VERSION 5.8 ;
BUSBITCHARS "[]" ;
DIVIDERCHAR "/" ;
UNITS
    DATABASE MICRONS 1000 ;
END UNITS

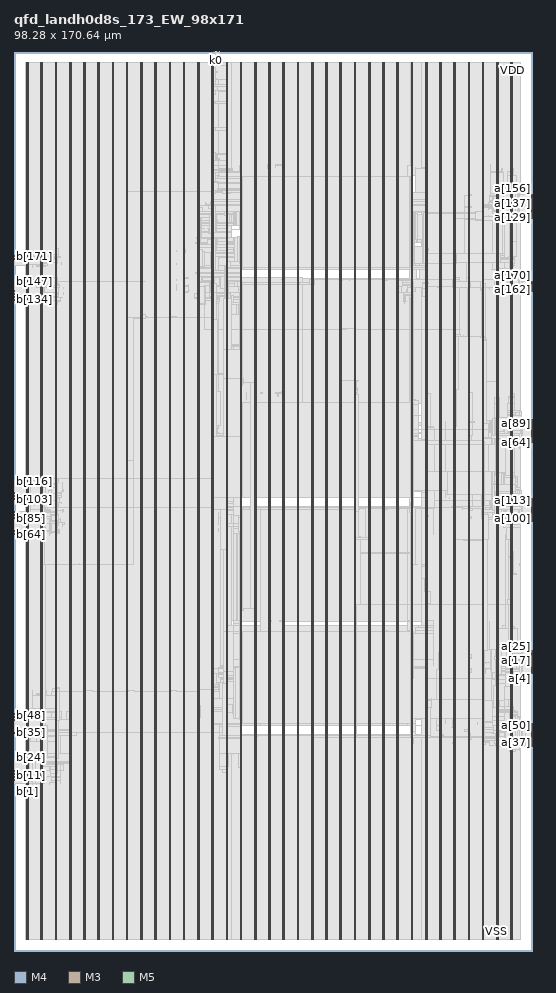
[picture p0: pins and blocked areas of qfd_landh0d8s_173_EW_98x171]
MACRO qfd_landh0d8s_173_EW_98x171
  FOREIGN qfd_landh0d8s_173_EW_98x171 0 0 ;
  CLASS BLOCK ;
  SIZE 98.28 BY 170.64 ;
  PIN a[0]
    DIRECTION INPUT ;
    USE SIGNAL ;
    PORT
      LAYER M4 ;
        RECT  98.196 52.56 98.28 52.584 ;
    END
  END a[0]
  PIN a[100]
    DIRECTION INPUT ;
    USE SIGNAL ;
    PORT
      LAYER M4 ;
        RECT  98.196 81.936 98.28 81.96 ;
    END
  END a[100]
  PIN a[101]
    DIRECTION INPUT ;
    USE SIGNAL ;
    PORT
      LAYER M4 ;
        RECT  98.196 82.08 98.28 82.104 ;
    END
  END a[101]
  PIN a[102]
    DIRECTION INPUT ;
    USE SIGNAL ;
    PORT
      LAYER M4 ;
        RECT  98.196 82.224 98.28 82.248 ;
    END
  END a[102]
  PIN a[103]
    DIRECTION INPUT ;
    USE SIGNAL ;
    PORT
      LAYER M4 ;
        RECT  98.196 82.368 98.28 82.392 ;
    END
  END a[103]
  PIN a[104]
    DIRECTION INPUT ;
    USE SIGNAL ;
    PORT
      LAYER M4 ;
        RECT  98.196 82.512 98.28 82.536 ;
    END
  END a[104]
  PIN a[105]
    DIRECTION INPUT ;
    USE SIGNAL ;
    PORT
      LAYER M4 ;
        RECT  98.196 82.656 98.28 82.68 ;
    END
  END a[105]
  PIN a[106]
    DIRECTION INPUT ;
    USE SIGNAL ;
    PORT
      LAYER M4 ;
        RECT  98.196 82.8 98.28 82.824 ;
    END
  END a[106]
  PIN a[107]
    DIRECTION INPUT ;
    USE SIGNAL ;
    PORT
      LAYER M4 ;
        RECT  98.196 82.944 98.28 82.968 ;
    END
  END a[107]
  PIN a[108]
    DIRECTION INPUT ;
    USE SIGNAL ;
    PORT
      LAYER M4 ;
        RECT  98.196 83.088 98.28 83.112 ;
    END
  END a[108]
  PIN a[109]
    DIRECTION INPUT ;
    USE SIGNAL ;
    PORT
      LAYER M4 ;
        RECT  98.196 83.232 98.28 83.256 ;
    END
  END a[109]
  PIN a[10]
    DIRECTION INPUT ;
    USE SIGNAL ;
    PORT
      LAYER M4 ;
        RECT  98.196 54 98.28 54.024 ;
    END
  END a[10]
  PIN a[110]
    DIRECTION INPUT ;
    USE SIGNAL ;
    PORT
      LAYER M4 ;
        RECT  98.196 83.376 98.28 83.4 ;
    END
  END a[110]
  PIN a[111]
    DIRECTION INPUT ;
    USE SIGNAL ;
    PORT
      LAYER M4 ;
        RECT  98.196 83.52 98.28 83.544 ;
    END
  END a[111]
  PIN a[112]
    DIRECTION INPUT ;
    USE SIGNAL ;
    PORT
      LAYER M4 ;
        RECT  98.196 83.664 98.28 83.688 ;
    END
  END a[112]
  PIN a[113]
    DIRECTION INPUT ;
    USE SIGNAL ;
    PORT
      LAYER M4 ;
        RECT  98.196 83.808 98.28 83.832 ;
    END
  END a[113]
  PIN a[114]
    DIRECTION INPUT ;
    USE SIGNAL ;
    PORT
      LAYER M4 ;
        RECT  98.196 83.952 98.28 83.976 ;
    END
  END a[114]
  PIN a[115]
    DIRECTION INPUT ;
    USE SIGNAL ;
    PORT
      LAYER M4 ;
        RECT  98.196 84.096 98.28 84.12 ;
    END
  END a[115]
  PIN a[116]
    DIRECTION INPUT ;
    USE SIGNAL ;
    PORT
      LAYER M4 ;
        RECT  98.196 84.24 98.28 84.264 ;
    END
  END a[116]
  PIN a[117]
    DIRECTION INPUT ;
    USE SIGNAL ;
    PORT
      LAYER M4 ;
        RECT  98.196 84.384 98.28 84.408 ;
    END
  END a[117]
  PIN a[118]
    DIRECTION INPUT ;
    USE SIGNAL ;
    PORT
      LAYER M4 ;
        RECT  98.196 84.528 98.28 84.552 ;
    END
  END a[118]
  PIN a[119]
    DIRECTION INPUT ;
    USE SIGNAL ;
    PORT
      LAYER M4 ;
        RECT  98.196 84.672 98.28 84.696 ;
    END
  END a[119]
  PIN a[11]
    DIRECTION INPUT ;
    USE SIGNAL ;
    PORT
      LAYER M4 ;
        RECT  98.196 54.144 98.28 54.168 ;
    END
  END a[11]
  PIN a[120]
    DIRECTION INPUT ;
    USE SIGNAL ;
    PORT
      LAYER M4 ;
        RECT  98.196 84.816 98.28 84.84 ;
    END
  END a[120]
  PIN a[121]
    DIRECTION INPUT ;
    USE SIGNAL ;
    PORT
      LAYER M4 ;
        RECT  98.196 84.96 98.28 84.984 ;
    END
  END a[121]
  PIN a[122]
    DIRECTION INPUT ;
    USE SIGNAL ;
    PORT
      LAYER M4 ;
        RECT  98.196 85.104 98.28 85.128 ;
    END
  END a[122]
  PIN a[123]
    DIRECTION INPUT ;
    USE SIGNAL ;
    PORT
      LAYER M4 ;
        RECT  98.196 85.248 98.28 85.272 ;
    END
  END a[123]
  PIN a[124]
    DIRECTION INPUT ;
    USE SIGNAL ;
    PORT
      LAYER M4 ;
        RECT  98.196 85.392 98.28 85.416 ;
    END
  END a[124]
  PIN a[125]
    DIRECTION INPUT ;
    USE SIGNAL ;
    PORT
      LAYER M4 ;
        RECT  98.196 85.536 98.28 85.56 ;
    END
  END a[125]
  PIN a[126]
    DIRECTION INPUT ;
    USE SIGNAL ;
    PORT
      LAYER M4 ;
        RECT  98.196 85.68 98.28 85.704 ;
    END
  END a[126]
  PIN a[127]
    DIRECTION INPUT ;
    USE SIGNAL ;
    PORT
      LAYER M4 ;
        RECT  98.196 85.824 98.28 85.848 ;
    END
  END a[127]
  PIN a[128]
    DIRECTION INPUT ;
    USE SIGNAL ;
    PORT
      LAYER M4 ;
        RECT  98.196 138.96 98.28 138.984 ;
    END
  END a[128]
  PIN a[129]
    DIRECTION INPUT ;
    USE SIGNAL ;
    PORT
      LAYER M4 ;
        RECT  98.196 139.104 98.28 139.128 ;
    END
  END a[129]
  PIN a[12]
    DIRECTION INPUT ;
    USE SIGNAL ;
    PORT
      LAYER M4 ;
        RECT  98.196 54.288 98.28 54.312 ;
    END
  END a[12]
  PIN a[130]
    DIRECTION INPUT ;
    USE SIGNAL ;
    PORT
      LAYER M4 ;
        RECT  98.196 139.248 98.28 139.272 ;
    END
  END a[130]
  PIN a[131]
    DIRECTION INPUT ;
    USE SIGNAL ;
    PORT
      LAYER M4 ;
        RECT  98.196 139.392 98.28 139.416 ;
    END
  END a[131]
  PIN a[132]
    DIRECTION INPUT ;
    USE SIGNAL ;
    PORT
      LAYER M4 ;
        RECT  98.196 139.536 98.28 139.56 ;
    END
  END a[132]
  PIN a[133]
    DIRECTION INPUT ;
    USE SIGNAL ;
    PORT
      LAYER M4 ;
        RECT  98.196 139.68 98.28 139.704 ;
    END
  END a[133]
  PIN a[134]
    DIRECTION INPUT ;
    USE SIGNAL ;
    PORT
      LAYER M4 ;
        RECT  98.196 139.824 98.28 139.848 ;
    END
  END a[134]
  PIN a[135]
    DIRECTION INPUT ;
    USE SIGNAL ;
    PORT
      LAYER M4 ;
        RECT  98.196 139.968 98.28 139.992 ;
    END
  END a[135]
  PIN a[136]
    DIRECTION INPUT ;
    USE SIGNAL ;
    PORT
      LAYER M4 ;
        RECT  98.196 140.112 98.28 140.136 ;
    END
  END a[136]
  PIN a[137]
    DIRECTION INPUT ;
    USE SIGNAL ;
    PORT
      LAYER M4 ;
        RECT  98.196 140.256 98.28 140.28 ;
    END
  END a[137]
  PIN a[138]
    DIRECTION INPUT ;
    USE SIGNAL ;
    PORT
      LAYER M4 ;
        RECT  98.196 140.4 98.28 140.424 ;
    END
  END a[138]
  PIN a[139]
    DIRECTION INPUT ;
    USE SIGNAL ;
    PORT
      LAYER M4 ;
        RECT  98.196 140.544 98.28 140.568 ;
    END
  END a[139]
  PIN a[13]
    DIRECTION INPUT ;
    USE SIGNAL ;
    PORT
      LAYER M4 ;
        RECT  98.196 54.432 98.28 54.456 ;
    END
  END a[13]
  PIN a[140]
    DIRECTION INPUT ;
    USE SIGNAL ;
    PORT
      LAYER M4 ;
        RECT  98.196 140.688 98.28 140.712 ;
    END
  END a[140]
  PIN a[141]
    DIRECTION INPUT ;
    USE SIGNAL ;
    PORT
      LAYER M4 ;
        RECT  98.196 140.832 98.28 140.856 ;
    END
  END a[141]
  PIN a[142]
    DIRECTION INPUT ;
    USE SIGNAL ;
    PORT
      LAYER M4 ;
        RECT  98.196 140.976 98.28 141 ;
    END
  END a[142]
  PIN a[143]
    DIRECTION INPUT ;
    USE SIGNAL ;
    PORT
      LAYER M4 ;
        RECT  98.196 141.12 98.28 141.144 ;
    END
  END a[143]
  PIN a[144]
    DIRECTION INPUT ;
    USE SIGNAL ;
    PORT
      LAYER M4 ;
        RECT  98.196 141.264 98.28 141.288 ;
    END
  END a[144]
  PIN a[145]
    DIRECTION INPUT ;
    USE SIGNAL ;
    PORT
      LAYER M4 ;
        RECT  98.196 141.408 98.28 141.432 ;
    END
  END a[145]
  PIN a[146]
    DIRECTION INPUT ;
    USE SIGNAL ;
    PORT
      LAYER M4 ;
        RECT  98.196 141.552 98.28 141.576 ;
    END
  END a[146]
  PIN a[147]
    DIRECTION INPUT ;
    USE SIGNAL ;
    PORT
      LAYER M4 ;
        RECT  98.196 141.696 98.28 141.72 ;
    END
  END a[147]
  PIN a[148]
    DIRECTION INPUT ;
    USE SIGNAL ;
    PORT
      LAYER M4 ;
        RECT  98.196 141.84 98.28 141.864 ;
    END
  END a[148]
  PIN a[149]
    DIRECTION INPUT ;
    USE SIGNAL ;
    PORT
      LAYER M4 ;
        RECT  98.196 141.984 98.28 142.008 ;
    END
  END a[149]
  PIN a[14]
    DIRECTION INPUT ;
    USE SIGNAL ;
    PORT
      LAYER M4 ;
        RECT  98.196 54.576 98.28 54.6 ;
    END
  END a[14]
  PIN a[150]
    DIRECTION INPUT ;
    USE SIGNAL ;
    PORT
      LAYER M4 ;
        RECT  98.196 142.128 98.28 142.152 ;
    END
  END a[150]
  PIN a[151]
    DIRECTION INPUT ;
    USE SIGNAL ;
    PORT
      LAYER M4 ;
        RECT  98.196 142.272 98.28 142.296 ;
    END
  END a[151]
  PIN a[152]
    DIRECTION INPUT ;
    USE SIGNAL ;
    PORT
      LAYER M4 ;
        RECT  98.196 142.416 98.28 142.44 ;
    END
  END a[152]
  PIN a[153]
    DIRECTION INPUT ;
    USE SIGNAL ;
    PORT
      LAYER M4 ;
        RECT  98.196 142.56 98.28 142.584 ;
    END
  END a[153]
  PIN a[154]
    DIRECTION INPUT ;
    USE SIGNAL ;
    PORT
      LAYER M4 ;
        RECT  98.196 142.704 98.28 142.728 ;
    END
  END a[154]
  PIN a[155]
    DIRECTION INPUT ;
    USE SIGNAL ;
    PORT
      LAYER M4 ;
        RECT  98.196 142.848 98.28 142.872 ;
    END
  END a[155]
  PIN a[156]
    DIRECTION INPUT ;
    USE SIGNAL ;
    PORT
      LAYER M4 ;
        RECT  98.196 142.992 98.28 143.016 ;
    END
  END a[156]
  PIN a[157]
    DIRECTION INPUT ;
    USE SIGNAL ;
    PORT
      LAYER M4 ;
        RECT  98.196 143.136 98.28 143.16 ;
    END
  END a[157]
  PIN a[158]
    DIRECTION INPUT ;
    USE SIGNAL ;
    PORT
      LAYER M4 ;
        RECT  98.196 143.28 98.28 143.304 ;
    END
  END a[158]
  PIN a[159]
    DIRECTION INPUT ;
    USE SIGNAL ;
    PORT
      LAYER M4 ;
        RECT  98.196 143.424 98.28 143.448 ;
    END
  END a[159]
  PIN a[15]
    DIRECTION INPUT ;
    USE SIGNAL ;
    PORT
      LAYER M4 ;
        RECT  98.196 54.72 98.28 54.744 ;
    END
  END a[15]
  PIN a[160]
    DIRECTION INPUT ;
    USE SIGNAL ;
    PORT
      LAYER M4 ;
        RECT  98.196 125.136 98.28 125.16 ;
    END
  END a[160]
  PIN a[161]
    DIRECTION INPUT ;
    USE SIGNAL ;
    PORT
      LAYER M4 ;
        RECT  98.196 125.28 98.28 125.304 ;
    END
  END a[161]
  PIN a[162]
    DIRECTION INPUT ;
    USE SIGNAL ;
    PORT
      LAYER M4 ;
        RECT  98.196 125.424 98.28 125.448 ;
    END
  END a[162]
  PIN a[163]
    DIRECTION INPUT ;
    USE SIGNAL ;
    PORT
      LAYER M4 ;
        RECT  98.196 125.568 98.28 125.592 ;
    END
  END a[163]
  PIN a[164]
    DIRECTION INPUT ;
    USE SIGNAL ;
    PORT
      LAYER M4 ;
        RECT  98.196 125.712 98.28 125.736 ;
    END
  END a[164]
  PIN a[165]
    DIRECTION INPUT ;
    USE SIGNAL ;
    PORT
      LAYER M4 ;
        RECT  98.196 125.856 98.28 125.88 ;
    END
  END a[165]
  PIN a[166]
    DIRECTION INPUT ;
    USE SIGNAL ;
    PORT
      LAYER M4 ;
        RECT  98.196 126 98.28 126.024 ;
    END
  END a[166]
  PIN a[167]
    DIRECTION INPUT ;
    USE SIGNAL ;
    PORT
      LAYER M4 ;
        RECT  98.196 126.144 98.28 126.168 ;
    END
  END a[167]
  PIN a[168]
    DIRECTION INPUT ;
    USE SIGNAL ;
    PORT
      LAYER M4 ;
        RECT  98.196 126.288 98.28 126.312 ;
    END
  END a[168]
  PIN a[169]
    DIRECTION INPUT ;
    USE SIGNAL ;
    PORT
      LAYER M4 ;
        RECT  98.196 126.432 98.28 126.456 ;
    END
  END a[169]
  PIN a[16]
    DIRECTION INPUT ;
    USE SIGNAL ;
    PORT
      LAYER M4 ;
        RECT  98.196 54.864 98.28 54.888 ;
    END
  END a[16]
  PIN a[170]
    DIRECTION INPUT ;
    USE SIGNAL ;
    PORT
      LAYER M4 ;
        RECT  98.196 126.576 98.28 126.6 ;
    END
  END a[170]
  PIN a[171]
    DIRECTION INPUT ;
    USE SIGNAL ;
    PORT
      LAYER M4 ;
        RECT  98.196 126.72 98.28 126.744 ;
    END
  END a[171]
  PIN a[172]
    DIRECTION INPUT ;
    USE SIGNAL ;
    PORT
      LAYER M4 ;
        RECT  98.196 126.864 98.28 126.888 ;
    END
  END a[172]
  PIN a[17]
    DIRECTION INPUT ;
    USE SIGNAL ;
    PORT
      LAYER M4 ;
        RECT  98.196 55.008 98.28 55.032 ;
    END
  END a[17]
  PIN a[18]
    DIRECTION INPUT ;
    USE SIGNAL ;
    PORT
      LAYER M4 ;
        RECT  98.196 55.152 98.28 55.176 ;
    END
  END a[18]
  PIN a[19]
    DIRECTION INPUT ;
    USE SIGNAL ;
    PORT
      LAYER M4 ;
        RECT  98.196 55.296 98.28 55.32 ;
    END
  END a[19]
  PIN a[1]
    DIRECTION INPUT ;
    USE SIGNAL ;
    PORT
      LAYER M4 ;
        RECT  98.196 52.704 98.28 52.728 ;
    END
  END a[1]
  PIN a[20]
    DIRECTION INPUT ;
    USE SIGNAL ;
    PORT
      LAYER M4 ;
        RECT  98.196 55.44 98.28 55.464 ;
    END
  END a[20]
  PIN a[21]
    DIRECTION INPUT ;
    USE SIGNAL ;
    PORT
      LAYER M4 ;
        RECT  98.196 55.584 98.28 55.608 ;
    END
  END a[21]
  PIN a[22]
    DIRECTION INPUT ;
    USE SIGNAL ;
    PORT
      LAYER M4 ;
        RECT  98.196 55.728 98.28 55.752 ;
    END
  END a[22]
  PIN a[23]
    DIRECTION INPUT ;
    USE SIGNAL ;
    PORT
      LAYER M4 ;
        RECT  98.196 55.872 98.28 55.896 ;
    END
  END a[23]
  PIN a[24]
    DIRECTION INPUT ;
    USE SIGNAL ;
    PORT
      LAYER M4 ;
        RECT  98.196 56.016 98.28 56.04 ;
    END
  END a[24]
  PIN a[25]
    DIRECTION INPUT ;
    USE SIGNAL ;
    PORT
      LAYER M4 ;
        RECT  98.196 56.16 98.28 56.184 ;
    END
  END a[25]
  PIN a[26]
    DIRECTION INPUT ;
    USE SIGNAL ;
    PORT
      LAYER M4 ;
        RECT  98.196 56.304 98.28 56.328 ;
    END
  END a[26]
  PIN a[27]
    DIRECTION INPUT ;
    USE SIGNAL ;
    PORT
      LAYER M4 ;
        RECT  98.196 56.448 98.28 56.472 ;
    END
  END a[27]
  PIN a[28]
    DIRECTION INPUT ;
    USE SIGNAL ;
    PORT
      LAYER M4 ;
        RECT  98.196 56.592 98.28 56.616 ;
    END
  END a[28]
  PIN a[29]
    DIRECTION INPUT ;
    USE SIGNAL ;
    PORT
      LAYER M4 ;
        RECT  98.196 56.736 98.28 56.76 ;
    END
  END a[29]
  PIN a[2]
    DIRECTION INPUT ;
    USE SIGNAL ;
    PORT
      LAYER M4 ;
        RECT  98.196 52.848 98.28 52.872 ;
    END
  END a[2]
  PIN a[30]
    DIRECTION INPUT ;
    USE SIGNAL ;
    PORT
      LAYER M4 ;
        RECT  98.196 56.88 98.28 56.904 ;
    END
  END a[30]
  PIN a[31]
    DIRECTION INPUT ;
    USE SIGNAL ;
    PORT
      LAYER M4 ;
        RECT  98.196 57.024 98.28 57.048 ;
    END
  END a[31]
  PIN a[32]
    DIRECTION INPUT ;
    USE SIGNAL ;
    PORT
      LAYER M4 ;
        RECT  98.196 38.736 98.28 38.76 ;
    END
  END a[32]
  PIN a[33]
    DIRECTION INPUT ;
    USE SIGNAL ;
    PORT
      LAYER M4 ;
        RECT  98.196 38.88 98.28 38.904 ;
    END
  END a[33]
  PIN a[34]
    DIRECTION INPUT ;
    USE SIGNAL ;
    PORT
      LAYER M4 ;
        RECT  98.196 39.024 98.28 39.048 ;
    END
  END a[34]
  PIN a[35]
    DIRECTION INPUT ;
    USE SIGNAL ;
    PORT
      LAYER M4 ;
        RECT  98.196 39.168 98.28 39.192 ;
    END
  END a[35]
  PIN a[36]
    DIRECTION INPUT ;
    USE SIGNAL ;
    PORT
      LAYER M4 ;
        RECT  98.196 39.312 98.28 39.336 ;
    END
  END a[36]
  PIN a[37]
    DIRECTION INPUT ;
    USE SIGNAL ;
    PORT
      LAYER M4 ;
        RECT  98.196 39.456 98.28 39.48 ;
    END
  END a[37]
  PIN a[38]
    DIRECTION INPUT ;
    USE SIGNAL ;
    PORT
      LAYER M4 ;
        RECT  98.196 39.6 98.28 39.624 ;
    END
  END a[38]
  PIN a[39]
    DIRECTION INPUT ;
    USE SIGNAL ;
    PORT
      LAYER M4 ;
        RECT  98.196 39.744 98.28 39.768 ;
    END
  END a[39]
  PIN a[3]
    DIRECTION INPUT ;
    USE SIGNAL ;
    PORT
      LAYER M4 ;
        RECT  98.196 52.992 98.28 53.016 ;
    END
  END a[3]
  PIN a[40]
    DIRECTION INPUT ;
    USE SIGNAL ;
    PORT
      LAYER M4 ;
        RECT  98.196 39.888 98.28 39.912 ;
    END
  END a[40]
  PIN a[41]
    DIRECTION INPUT ;
    USE SIGNAL ;
    PORT
      LAYER M4 ;
        RECT  98.196 40.032 98.28 40.056 ;
    END
  END a[41]
  PIN a[42]
    DIRECTION INPUT ;
    USE SIGNAL ;
    PORT
      LAYER M4 ;
        RECT  98.196 40.176 98.28 40.2 ;
    END
  END a[42]
  PIN a[43]
    DIRECTION INPUT ;
    USE SIGNAL ;
    PORT
      LAYER M4 ;
        RECT  98.196 40.32 98.28 40.344 ;
    END
  END a[43]
  PIN a[44]
    DIRECTION INPUT ;
    USE SIGNAL ;
    PORT
      LAYER M4 ;
        RECT  98.196 40.464 98.28 40.488 ;
    END
  END a[44]
  PIN a[45]
    DIRECTION INPUT ;
    USE SIGNAL ;
    PORT
      LAYER M4 ;
        RECT  98.196 40.608 98.28 40.632 ;
    END
  END a[45]
  PIN a[46]
    DIRECTION INPUT ;
    USE SIGNAL ;
    PORT
      LAYER M4 ;
        RECT  98.196 40.752 98.28 40.776 ;
    END
  END a[46]
  PIN a[47]
    DIRECTION INPUT ;
    USE SIGNAL ;
    PORT
      LAYER M4 ;
        RECT  98.196 40.896 98.28 40.92 ;
    END
  END a[47]
  PIN a[48]
    DIRECTION INPUT ;
    USE SIGNAL ;
    PORT
      LAYER M4 ;
        RECT  98.196 41.04 98.28 41.064 ;
    END
  END a[48]
  PIN a[49]
    DIRECTION INPUT ;
    USE SIGNAL ;
    PORT
      LAYER M4 ;
        RECT  98.196 41.184 98.28 41.208 ;
    END
  END a[49]
  PIN a[4]
    DIRECTION INPUT ;
    USE SIGNAL ;
    PORT
      LAYER M4 ;
        RECT  98.196 53.136 98.28 53.16 ;
    END
  END a[4]
  PIN a[50]
    DIRECTION INPUT ;
    USE SIGNAL ;
    PORT
      LAYER M4 ;
        RECT  98.196 41.328 98.28 41.352 ;
    END
  END a[50]
  PIN a[51]
    DIRECTION INPUT ;
    USE SIGNAL ;
    PORT
      LAYER M4 ;
        RECT  98.196 41.472 98.28 41.496 ;
    END
  END a[51]
  PIN a[52]
    DIRECTION INPUT ;
    USE SIGNAL ;
    PORT
      LAYER M4 ;
        RECT  98.196 41.616 98.28 41.64 ;
    END
  END a[52]
  PIN a[53]
    DIRECTION INPUT ;
    USE SIGNAL ;
    PORT
      LAYER M4 ;
        RECT  98.196 41.76 98.28 41.784 ;
    END
  END a[53]
  PIN a[54]
    DIRECTION INPUT ;
    USE SIGNAL ;
    PORT
      LAYER M4 ;
        RECT  98.196 41.904 98.28 41.928 ;
    END
  END a[54]
  PIN a[55]
    DIRECTION INPUT ;
    USE SIGNAL ;
    PORT
      LAYER M4 ;
        RECT  98.196 42.048 98.28 42.072 ;
    END
  END a[55]
  PIN a[56]
    DIRECTION INPUT ;
    USE SIGNAL ;
    PORT
      LAYER M4 ;
        RECT  98.196 42.192 98.28 42.216 ;
    END
  END a[56]
  PIN a[57]
    DIRECTION INPUT ;
    USE SIGNAL ;
    PORT
      LAYER M4 ;
        RECT  98.196 42.336 98.28 42.36 ;
    END
  END a[57]
  PIN a[58]
    DIRECTION INPUT ;
    USE SIGNAL ;
    PORT
      LAYER M4 ;
        RECT  98.196 42.48 98.28 42.504 ;
    END
  END a[58]
  PIN a[59]
    DIRECTION INPUT ;
    USE SIGNAL ;
    PORT
      LAYER M4 ;
        RECT  98.196 42.624 98.28 42.648 ;
    END
  END a[59]
  PIN a[5]
    DIRECTION INPUT ;
    USE SIGNAL ;
    PORT
      LAYER M4 ;
        RECT  98.196 53.28 98.28 53.304 ;
    END
  END a[5]
  PIN a[60]
    DIRECTION INPUT ;
    USE SIGNAL ;
    PORT
      LAYER M4 ;
        RECT  98.196 42.768 98.28 42.792 ;
    END
  END a[60]
  PIN a[61]
    DIRECTION INPUT ;
    USE SIGNAL ;
    PORT
      LAYER M4 ;
        RECT  98.196 42.912 98.28 42.936 ;
    END
  END a[61]
  PIN a[62]
    DIRECTION INPUT ;
    USE SIGNAL ;
    PORT
      LAYER M4 ;
        RECT  98.196 43.056 98.28 43.08 ;
    END
  END a[62]
  PIN a[63]
    DIRECTION INPUT ;
    USE SIGNAL ;
    PORT
      LAYER M4 ;
        RECT  98.196 43.2 98.28 43.224 ;
    END
  END a[63]
  PIN a[64]
    DIRECTION INPUT ;
    USE SIGNAL ;
    PORT
      LAYER M4 ;
        RECT  98.196 96.336 98.28 96.36 ;
    END
  END a[64]
  PIN a[65]
    DIRECTION INPUT ;
    USE SIGNAL ;
    PORT
      LAYER M4 ;
        RECT  98.196 96.48 98.28 96.504 ;
    END
  END a[65]
  PIN a[66]
    DIRECTION INPUT ;
    USE SIGNAL ;
    PORT
      LAYER M4 ;
        RECT  98.196 96.624 98.28 96.648 ;
    END
  END a[66]
  PIN a[67]
    DIRECTION INPUT ;
    USE SIGNAL ;
    PORT
      LAYER M4 ;
        RECT  98.196 96.768 98.28 96.792 ;
    END
  END a[67]
  PIN a[68]
    DIRECTION INPUT ;
    USE SIGNAL ;
    PORT
      LAYER M4 ;
        RECT  98.196 96.912 98.28 96.936 ;
    END
  END a[68]
  PIN a[69]
    DIRECTION INPUT ;
    USE SIGNAL ;
    PORT
      LAYER M4 ;
        RECT  98.196 97.056 98.28 97.08 ;
    END
  END a[69]
  PIN a[6]
    DIRECTION INPUT ;
    USE SIGNAL ;
    PORT
      LAYER M4 ;
        RECT  98.196 53.424 98.28 53.448 ;
    END
  END a[6]
  PIN a[70]
    DIRECTION INPUT ;
    USE SIGNAL ;
    PORT
      LAYER M4 ;
        RECT  98.196 97.2 98.28 97.224 ;
    END
  END a[70]
  PIN a[71]
    DIRECTION INPUT ;
    USE SIGNAL ;
    PORT
      LAYER M4 ;
        RECT  98.196 97.344 98.28 97.368 ;
    END
  END a[71]
  PIN a[72]
    DIRECTION INPUT ;
    USE SIGNAL ;
    PORT
      LAYER M4 ;
        RECT  98.196 97.488 98.28 97.512 ;
    END
  END a[72]
  PIN a[73]
    DIRECTION INPUT ;
    USE SIGNAL ;
    PORT
      LAYER M4 ;
        RECT  98.196 97.632 98.28 97.656 ;
    END
  END a[73]
  PIN a[74]
    DIRECTION INPUT ;
    USE SIGNAL ;
    PORT
      LAYER M4 ;
        RECT  98.196 97.776 98.28 97.8 ;
    END
  END a[74]
  PIN a[75]
    DIRECTION INPUT ;
    USE SIGNAL ;
    PORT
      LAYER M4 ;
        RECT  98.196 97.92 98.28 97.944 ;
    END
  END a[75]
  PIN a[76]
    DIRECTION INPUT ;
    USE SIGNAL ;
    PORT
      LAYER M4 ;
        RECT  98.196 98.064 98.28 98.088 ;
    END
  END a[76]
  PIN a[77]
    DIRECTION INPUT ;
    USE SIGNAL ;
    PORT
      LAYER M4 ;
        RECT  98.196 98.208 98.28 98.232 ;
    END
  END a[77]
  PIN a[78]
    DIRECTION INPUT ;
    USE SIGNAL ;
    PORT
      LAYER M4 ;
        RECT  98.196 98.352 98.28 98.376 ;
    END
  END a[78]
  PIN a[79]
    DIRECTION INPUT ;
    USE SIGNAL ;
    PORT
      LAYER M4 ;
        RECT  98.196 98.496 98.28 98.52 ;
    END
  END a[79]
  PIN a[7]
    DIRECTION INPUT ;
    USE SIGNAL ;
    PORT
      LAYER M4 ;
        RECT  98.196 53.568 98.28 53.592 ;
    END
  END a[7]
  PIN a[80]
    DIRECTION INPUT ;
    USE SIGNAL ;
    PORT
      LAYER M4 ;
        RECT  98.196 98.64 98.28 98.664 ;
    END
  END a[80]
  PIN a[81]
    DIRECTION INPUT ;
    USE SIGNAL ;
    PORT
      LAYER M4 ;
        RECT  98.196 98.784 98.28 98.808 ;
    END
  END a[81]
  PIN a[82]
    DIRECTION INPUT ;
    USE SIGNAL ;
    PORT
      LAYER M4 ;
        RECT  98.196 98.928 98.28 98.952 ;
    END
  END a[82]
  PIN a[83]
    DIRECTION INPUT ;
    USE SIGNAL ;
    PORT
      LAYER M4 ;
        RECT  98.196 99.072 98.28 99.096 ;
    END
  END a[83]
  PIN a[84]
    DIRECTION INPUT ;
    USE SIGNAL ;
    PORT
      LAYER M4 ;
        RECT  98.196 99.216 98.28 99.24 ;
    END
  END a[84]
  PIN a[85]
    DIRECTION INPUT ;
    USE SIGNAL ;
    PORT
      LAYER M4 ;
        RECT  98.196 99.36 98.28 99.384 ;
    END
  END a[85]
  PIN a[86]
    DIRECTION INPUT ;
    USE SIGNAL ;
    PORT
      LAYER M4 ;
        RECT  98.196 99.504 98.28 99.528 ;
    END
  END a[86]
  PIN a[87]
    DIRECTION INPUT ;
    USE SIGNAL ;
    PORT
      LAYER M4 ;
        RECT  98.196 99.648 98.28 99.672 ;
    END
  END a[87]
  PIN a[88]
    DIRECTION INPUT ;
    USE SIGNAL ;
    PORT
      LAYER M4 ;
        RECT  98.196 99.792 98.28 99.816 ;
    END
  END a[88]
  PIN a[89]
    DIRECTION INPUT ;
    USE SIGNAL ;
    PORT
      LAYER M4 ;
        RECT  98.196 99.936 98.28 99.96 ;
    END
  END a[89]
  PIN a[8]
    DIRECTION INPUT ;
    USE SIGNAL ;
    PORT
      LAYER M4 ;
        RECT  98.196 53.712 98.28 53.736 ;
    END
  END a[8]
  PIN a[90]
    DIRECTION INPUT ;
    USE SIGNAL ;
    PORT
      LAYER M4 ;
        RECT  98.196 100.08 98.28 100.104 ;
    END
  END a[90]
  PIN a[91]
    DIRECTION INPUT ;
    USE SIGNAL ;
    PORT
      LAYER M4 ;
        RECT  98.196 100.224 98.28 100.248 ;
    END
  END a[91]
  PIN a[92]
    DIRECTION INPUT ;
    USE SIGNAL ;
    PORT
      LAYER M4 ;
        RECT  98.196 100.368 98.28 100.392 ;
    END
  END a[92]
  PIN a[93]
    DIRECTION INPUT ;
    USE SIGNAL ;
    PORT
      LAYER M4 ;
        RECT  98.196 100.512 98.28 100.536 ;
    END
  END a[93]
  PIN a[94]
    DIRECTION INPUT ;
    USE SIGNAL ;
    PORT
      LAYER M4 ;
        RECT  98.196 100.656 98.28 100.68 ;
    END
  END a[94]
  PIN a[95]
    DIRECTION INPUT ;
    USE SIGNAL ;
    PORT
      LAYER M4 ;
        RECT  98.196 100.8 98.28 100.824 ;
    END
  END a[95]
  PIN a[96]
    DIRECTION INPUT ;
    USE SIGNAL ;
    PORT
      LAYER M4 ;
        RECT  98.196 81.36 98.28 81.384 ;
    END
  END a[96]
  PIN a[97]
    DIRECTION INPUT ;
    USE SIGNAL ;
    PORT
      LAYER M4 ;
        RECT  98.196 81.504 98.28 81.528 ;
    END
  END a[97]
  PIN a[98]
    DIRECTION INPUT ;
    USE SIGNAL ;
    PORT
      LAYER M4 ;
        RECT  98.196 81.648 98.28 81.672 ;
    END
  END a[98]
  PIN a[99]
    DIRECTION INPUT ;
    USE SIGNAL ;
    PORT
      LAYER M4 ;
        RECT  98.196 81.792 98.28 81.816 ;
    END
  END a[99]
  PIN a[9]
    DIRECTION INPUT ;
    USE SIGNAL ;
    PORT
      LAYER M4 ;
        RECT  98.196 53.856 98.28 53.88 ;
    END
  END a[9]
  PIN b[0]
    DIRECTION OUTPUT ;
    USE SIGNAL ;
    PORT
      LAYER M4 ;
        RECT  0 31.68 0.084 31.704 ;
    END
  END b[0]
  PIN b[100]
    DIRECTION OUTPUT ;
    USE SIGNAL ;
    PORT
      LAYER M4 ;
        RECT  0 85.248 0.084 85.272 ;
    END
  END b[100]
  PIN b[101]
    DIRECTION OUTPUT ;
    USE SIGNAL ;
    PORT
      LAYER M4 ;
        RECT  0 85.392 0.084 85.416 ;
    END
  END b[101]
  PIN b[102]
    DIRECTION OUTPUT ;
    USE SIGNAL ;
    PORT
      LAYER M4 ;
        RECT  0 85.536 0.084 85.56 ;
    END
  END b[102]
  PIN b[103]
    DIRECTION OUTPUT ;
    USE SIGNAL ;
    PORT
      LAYER M4 ;
        RECT  0 85.68 0.084 85.704 ;
    END
  END b[103]
  PIN b[104]
    DIRECTION OUTPUT ;
    USE SIGNAL ;
    PORT
      LAYER M4 ;
        RECT  0 85.824 0.084 85.848 ;
    END
  END b[104]
  PIN b[105]
    DIRECTION OUTPUT ;
    USE SIGNAL ;
    PORT
      LAYER M4 ;
        RECT  0 85.968 0.084 85.992 ;
    END
  END b[105]
  PIN b[106]
    DIRECTION OUTPUT ;
    USE SIGNAL ;
    PORT
      LAYER M4 ;
        RECT  0 86.112 0.084 86.136 ;
    END
  END b[106]
  PIN b[107]
    DIRECTION OUTPUT ;
    USE SIGNAL ;
    PORT
      LAYER M4 ;
        RECT  0 86.256 0.084 86.28 ;
    END
  END b[107]
  PIN b[108]
    DIRECTION OUTPUT ;
    USE SIGNAL ;
    PORT
      LAYER M4 ;
        RECT  0 86.4 0.084 86.424 ;
    END
  END b[108]
  PIN b[109]
    DIRECTION OUTPUT ;
    USE SIGNAL ;
    PORT
      LAYER M4 ;
        RECT  0 86.544 0.084 86.568 ;
    END
  END b[109]
  PIN b[10]
    DIRECTION OUTPUT ;
    USE SIGNAL ;
    PORT
      LAYER M4 ;
        RECT  0 33.12 0.084 33.144 ;
    END
  END b[10]
  PIN b[110]
    DIRECTION OUTPUT ;
    USE SIGNAL ;
    PORT
      LAYER M4 ;
        RECT  0 86.688 0.084 86.712 ;
    END
  END b[110]
  PIN b[111]
    DIRECTION OUTPUT ;
    USE SIGNAL ;
    PORT
      LAYER M4 ;
        RECT  0 86.832 0.084 86.856 ;
    END
  END b[111]
  PIN b[112]
    DIRECTION OUTPUT ;
    USE SIGNAL ;
    PORT
      LAYER M4 ;
        RECT  0 86.976 0.084 87 ;
    END
  END b[112]
  PIN b[113]
    DIRECTION OUTPUT ;
    USE SIGNAL ;
    PORT
      LAYER M4 ;
        RECT  0 87.12 0.084 87.144 ;
    END
  END b[113]
  PIN b[114]
    DIRECTION OUTPUT ;
    USE SIGNAL ;
    PORT
      LAYER M4 ;
        RECT  0 87.264 0.084 87.288 ;
    END
  END b[114]
  PIN b[115]
    DIRECTION OUTPUT ;
    USE SIGNAL ;
    PORT
      LAYER M4 ;
        RECT  0 87.408 0.084 87.432 ;
    END
  END b[115]
  PIN b[116]
    DIRECTION OUTPUT ;
    USE SIGNAL ;
    PORT
      LAYER M4 ;
        RECT  0 87.552 0.084 87.576 ;
    END
  END b[116]
  PIN b[117]
    DIRECTION OUTPUT ;
    USE SIGNAL ;
    PORT
      LAYER M4 ;
        RECT  0 87.696 0.084 87.72 ;
    END
  END b[117]
  PIN b[118]
    DIRECTION OUTPUT ;
    USE SIGNAL ;
    PORT
      LAYER M4 ;
        RECT  0 87.84 0.084 87.864 ;
    END
  END b[118]
  PIN b[119]
    DIRECTION OUTPUT ;
    USE SIGNAL ;
    PORT
      LAYER M4 ;
        RECT  0 87.984 0.084 88.008 ;
    END
  END b[119]
  PIN b[11]
    DIRECTION OUTPUT ;
    USE SIGNAL ;
    PORT
      LAYER M4 ;
        RECT  0 33.264 0.084 33.288 ;
    END
  END b[11]
  PIN b[120]
    DIRECTION OUTPUT ;
    USE SIGNAL ;
    PORT
      LAYER M4 ;
        RECT  0 88.128 0.084 88.152 ;
    END
  END b[120]
  PIN b[121]
    DIRECTION OUTPUT ;
    USE SIGNAL ;
    PORT
      LAYER M4 ;
        RECT  0 88.272 0.084 88.296 ;
    END
  END b[121]
  PIN b[122]
    DIRECTION OUTPUT ;
    USE SIGNAL ;
    PORT
      LAYER M4 ;
        RECT  0 88.416 0.084 88.44 ;
    END
  END b[122]
  PIN b[123]
    DIRECTION OUTPUT ;
    USE SIGNAL ;
    PORT
      LAYER M4 ;
        RECT  0 88.56 0.084 88.584 ;
    END
  END b[123]
  PIN b[124]
    DIRECTION OUTPUT ;
    USE SIGNAL ;
    PORT
      LAYER M4 ;
        RECT  0 88.704 0.084 88.728 ;
    END
  END b[124]
  PIN b[125]
    DIRECTION OUTPUT ;
    USE SIGNAL ;
    PORT
      LAYER M4 ;
        RECT  0 88.848 0.084 88.872 ;
    END
  END b[125]
  PIN b[126]
    DIRECTION OUTPUT ;
    USE SIGNAL ;
    PORT
      LAYER M4 ;
        RECT  0 88.992 0.084 89.016 ;
    END
  END b[126]
  PIN b[127]
    DIRECTION OUTPUT ;
    USE SIGNAL ;
    PORT
      LAYER M4 ;
        RECT  0 89.136 0.084 89.16 ;
    END
  END b[127]
  PIN b[128]
    DIRECTION OUTPUT ;
    USE SIGNAL ;
    PORT
      LAYER M4 ;
        RECT  0 122.688 0.084 122.712 ;
    END
  END b[128]
  PIN b[129]
    DIRECTION OUTPUT ;
    USE SIGNAL ;
    PORT
      LAYER M4 ;
        RECT  0 122.832 0.084 122.856 ;
    END
  END b[129]
  PIN b[12]
    DIRECTION OUTPUT ;
    USE SIGNAL ;
    PORT
      LAYER M4 ;
        RECT  0 33.408 0.084 33.432 ;
    END
  END b[12]
  PIN b[130]
    DIRECTION OUTPUT ;
    USE SIGNAL ;
    PORT
      LAYER M4 ;
        RECT  0 122.976 0.084 123 ;
    END
  END b[130]
  PIN b[131]
    DIRECTION OUTPUT ;
    USE SIGNAL ;
    PORT
      LAYER M4 ;
        RECT  0 123.12 0.084 123.144 ;
    END
  END b[131]
  PIN b[132]
    DIRECTION OUTPUT ;
    USE SIGNAL ;
    PORT
      LAYER M4 ;
        RECT  0 123.264 0.084 123.288 ;
    END
  END b[132]
  PIN b[133]
    DIRECTION OUTPUT ;
    USE SIGNAL ;
    PORT
      LAYER M4 ;
        RECT  0 123.408 0.084 123.432 ;
    END
  END b[133]
  PIN b[134]
    DIRECTION OUTPUT ;
    USE SIGNAL ;
    PORT
      LAYER M4 ;
        RECT  0 123.552 0.084 123.576 ;
    END
  END b[134]
  PIN b[135]
    DIRECTION OUTPUT ;
    USE SIGNAL ;
    PORT
      LAYER M4 ;
        RECT  0 123.696 0.084 123.72 ;
    END
  END b[135]
  PIN b[136]
    DIRECTION OUTPUT ;
    USE SIGNAL ;
    PORT
      LAYER M4 ;
        RECT  0 123.84 0.084 123.864 ;
    END
  END b[136]
  PIN b[137]
    DIRECTION OUTPUT ;
    USE SIGNAL ;
    PORT
      LAYER M4 ;
        RECT  0 123.984 0.084 124.008 ;
    END
  END b[137]
  PIN b[138]
    DIRECTION OUTPUT ;
    USE SIGNAL ;
    PORT
      LAYER M4 ;
        RECT  0 124.128 0.084 124.152 ;
    END
  END b[138]
  PIN b[139]
    DIRECTION OUTPUT ;
    USE SIGNAL ;
    PORT
      LAYER M4 ;
        RECT  0 124.272 0.084 124.296 ;
    END
  END b[139]
  PIN b[13]
    DIRECTION OUTPUT ;
    USE SIGNAL ;
    PORT
      LAYER M4 ;
        RECT  0 33.552 0.084 33.576 ;
    END
  END b[13]
  PIN b[140]
    DIRECTION OUTPUT ;
    USE SIGNAL ;
    PORT
      LAYER M4 ;
        RECT  0 124.416 0.084 124.44 ;
    END
  END b[140]
  PIN b[141]
    DIRECTION OUTPUT ;
    USE SIGNAL ;
    PORT
      LAYER M4 ;
        RECT  0 124.56 0.084 124.584 ;
    END
  END b[141]
  PIN b[142]
    DIRECTION OUTPUT ;
    USE SIGNAL ;
    PORT
      LAYER M4 ;
        RECT  0 124.704 0.084 124.728 ;
    END
  END b[142]
  PIN b[143]
    DIRECTION OUTPUT ;
    USE SIGNAL ;
    PORT
      LAYER M4 ;
        RECT  0 124.848 0.084 124.872 ;
    END
  END b[143]
  PIN b[144]
    DIRECTION OUTPUT ;
    USE SIGNAL ;
    PORT
      LAYER M4 ;
        RECT  0 124.992 0.084 125.016 ;
    END
  END b[144]
  PIN b[145]
    DIRECTION OUTPUT ;
    USE SIGNAL ;
    PORT
      LAYER M4 ;
        RECT  0 125.136 0.084 125.16 ;
    END
  END b[145]
  PIN b[146]
    DIRECTION OUTPUT ;
    USE SIGNAL ;
    PORT
      LAYER M4 ;
        RECT  0 125.28 0.084 125.304 ;
    END
  END b[146]
  PIN b[147]
    DIRECTION OUTPUT ;
    USE SIGNAL ;
    PORT
      LAYER M4 ;
        RECT  0 125.424 0.084 125.448 ;
    END
  END b[147]
  PIN b[148]
    DIRECTION OUTPUT ;
    USE SIGNAL ;
    PORT
      LAYER M4 ;
        RECT  0 125.568 0.084 125.592 ;
    END
  END b[148]
  PIN b[149]
    DIRECTION OUTPUT ;
    USE SIGNAL ;
    PORT
      LAYER M4 ;
        RECT  0 125.712 0.084 125.736 ;
    END
  END b[149]
  PIN b[14]
    DIRECTION OUTPUT ;
    USE SIGNAL ;
    PORT
      LAYER M4 ;
        RECT  0 33.696 0.084 33.72 ;
    END
  END b[14]
  PIN b[150]
    DIRECTION OUTPUT ;
    USE SIGNAL ;
    PORT
      LAYER M4 ;
        RECT  0 125.856 0.084 125.88 ;
    END
  END b[150]
  PIN b[151]
    DIRECTION OUTPUT ;
    USE SIGNAL ;
    PORT
      LAYER M4 ;
        RECT  0 126 0.084 126.024 ;
    END
  END b[151]
  PIN b[152]
    DIRECTION OUTPUT ;
    USE SIGNAL ;
    PORT
      LAYER M4 ;
        RECT  0 126.144 0.084 126.168 ;
    END
  END b[152]
  PIN b[153]
    DIRECTION OUTPUT ;
    USE SIGNAL ;
    PORT
      LAYER M4 ;
        RECT  0 126.288 0.084 126.312 ;
    END
  END b[153]
  PIN b[154]
    DIRECTION OUTPUT ;
    USE SIGNAL ;
    PORT
      LAYER M4 ;
        RECT  0 126.432 0.084 126.456 ;
    END
  END b[154]
  PIN b[155]
    DIRECTION OUTPUT ;
    USE SIGNAL ;
    PORT
      LAYER M4 ;
        RECT  0 126.576 0.084 126.6 ;
    END
  END b[155]
  PIN b[156]
    DIRECTION OUTPUT ;
    USE SIGNAL ;
    PORT
      LAYER M4 ;
        RECT  0 126.72 0.084 126.744 ;
    END
  END b[156]
  PIN b[157]
    DIRECTION OUTPUT ;
    USE SIGNAL ;
    PORT
      LAYER M4 ;
        RECT  0 126.864 0.084 126.888 ;
    END
  END b[157]
  PIN b[158]
    DIRECTION OUTPUT ;
    USE SIGNAL ;
    PORT
      LAYER M4 ;
        RECT  0 127.008 0.084 127.032 ;
    END
  END b[158]
  PIN b[159]
    DIRECTION OUTPUT ;
    USE SIGNAL ;
    PORT
      LAYER M4 ;
        RECT  0 127.152 0.084 127.176 ;
    END
  END b[159]
  PIN b[15]
    DIRECTION OUTPUT ;
    USE SIGNAL ;
    PORT
      LAYER M4 ;
        RECT  0 33.84 0.084 33.864 ;
    END
  END b[15]
  PIN b[160]
    DIRECTION OUTPUT ;
    USE SIGNAL ;
    PORT
      LAYER M4 ;
        RECT  0 130.032 0.084 130.056 ;
    END
  END b[160]
  PIN b[161]
    DIRECTION OUTPUT ;
    USE SIGNAL ;
    PORT
      LAYER M4 ;
        RECT  0 130.176 0.084 130.2 ;
    END
  END b[161]
  PIN b[162]
    DIRECTION OUTPUT ;
    USE SIGNAL ;
    PORT
      LAYER M4 ;
        RECT  0 130.32 0.084 130.344 ;
    END
  END b[162]
  PIN b[163]
    DIRECTION OUTPUT ;
    USE SIGNAL ;
    PORT
      LAYER M4 ;
        RECT  0 130.464 0.084 130.488 ;
    END
  END b[163]
  PIN b[164]
    DIRECTION OUTPUT ;
    USE SIGNAL ;
    PORT
      LAYER M4 ;
        RECT  0 130.608 0.084 130.632 ;
    END
  END b[164]
  PIN b[165]
    DIRECTION OUTPUT ;
    USE SIGNAL ;
    PORT
      LAYER M4 ;
        RECT  0 130.752 0.084 130.776 ;
    END
  END b[165]
  PIN b[166]
    DIRECTION OUTPUT ;
    USE SIGNAL ;
    PORT
      LAYER M4 ;
        RECT  0 130.896 0.084 130.92 ;
    END
  END b[166]
  PIN b[167]
    DIRECTION OUTPUT ;
    USE SIGNAL ;
    PORT
      LAYER M4 ;
        RECT  0 131.04 0.084 131.064 ;
    END
  END b[167]
  PIN b[168]
    DIRECTION OUTPUT ;
    USE SIGNAL ;
    PORT
      LAYER M4 ;
        RECT  0 131.184 0.084 131.208 ;
    END
  END b[168]
  PIN b[169]
    DIRECTION OUTPUT ;
    USE SIGNAL ;
    PORT
      LAYER M4 ;
        RECT  0 131.328 0.084 131.352 ;
    END
  END b[169]
  PIN b[16]
    DIRECTION OUTPUT ;
    USE SIGNAL ;
    PORT
      LAYER M4 ;
        RECT  0 33.984 0.084 34.008 ;
    END
  END b[16]
  PIN b[170]
    DIRECTION OUTPUT ;
    USE SIGNAL ;
    PORT
      LAYER M4 ;
        RECT  0 131.472 0.084 131.496 ;
    END
  END b[170]
  PIN b[171]
    DIRECTION OUTPUT ;
    USE SIGNAL ;
    PORT
      LAYER M4 ;
        RECT  0 131.616 0.084 131.64 ;
    END
  END b[171]
  PIN b[172]
    DIRECTION OUTPUT ;
    USE SIGNAL ;
    PORT
      LAYER M4 ;
        RECT  0 131.76 0.084 131.784 ;
    END
  END b[172]
  PIN b[17]
    DIRECTION OUTPUT ;
    USE SIGNAL ;
    PORT
      LAYER M4 ;
        RECT  0 34.128 0.084 34.152 ;
    END
  END b[17]
  PIN b[18]
    DIRECTION OUTPUT ;
    USE SIGNAL ;
    PORT
      LAYER M4 ;
        RECT  0 34.272 0.084 34.296 ;
    END
  END b[18]
  PIN b[19]
    DIRECTION OUTPUT ;
    USE SIGNAL ;
    PORT
      LAYER M4 ;
        RECT  0 34.416 0.084 34.44 ;
    END
  END b[19]
  PIN b[1]
    DIRECTION OUTPUT ;
    USE SIGNAL ;
    PORT
      LAYER M4 ;
        RECT  0 31.824 0.084 31.848 ;
    END
  END b[1]
  PIN b[20]
    DIRECTION OUTPUT ;
    USE SIGNAL ;
    PORT
      LAYER M4 ;
        RECT  0 34.56 0.084 34.584 ;
    END
  END b[20]
  PIN b[21]
    DIRECTION OUTPUT ;
    USE SIGNAL ;
    PORT
      LAYER M4 ;
        RECT  0 34.704 0.084 34.728 ;
    END
  END b[21]
  PIN b[22]
    DIRECTION OUTPUT ;
    USE SIGNAL ;
    PORT
      LAYER M4 ;
        RECT  0 34.848 0.084 34.872 ;
    END
  END b[22]
  PIN b[23]
    DIRECTION OUTPUT ;
    USE SIGNAL ;
    PORT
      LAYER M4 ;
        RECT  0 34.992 0.084 35.016 ;
    END
  END b[23]
  PIN b[24]
    DIRECTION OUTPUT ;
    USE SIGNAL ;
    PORT
      LAYER M4 ;
        RECT  0 35.136 0.084 35.16 ;
    END
  END b[24]
  PIN b[25]
    DIRECTION OUTPUT ;
    USE SIGNAL ;
    PORT
      LAYER M4 ;
        RECT  0 35.28 0.084 35.304 ;
    END
  END b[25]
  PIN b[26]
    DIRECTION OUTPUT ;
    USE SIGNAL ;
    PORT
      LAYER M4 ;
        RECT  0 35.424 0.084 35.448 ;
    END
  END b[26]
  PIN b[27]
    DIRECTION OUTPUT ;
    USE SIGNAL ;
    PORT
      LAYER M4 ;
        RECT  0 35.568 0.084 35.592 ;
    END
  END b[27]
  PIN b[28]
    DIRECTION OUTPUT ;
    USE SIGNAL ;
    PORT
      LAYER M4 ;
        RECT  0 35.712 0.084 35.736 ;
    END
  END b[28]
  PIN b[29]
    DIRECTION OUTPUT ;
    USE SIGNAL ;
    PORT
      LAYER M4 ;
        RECT  0 35.856 0.084 35.88 ;
    END
  END b[29]
  PIN b[2]
    DIRECTION OUTPUT ;
    USE SIGNAL ;
    PORT
      LAYER M4 ;
        RECT  0 31.968 0.084 31.992 ;
    END
  END b[2]
  PIN b[30]
    DIRECTION OUTPUT ;
    USE SIGNAL ;
    PORT
      LAYER M4 ;
        RECT  0 36 0.084 36.024 ;
    END
  END b[30]
  PIN b[31]
    DIRECTION OUTPUT ;
    USE SIGNAL ;
    PORT
      LAYER M4 ;
        RECT  0 36.144 0.084 36.168 ;
    END
  END b[31]
  PIN b[32]
    DIRECTION OUTPUT ;
    USE SIGNAL ;
    PORT
      LAYER M4 ;
        RECT  0 40.896 0.084 40.92 ;
    END
  END b[32]
  PIN b[33]
    DIRECTION OUTPUT ;
    USE SIGNAL ;
    PORT
      LAYER M4 ;
        RECT  0 41.04 0.084 41.064 ;
    END
  END b[33]
  PIN b[34]
    DIRECTION OUTPUT ;
    USE SIGNAL ;
    PORT
      LAYER M4 ;
        RECT  0 41.184 0.084 41.208 ;
    END
  END b[34]
  PIN b[35]
    DIRECTION OUTPUT ;
    USE SIGNAL ;
    PORT
      LAYER M4 ;
        RECT  0 41.328 0.084 41.352 ;
    END
  END b[35]
  PIN b[36]
    DIRECTION OUTPUT ;
    USE SIGNAL ;
    PORT
      LAYER M4 ;
        RECT  0 41.472 0.084 41.496 ;
    END
  END b[36]
  PIN b[37]
    DIRECTION OUTPUT ;
    USE SIGNAL ;
    PORT
      LAYER M4 ;
        RECT  0 41.616 0.084 41.64 ;
    END
  END b[37]
  PIN b[38]
    DIRECTION OUTPUT ;
    USE SIGNAL ;
    PORT
      LAYER M4 ;
        RECT  0 41.76 0.084 41.784 ;
    END
  END b[38]
  PIN b[39]
    DIRECTION OUTPUT ;
    USE SIGNAL ;
    PORT
      LAYER M4 ;
        RECT  0 41.904 0.084 41.928 ;
    END
  END b[39]
  PIN b[3]
    DIRECTION OUTPUT ;
    USE SIGNAL ;
    PORT
      LAYER M4 ;
        RECT  0 32.112 0.084 32.136 ;
    END
  END b[3]
  PIN b[40]
    DIRECTION OUTPUT ;
    USE SIGNAL ;
    PORT
      LAYER M4 ;
        RECT  0 42.048 0.084 42.072 ;
    END
  END b[40]
  PIN b[41]
    DIRECTION OUTPUT ;
    USE SIGNAL ;
    PORT
      LAYER M4 ;
        RECT  0 42.192 0.084 42.216 ;
    END
  END b[41]
  PIN b[42]
    DIRECTION OUTPUT ;
    USE SIGNAL ;
    PORT
      LAYER M4 ;
        RECT  0 42.336 0.084 42.36 ;
    END
  END b[42]
  PIN b[43]
    DIRECTION OUTPUT ;
    USE SIGNAL ;
    PORT
      LAYER M4 ;
        RECT  0 42.48 0.084 42.504 ;
    END
  END b[43]
  PIN b[44]
    DIRECTION OUTPUT ;
    USE SIGNAL ;
    PORT
      LAYER M4 ;
        RECT  0 42.624 0.084 42.648 ;
    END
  END b[44]
  PIN b[45]
    DIRECTION OUTPUT ;
    USE SIGNAL ;
    PORT
      LAYER M4 ;
        RECT  0 42.768 0.084 42.792 ;
    END
  END b[45]
  PIN b[46]
    DIRECTION OUTPUT ;
    USE SIGNAL ;
    PORT
      LAYER M4 ;
        RECT  0 42.912 0.084 42.936 ;
    END
  END b[46]
  PIN b[47]
    DIRECTION OUTPUT ;
    USE SIGNAL ;
    PORT
      LAYER M4 ;
        RECT  0 43.056 0.084 43.08 ;
    END
  END b[47]
  PIN b[48]
    DIRECTION OUTPUT ;
    USE SIGNAL ;
    PORT
      LAYER M4 ;
        RECT  0 43.2 0.084 43.224 ;
    END
  END b[48]
  PIN b[49]
    DIRECTION OUTPUT ;
    USE SIGNAL ;
    PORT
      LAYER M4 ;
        RECT  0 43.344 0.084 43.368 ;
    END
  END b[49]
  PIN b[4]
    DIRECTION OUTPUT ;
    USE SIGNAL ;
    PORT
      LAYER M4 ;
        RECT  0 32.256 0.084 32.28 ;
    END
  END b[4]
  PIN b[50]
    DIRECTION OUTPUT ;
    USE SIGNAL ;
    PORT
      LAYER M4 ;
        RECT  0 43.488 0.084 43.512 ;
    END
  END b[50]
  PIN b[51]
    DIRECTION OUTPUT ;
    USE SIGNAL ;
    PORT
      LAYER M4 ;
        RECT  0 43.632 0.084 43.656 ;
    END
  END b[51]
  PIN b[52]
    DIRECTION OUTPUT ;
    USE SIGNAL ;
    PORT
      LAYER M4 ;
        RECT  0 43.776 0.084 43.8 ;
    END
  END b[52]
  PIN b[53]
    DIRECTION OUTPUT ;
    USE SIGNAL ;
    PORT
      LAYER M4 ;
        RECT  0 43.92 0.084 43.944 ;
    END
  END b[53]
  PIN b[54]
    DIRECTION OUTPUT ;
    USE SIGNAL ;
    PORT
      LAYER M4 ;
        RECT  0 44.064 0.084 44.088 ;
    END
  END b[54]
  PIN b[55]
    DIRECTION OUTPUT ;
    USE SIGNAL ;
    PORT
      LAYER M4 ;
        RECT  0 44.208 0.084 44.232 ;
    END
  END b[55]
  PIN b[56]
    DIRECTION OUTPUT ;
    USE SIGNAL ;
    PORT
      LAYER M4 ;
        RECT  0 44.352 0.084 44.376 ;
    END
  END b[56]
  PIN b[57]
    DIRECTION OUTPUT ;
    USE SIGNAL ;
    PORT
      LAYER M4 ;
        RECT  0 44.496 0.084 44.52 ;
    END
  END b[57]
  PIN b[58]
    DIRECTION OUTPUT ;
    USE SIGNAL ;
    PORT
      LAYER M4 ;
        RECT  0 44.64 0.084 44.664 ;
    END
  END b[58]
  PIN b[59]
    DIRECTION OUTPUT ;
    USE SIGNAL ;
    PORT
      LAYER M4 ;
        RECT  0 44.784 0.084 44.808 ;
    END
  END b[59]
  PIN b[5]
    DIRECTION OUTPUT ;
    USE SIGNAL ;
    PORT
      LAYER M4 ;
        RECT  0 32.4 0.084 32.424 ;
    END
  END b[5]
  PIN b[60]
    DIRECTION OUTPUT ;
    USE SIGNAL ;
    PORT
      LAYER M4 ;
        RECT  0 44.928 0.084 44.952 ;
    END
  END b[60]
  PIN b[61]
    DIRECTION OUTPUT ;
    USE SIGNAL ;
    PORT
      LAYER M4 ;
        RECT  0 45.072 0.084 45.096 ;
    END
  END b[61]
  PIN b[62]
    DIRECTION OUTPUT ;
    USE SIGNAL ;
    PORT
      LAYER M4 ;
        RECT  0 45.216 0.084 45.24 ;
    END
  END b[62]
  PIN b[63]
    DIRECTION OUTPUT ;
    USE SIGNAL ;
    PORT
      LAYER M4 ;
        RECT  0 45.36 0.084 45.384 ;
    END
  END b[63]
  PIN b[64]
    DIRECTION OUTPUT ;
    USE SIGNAL ;
    PORT
      LAYER M4 ;
        RECT  0 78.912 0.084 78.936 ;
    END
  END b[64]
  PIN b[65]
    DIRECTION OUTPUT ;
    USE SIGNAL ;
    PORT
      LAYER M4 ;
        RECT  0 79.056 0.084 79.08 ;
    END
  END b[65]
  PIN b[66]
    DIRECTION OUTPUT ;
    USE SIGNAL ;
    PORT
      LAYER M4 ;
        RECT  0 79.2 0.084 79.224 ;
    END
  END b[66]
  PIN b[67]
    DIRECTION OUTPUT ;
    USE SIGNAL ;
    PORT
      LAYER M4 ;
        RECT  0 79.344 0.084 79.368 ;
    END
  END b[67]
  PIN b[68]
    DIRECTION OUTPUT ;
    USE SIGNAL ;
    PORT
      LAYER M4 ;
        RECT  0 79.488 0.084 79.512 ;
    END
  END b[68]
  PIN b[69]
    DIRECTION OUTPUT ;
    USE SIGNAL ;
    PORT
      LAYER M4 ;
        RECT  0 79.632 0.084 79.656 ;
    END
  END b[69]
  PIN b[6]
    DIRECTION OUTPUT ;
    USE SIGNAL ;
    PORT
      LAYER M4 ;
        RECT  0 32.544 0.084 32.568 ;
    END
  END b[6]
  PIN b[70]
    DIRECTION OUTPUT ;
    USE SIGNAL ;
    PORT
      LAYER M4 ;
        RECT  0 79.776 0.084 79.8 ;
    END
  END b[70]
  PIN b[71]
    DIRECTION OUTPUT ;
    USE SIGNAL ;
    PORT
      LAYER M4 ;
        RECT  0 79.92 0.084 79.944 ;
    END
  END b[71]
  PIN b[72]
    DIRECTION OUTPUT ;
    USE SIGNAL ;
    PORT
      LAYER M4 ;
        RECT  0 80.064 0.084 80.088 ;
    END
  END b[72]
  PIN b[73]
    DIRECTION OUTPUT ;
    USE SIGNAL ;
    PORT
      LAYER M4 ;
        RECT  0 80.208 0.084 80.232 ;
    END
  END b[73]
  PIN b[74]
    DIRECTION OUTPUT ;
    USE SIGNAL ;
    PORT
      LAYER M4 ;
        RECT  0 80.352 0.084 80.376 ;
    END
  END b[74]
  PIN b[75]
    DIRECTION OUTPUT ;
    USE SIGNAL ;
    PORT
      LAYER M4 ;
        RECT  0 80.496 0.084 80.52 ;
    END
  END b[75]
  PIN b[76]
    DIRECTION OUTPUT ;
    USE SIGNAL ;
    PORT
      LAYER M4 ;
        RECT  0 80.64 0.084 80.664 ;
    END
  END b[76]
  PIN b[77]
    DIRECTION OUTPUT ;
    USE SIGNAL ;
    PORT
      LAYER M4 ;
        RECT  0 80.784 0.084 80.808 ;
    END
  END b[77]
  PIN b[78]
    DIRECTION OUTPUT ;
    USE SIGNAL ;
    PORT
      LAYER M4 ;
        RECT  0 80.928 0.084 80.952 ;
    END
  END b[78]
  PIN b[79]
    DIRECTION OUTPUT ;
    USE SIGNAL ;
    PORT
      LAYER M4 ;
        RECT  0 81.072 0.084 81.096 ;
    END
  END b[79]
  PIN b[7]
    DIRECTION OUTPUT ;
    USE SIGNAL ;
    PORT
      LAYER M4 ;
        RECT  0 32.688 0.084 32.712 ;
    END
  END b[7]
  PIN b[80]
    DIRECTION OUTPUT ;
    USE SIGNAL ;
    PORT
      LAYER M4 ;
        RECT  0 81.216 0.084 81.24 ;
    END
  END b[80]
  PIN b[81]
    DIRECTION OUTPUT ;
    USE SIGNAL ;
    PORT
      LAYER M4 ;
        RECT  0 81.36 0.084 81.384 ;
    END
  END b[81]
  PIN b[82]
    DIRECTION OUTPUT ;
    USE SIGNAL ;
    PORT
      LAYER M4 ;
        RECT  0 81.504 0.084 81.528 ;
    END
  END b[82]
  PIN b[83]
    DIRECTION OUTPUT ;
    USE SIGNAL ;
    PORT
      LAYER M4 ;
        RECT  0 81.648 0.084 81.672 ;
    END
  END b[83]
  PIN b[84]
    DIRECTION OUTPUT ;
    USE SIGNAL ;
    PORT
      LAYER M4 ;
        RECT  0 81.792 0.084 81.816 ;
    END
  END b[84]
  PIN b[85]
    DIRECTION OUTPUT ;
    USE SIGNAL ;
    PORT
      LAYER M4 ;
        RECT  0 81.936 0.084 81.96 ;
    END
  END b[85]
  PIN b[86]
    DIRECTION OUTPUT ;
    USE SIGNAL ;
    PORT
      LAYER M4 ;
        RECT  0 82.08 0.084 82.104 ;
    END
  END b[86]
  PIN b[87]
    DIRECTION OUTPUT ;
    USE SIGNAL ;
    PORT
      LAYER M4 ;
        RECT  0 82.224 0.084 82.248 ;
    END
  END b[87]
  PIN b[88]
    DIRECTION OUTPUT ;
    USE SIGNAL ;
    PORT
      LAYER M4 ;
        RECT  0 82.368 0.084 82.392 ;
    END
  END b[88]
  PIN b[89]
    DIRECTION OUTPUT ;
    USE SIGNAL ;
    PORT
      LAYER M4 ;
        RECT  0 82.512 0.084 82.536 ;
    END
  END b[89]
  PIN b[8]
    DIRECTION OUTPUT ;
    USE SIGNAL ;
    PORT
      LAYER M4 ;
        RECT  0 32.832 0.084 32.856 ;
    END
  END b[8]
  PIN b[90]
    DIRECTION OUTPUT ;
    USE SIGNAL ;
    PORT
      LAYER M4 ;
        RECT  0 82.656 0.084 82.68 ;
    END
  END b[90]
  PIN b[91]
    DIRECTION OUTPUT ;
    USE SIGNAL ;
    PORT
      LAYER M4 ;
        RECT  0 82.8 0.084 82.824 ;
    END
  END b[91]
  PIN b[92]
    DIRECTION OUTPUT ;
    USE SIGNAL ;
    PORT
      LAYER M4 ;
        RECT  0 82.944 0.084 82.968 ;
    END
  END b[92]
  PIN b[93]
    DIRECTION OUTPUT ;
    USE SIGNAL ;
    PORT
      LAYER M4 ;
        RECT  0 83.088 0.084 83.112 ;
    END
  END b[93]
  PIN b[94]
    DIRECTION OUTPUT ;
    USE SIGNAL ;
    PORT
      LAYER M4 ;
        RECT  0 83.232 0.084 83.256 ;
    END
  END b[94]
  PIN b[95]
    DIRECTION OUTPUT ;
    USE SIGNAL ;
    PORT
      LAYER M4 ;
        RECT  0 83.376 0.084 83.4 ;
    END
  END b[95]
  PIN b[96]
    DIRECTION OUTPUT ;
    USE SIGNAL ;
    PORT
      LAYER M4 ;
        RECT  0 84.672 0.084 84.696 ;
    END
  END b[96]
  PIN b[97]
    DIRECTION OUTPUT ;
    USE SIGNAL ;
    PORT
      LAYER M4 ;
        RECT  0 84.816 0.084 84.84 ;
    END
  END b[97]
  PIN b[98]
    DIRECTION OUTPUT ;
    USE SIGNAL ;
    PORT
      LAYER M4 ;
        RECT  0 84.96 0.084 84.984 ;
    END
  END b[98]
  PIN b[99]
    DIRECTION OUTPUT ;
    USE SIGNAL ;
    PORT
      LAYER M4 ;
        RECT  0 85.104 0.084 85.128 ;
    END
  END b[99]
  PIN b[9]
    DIRECTION OUTPUT ;
    USE SIGNAL ;
    PORT
      LAYER M4 ;
        RECT  0 32.976 0.084 33 ;
    END
  END b[9]
  PIN ck
    DIRECTION INPUT ;
    USE SIGNAL ;
    PORT
      LAYER M3 ;
        RECT  37.908 170.603 37.926 170.64 ;
    END
  END ck
  PIN ck_s
    DIRECTION INPUT ;
    USE SIGNAL ;
    PORT
      LAYER M3 ;
        RECT  38.016 170.603 38.034 170.64 ;
    END
  END ck_s
  PIN en
    DIRECTION INPUT ;
    USE SIGNAL ;
    PORT
      LAYER M3 ;
        RECT  38.124 170.603 38.142 170.64 ;
    END
  END en
  PIN fault
    DIRECTION OUTPUT ;
    USE SIGNAL ;
    PORT
      LAYER M3 ;
        RECT  38.232 170.603 38.25 170.64 ;
    END
  END fault
  PIN k0
    DIRECTION INPUT ;
    USE SIGNAL ;
    PORT
      LAYER M3 ;
        RECT  38.34 170.603 38.358 170.64 ;
    END
  END k0
  PIN k1
    DIRECTION INPUT ;
    USE SIGNAL ;
    PORT
      LAYER M3 ;
        RECT  38.448 170.603 38.466 170.64 ;
    END
  END k1
  PIN k2
    DIRECTION INPUT ;
    USE SIGNAL ;
    PORT
      LAYER M3 ;
        RECT  38.556 170.603 38.574 170.64 ;
    END
  END k2
  PIN k3
    DIRECTION INPUT ;
    USE SIGNAL ;
    PORT
      LAYER M3 ;
        RECT  38.664 170.603 38.682 170.64 ;
    END
  END k3
  PIN rs
    DIRECTION INPUT ;
    USE SIGNAL ;
    PORT
      LAYER M3 ;
        RECT  38.772 170.603 38.79 170.64 ;
    END
  END rs
  PIN tie_hi
    DIRECTION OUTPUT ;
    USE SIGNAL ;
    PORT
      LAYER M3 ;
        RECT  38.88 170.603 38.898 170.64 ;
    END
  END tie_hi
  PIN tie_lo
    DIRECTION OUTPUT ;
    USE SIGNAL ;
    PORT
      LAYER M3 ;
        RECT  38.988 170.603 39.006 170.64 ;
    END
  END tie_lo
  PIN VDD
    DIRECTION INOUT ;
    USE POWER ;
    PORT
      LAYER M5 ;
        RECT  94.392 2.151 94.512 168.489 ;
        RECT  91.692 2.151 91.812 168.489 ;
        RECT  88.992 2.151 89.112 168.489 ;
        RECT  86.292 2.151 86.412 168.489 ;
        RECT  83.592 2.151 83.712 168.489 ;
        RECT  80.892 2.151 81.012 168.489 ;
        RECT  78.192 2.151 78.312 168.489 ;
        RECT  75.492 2.151 75.612 168.489 ;
        RECT  72.792 2.151 72.912 168.489 ;
        RECT  70.092 2.151 70.212 168.489 ;
        RECT  67.392 2.151 67.512 168.489 ;
        RECT  64.692 2.151 64.812 168.489 ;
        RECT  61.992 2.151 62.112 168.489 ;
        RECT  59.292 2.151 59.412 168.489 ;
        RECT  56.592 2.151 56.712 168.489 ;
        RECT  53.892 2.151 54.012 168.489 ;
        RECT  51.192 2.151 51.312 168.489 ;
        RECT  48.492 2.151 48.612 168.489 ;
        RECT  45.792 2.151 45.912 168.489 ;
        RECT  43.092 2.151 43.212 168.489 ;
        RECT  40.392 2.151 40.512 168.489 ;
        RECT  37.692 2.151 37.812 168.489 ;
        RECT  34.992 2.151 35.112 168.489 ;
        RECT  32.292 2.151 32.412 168.489 ;
        RECT  29.592 2.151 29.712 168.489 ;
        RECT  26.892 2.151 27.012 168.489 ;
        RECT  24.192 2.151 24.312 168.489 ;
        RECT  21.492 2.151 21.612 168.489 ;
        RECT  18.792 2.151 18.912 168.489 ;
        RECT  16.092 2.151 16.212 168.489 ;
        RECT  13.392 2.151 13.512 168.489 ;
        RECT  10.692 2.151 10.812 168.489 ;
        RECT  7.992 2.151 8.112 168.489 ;
        RECT  5.292 2.151 5.412 168.489 ;
        RECT  2.592 2.151 2.712 168.489 ;
    END
  END VDD
  PIN VSS
    DIRECTION INOUT ;
    USE GROUND ;
    PORT
      LAYER M5 ;
        RECT  94.2 2.137 94.32 168.503 ;
        RECT  91.5 2.137 91.62 168.503 ;
        RECT  88.8 2.137 88.92 168.503 ;
        RECT  86.1 2.137 86.22 168.503 ;
        RECT  83.4 2.137 83.52 168.503 ;
        RECT  80.7 2.137 80.82 168.503 ;
        RECT  78 2.137 78.12 168.503 ;
        RECT  75.3 2.137 75.42 168.503 ;
        RECT  72.6 2.137 72.72 168.503 ;
        RECT  69.9 2.137 70.02 168.503 ;
        RECT  67.2 2.137 67.32 168.503 ;
        RECT  64.5 2.137 64.62 168.503 ;
        RECT  61.8 2.137 61.92 168.503 ;
        RECT  59.1 2.137 59.22 168.503 ;
        RECT  56.4 2.137 56.52 168.503 ;
        RECT  53.7 2.137 53.82 168.503 ;
        RECT  51 2.137 51.12 168.503 ;
        RECT  48.3 2.137 48.42 168.503 ;
        RECT  45.6 2.137 45.72 168.503 ;
        RECT  42.9 2.137 43.02 168.503 ;
        RECT  40.2 2.137 40.32 168.503 ;
        RECT  37.5 2.137 37.62 168.503 ;
        RECT  34.8 2.137 34.92 168.503 ;
        RECT  32.1 2.137 32.22 168.503 ;
        RECT  29.4 2.137 29.52 168.503 ;
        RECT  26.7 2.137 26.82 168.503 ;
        RECT  24 2.137 24.12 168.503 ;
        RECT  21.3 2.137 21.42 168.503 ;
        RECT  18.6 2.137 18.72 168.503 ;
        RECT  15.9 2.137 16.02 168.503 ;
        RECT  13.2 2.137 13.32 168.503 ;
        RECT  10.5 2.137 10.62 168.503 ;
        RECT  7.8 2.137 7.92 168.503 ;
        RECT  5.1 2.137 5.22 168.503 ;
        RECT  2.4 2.137 2.52 168.503 ;
    END
  END VSS
  OBS
    LAYER RVTN ;
     RECT  2.16 2.16 96.12 2.295 ;
     RECT  2.16 2.565 96.12 2.835 ;
     RECT  2.16 3.105 96.12 3.375 ;
     RECT  2.16 3.645 96.12 3.915 ;
     RECT  2.16 4.185 96.12 4.455 ;
     RECT  2.16 4.725 96.12 4.995 ;
     RECT  2.16 5.265 96.12 5.535 ;
     RECT  2.16 5.805 96.12 6.075 ;
     RECT  2.16 6.345 96.12 6.615 ;
     RECT  2.16 6.885 96.12 7.155 ;
     RECT  2.16 7.425 96.12 7.695 ;
     RECT  2.16 7.965 96.12 8.235 ;
     RECT  2.16 8.505 96.12 8.775 ;
     RECT  2.16 9.045 96.12 9.315 ;
     RECT  2.16 9.585 96.12 9.855 ;
     RECT  2.16 10.125 96.12 10.395 ;
     RECT  2.16 10.665 96.12 10.935 ;
     RECT  2.16 11.205 96.12 11.475 ;
     RECT  2.16 11.745 96.12 12.015 ;
     RECT  2.16 12.285 96.12 12.555 ;
     RECT  2.16 12.825 96.12 13.095 ;
     RECT  2.16 13.365 96.12 13.635 ;
     RECT  2.16 13.905 96.12 14.175 ;
     RECT  2.16 14.445 96.12 14.715 ;
     RECT  2.16 14.985 96.12 15.255 ;
     RECT  2.16 15.525 96.12 15.795 ;
     RECT  2.16 16.065 96.12 16.335 ;
     RECT  2.16 16.605 96.12 16.875 ;
     RECT  2.16 17.145 96.12 17.415 ;
     RECT  2.16 17.685 96.12 17.955 ;
     RECT  2.16 18.225 96.12 18.495 ;
     RECT  2.16 18.765 96.12 19.035 ;
     RECT  2.16 19.305 96.12 19.575 ;
     RECT  2.16 19.845 96.12 20.115 ;
     RECT  2.16 20.385 96.12 20.655 ;
     RECT  2.16 20.925 96.12 21.195 ;
     RECT  2.16 21.465 96.12 21.735 ;
     RECT  2.16 22.005 96.12 22.275 ;
     RECT  2.16 22.545 96.12 22.815 ;
     RECT  2.16 23.085 96.12 23.355 ;
     RECT  2.16 23.625 96.12 23.895 ;
     RECT  2.16 24.165 96.12 24.435 ;
     RECT  2.16 24.705 96.12 24.975 ;
     RECT  2.16 25.245 96.12 25.515 ;
     RECT  2.16 25.785 96.12 26.055 ;
     RECT  2.16 26.325 96.12 26.595 ;
     RECT  2.16 26.865 96.12 27.135 ;
     RECT  2.16 27.405 96.12 27.675 ;
     RECT  2.16 27.945 96.12 28.215 ;
     RECT  2.16 28.485 96.12 28.755 ;
     RECT  2.16 29.025 96.12 29.295 ;
     RECT  2.16 29.565 96.12 29.835 ;
     RECT  2.16 30.105 96.12 30.375 ;
     RECT  2.16 30.645 96.12 30.915 ;
     RECT  2.16 31.185 96.12 31.455 ;
     RECT  2.16 31.725 96.12 31.995 ;
     RECT  2.16 32.265 96.12 32.535 ;
     RECT  2.16 32.805 96.12 33.075 ;
     RECT  2.16 33.345 96.12 33.615 ;
     RECT  2.16 33.885 96.12 34.155 ;
     RECT  2.16 34.425 96.12 34.695 ;
     RECT  2.16 34.965 96.12 35.235 ;
     RECT  2.16 35.505 96.12 35.775 ;
     RECT  2.16 36.045 96.12 36.315 ;
     RECT  2.16 36.585 96.12 36.855 ;
     RECT  2.16 37.125 96.12 37.395 ;
     RECT  2.16 37.665 96.12 37.935 ;
     RECT  2.16 38.205 96.12 38.475 ;
     RECT  2.16 38.745 96.12 39.015 ;
     RECT  2.16 39.285 96.12 39.555 ;
     RECT  2.16 39.825 96.12 40.095 ;
     RECT  2.16 40.365 96.12 40.635 ;
     RECT  2.16 40.905 96.12 41.04 ;
     RECT  2.16 41.04 41.148 41.175 ;
     RECT  77.22 41.04 96.12 41.175 ;
     RECT  2.16 41.445 41.148 41.715 ;
     RECT  77.22 41.445 96.12 41.715 ;
     RECT  2.16 41.985 41.148 42.255 ;
     RECT  77.22 41.985 96.12 42.255 ;
     RECT  2.16 42.525 41.148 42.795 ;
     RECT  77.22 42.525 96.12 42.795 ;
     RECT  2.16 43.065 41.148 43.335 ;
     RECT  77.22 43.065 96.12 43.335 ;
     RECT  2.16 43.605 41.148 43.875 ;
     RECT  77.22 43.605 96.12 43.875 ;
     RECT  2.16 44.145 41.148 44.415 ;
     RECT  77.22 44.145 96.12 44.415 ;
     RECT  2.16 44.685 41.148 44.955 ;
     RECT  77.22 44.685 96.12 44.955 ;
     RECT  2.16 45.225 41.148 45.495 ;
     RECT  77.22 45.225 96.12 45.495 ;
     RECT  2.16 45.765 41.148 46.035 ;
     RECT  77.22 45.765 96.12 46.035 ;
     RECT  2.16 46.305 41.148 46.575 ;
     RECT  77.22 46.305 96.12 46.575 ;
     RECT  2.16 46.845 41.148 47.115 ;
     RECT  77.22 46.845 96.12 47.115 ;
     RECT  2.16 47.385 41.148 47.655 ;
     RECT  77.22 47.385 96.12 47.655 ;
     RECT  2.16 47.925 41.148 48.195 ;
     RECT  77.22 47.925 96.12 48.195 ;
     RECT  2.16 48.465 41.148 48.735 ;
     RECT  77.22 48.465 96.12 48.735 ;
     RECT  2.16 49.005 41.148 49.275 ;
     RECT  77.22 49.005 96.12 49.275 ;
     RECT  2.16 49.545 41.148 49.815 ;
     RECT  77.22 49.545 96.12 49.815 ;
     RECT  2.16 50.085 41.148 50.355 ;
     RECT  77.22 50.085 96.12 50.355 ;
     RECT  2.16 50.625 41.148 50.895 ;
     RECT  77.22 50.625 96.12 50.895 ;
     RECT  2.16 51.165 41.148 51.435 ;
     RECT  77.22 51.165 96.12 51.435 ;
     RECT  2.16 51.705 41.148 51.975 ;
     RECT  77.22 51.705 96.12 51.975 ;
     RECT  2.16 52.245 41.148 52.515 ;
     RECT  77.22 52.245 96.12 52.515 ;
     RECT  2.16 52.785 41.148 53.055 ;
     RECT  77.22 52.785 96.12 53.055 ;
     RECT  2.16 53.325 41.148 53.595 ;
     RECT  77.22 53.325 96.12 53.595 ;
     RECT  2.16 53.865 41.148 54.135 ;
     RECT  77.22 53.865 96.12 54.135 ;
     RECT  2.16 54.405 41.148 54.675 ;
     RECT  77.22 54.405 96.12 54.675 ;
     RECT  2.16 54.945 41.148 55.215 ;
     RECT  77.22 54.945 96.12 55.215 ;
     RECT  2.16 55.485 41.148 55.755 ;
     RECT  77.22 55.485 96.12 55.755 ;
     RECT  2.16 56.025 41.148 56.295 ;
     RECT  77.22 56.025 96.12 56.295 ;
     RECT  2.16 56.565 41.148 56.835 ;
     RECT  77.22 56.565 96.12 56.835 ;
     RECT  2.16 57.105 41.148 57.375 ;
     RECT  77.22 57.105 96.12 57.375 ;
     RECT  2.16 57.645 41.148 57.915 ;
     RECT  77.22 57.645 96.12 57.915 ;
     RECT  2.16 58.185 41.148 58.455 ;
     RECT  77.22 58.185 96.12 58.455 ;
     RECT  2.16 58.725 41.148 58.995 ;
     RECT  77.22 58.725 96.12 58.995 ;
     RECT  2.16 59.265 41.148 59.535 ;
     RECT  77.22 59.265 96.12 59.535 ;
     RECT  2.16 59.805 41.148 60.075 ;
     RECT  77.22 59.805 96.12 60.075 ;
     RECT  2.16 60.345 41.148 60.615 ;
     RECT  77.22 60.345 96.12 60.615 ;
     RECT  2.16 60.885 41.148 61.155 ;
     RECT  77.22 60.885 96.12 61.155 ;
     RECT  2.16 61.425 41.148 61.695 ;
     RECT  77.22 61.425 96.12 61.695 ;
     RECT  2.16 61.965 41.148 62.235 ;
     RECT  77.22 61.965 96.12 62.235 ;
     RECT  2.16 62.505 41.148 62.64 ;
     RECT  77.22 62.505 96.12 62.64 ;
     RECT  2.16 62.64 96.12 62.775 ;
     RECT  2.16 63.045 96.12 63.315 ;
     RECT  2.16 63.585 96.12 63.855 ;
     RECT  2.16 64.125 96.12 64.395 ;
     RECT  2.16 64.665 96.12 64.935 ;
     RECT  2.16 65.205 96.12 65.475 ;
     RECT  2.16 65.745 96.12 66.015 ;
     RECT  2.16 66.285 96.12 66.555 ;
     RECT  2.16 66.825 96.12 67.095 ;
     RECT  2.16 67.365 96.12 67.635 ;
     RECT  2.16 67.905 96.12 68.175 ;
     RECT  2.16 68.445 96.12 68.715 ;
     RECT  2.16 68.985 96.12 69.255 ;
     RECT  2.16 69.525 96.12 69.795 ;
     RECT  2.16 70.065 96.12 70.335 ;
     RECT  2.16 70.605 96.12 70.875 ;
     RECT  2.16 71.145 96.12 71.415 ;
     RECT  2.16 71.685 96.12 71.955 ;
     RECT  2.16 72.225 96.12 72.495 ;
     RECT  2.16 72.765 96.12 73.035 ;
     RECT  2.16 73.305 96.12 73.575 ;
     RECT  2.16 73.845 96.12 74.115 ;
     RECT  2.16 74.385 96.12 74.655 ;
     RECT  2.16 74.925 96.12 75.195 ;
     RECT  2.16 75.465 96.12 75.735 ;
     RECT  2.16 76.005 96.12 76.275 ;
     RECT  2.16 76.545 96.12 76.815 ;
     RECT  2.16 77.085 96.12 77.355 ;
     RECT  2.16 77.625 96.12 77.895 ;
     RECT  2.16 78.165 96.12 78.435 ;
     RECT  2.16 78.705 96.12 78.975 ;
     RECT  2.16 79.245 96.12 79.515 ;
     RECT  2.16 79.785 96.12 80.055 ;
     RECT  2.16 80.325 96.12 80.595 ;
     RECT  2.16 80.865 96.12 81.135 ;
     RECT  2.16 81.405 96.12 81.675 ;
     RECT  2.16 81.945 96.12 82.215 ;
     RECT  2.16 82.485 96.12 82.755 ;
     RECT  2.16 83.025 96.12 83.295 ;
     RECT  2.16 83.565 96.12 83.835 ;
     RECT  2.16 84.105 96.12 84.24 ;
     RECT  2.16 84.24 41.148 84.375 ;
     RECT  77.22 84.24 96.12 84.375 ;
     RECT  2.16 84.645 41.148 84.915 ;
     RECT  77.22 84.645 96.12 84.915 ;
     RECT  2.16 85.185 41.148 85.455 ;
     RECT  77.22 85.185 96.12 85.455 ;
     RECT  2.16 85.725 41.148 85.995 ;
     RECT  77.22 85.725 96.12 85.995 ;
     RECT  2.16 86.265 41.148 86.535 ;
     RECT  77.22 86.265 96.12 86.535 ;
     RECT  2.16 86.805 41.148 87.075 ;
     RECT  77.22 86.805 96.12 87.075 ;
     RECT  2.16 87.345 41.148 87.615 ;
     RECT  77.22 87.345 96.12 87.615 ;
     RECT  2.16 87.885 41.148 88.155 ;
     RECT  77.22 87.885 96.12 88.155 ;
     RECT  2.16 88.425 41.148 88.695 ;
     RECT  77.22 88.425 96.12 88.695 ;
     RECT  2.16 88.965 41.148 89.235 ;
     RECT  77.22 88.965 96.12 89.235 ;
     RECT  2.16 89.505 41.148 89.775 ;
     RECT  77.22 89.505 96.12 89.775 ;
     RECT  2.16 90.045 41.148 90.315 ;
     RECT  77.22 90.045 96.12 90.315 ;
     RECT  2.16 90.585 41.148 90.855 ;
     RECT  77.22 90.585 96.12 90.855 ;
     RECT  2.16 91.125 41.148 91.395 ;
     RECT  77.22 91.125 96.12 91.395 ;
     RECT  2.16 91.665 41.148 91.935 ;
     RECT  77.22 91.665 96.12 91.935 ;
     RECT  2.16 92.205 41.148 92.475 ;
     RECT  77.22 92.205 96.12 92.475 ;
     RECT  2.16 92.745 41.148 93.015 ;
     RECT  77.22 92.745 96.12 93.015 ;
     RECT  2.16 93.285 41.148 93.555 ;
     RECT  77.22 93.285 96.12 93.555 ;
     RECT  2.16 93.825 41.148 94.095 ;
     RECT  77.22 93.825 96.12 94.095 ;
     RECT  2.16 94.365 41.148 94.635 ;
     RECT  77.22 94.365 96.12 94.635 ;
     RECT  2.16 94.905 41.148 95.175 ;
     RECT  77.22 94.905 96.12 95.175 ;
     RECT  2.16 95.445 41.148 95.715 ;
     RECT  77.22 95.445 96.12 95.715 ;
     RECT  2.16 95.985 41.148 96.255 ;
     RECT  77.22 95.985 96.12 96.255 ;
     RECT  2.16 96.525 41.148 96.795 ;
     RECT  77.22 96.525 96.12 96.795 ;
     RECT  2.16 97.065 41.148 97.335 ;
     RECT  77.22 97.065 96.12 97.335 ;
     RECT  2.16 97.605 41.148 97.875 ;
     RECT  77.22 97.605 96.12 97.875 ;
     RECT  2.16 98.145 41.148 98.415 ;
     RECT  77.22 98.145 96.12 98.415 ;
     RECT  2.16 98.685 41.148 98.955 ;
     RECT  77.22 98.685 96.12 98.955 ;
     RECT  2.16 99.225 41.148 99.495 ;
     RECT  77.22 99.225 96.12 99.495 ;
     RECT  2.16 99.765 41.148 100.035 ;
     RECT  77.22 99.765 96.12 100.035 ;
     RECT  2.16 100.305 41.148 100.575 ;
     RECT  77.22 100.305 96.12 100.575 ;
     RECT  2.16 100.845 41.148 101.115 ;
     RECT  77.22 100.845 96.12 101.115 ;
     RECT  2.16 101.385 41.148 101.655 ;
     RECT  77.22 101.385 96.12 101.655 ;
     RECT  2.16 101.925 41.148 102.195 ;
     RECT  77.22 101.925 96.12 102.195 ;
     RECT  2.16 102.465 41.148 102.735 ;
     RECT  77.22 102.465 96.12 102.735 ;
     RECT  2.16 103.005 41.148 103.275 ;
     RECT  77.22 103.005 96.12 103.275 ;
     RECT  2.16 103.545 41.148 103.815 ;
     RECT  77.22 103.545 96.12 103.815 ;
     RECT  2.16 104.085 41.148 104.355 ;
     RECT  77.22 104.085 96.12 104.355 ;
     RECT  2.16 104.625 41.148 104.895 ;
     RECT  77.22 104.625 96.12 104.895 ;
     RECT  2.16 105.165 41.148 105.435 ;
     RECT  77.22 105.165 96.12 105.435 ;
     RECT  2.16 105.705 41.148 105.84 ;
     RECT  77.22 105.705 96.12 105.84 ;
     RECT  2.16 105.84 96.12 105.975 ;
     RECT  2.16 106.245 96.12 106.515 ;
     RECT  2.16 106.785 96.12 107.055 ;
     RECT  2.16 107.325 96.12 107.595 ;
     RECT  2.16 107.865 96.12 108.135 ;
     RECT  2.16 108.405 96.12 108.675 ;
     RECT  2.16 108.945 96.12 109.215 ;
     RECT  2.16 109.485 96.12 109.755 ;
     RECT  2.16 110.025 96.12 110.295 ;
     RECT  2.16 110.565 96.12 110.835 ;
     RECT  2.16 111.105 96.12 111.375 ;
     RECT  2.16 111.645 96.12 111.915 ;
     RECT  2.16 112.185 96.12 112.455 ;
     RECT  2.16 112.725 96.12 112.995 ;
     RECT  2.16 113.265 96.12 113.535 ;
     RECT  2.16 113.805 96.12 114.075 ;
     RECT  2.16 114.345 96.12 114.615 ;
     RECT  2.16 114.885 96.12 115.155 ;
     RECT  2.16 115.425 96.12 115.695 ;
     RECT  2.16 115.965 96.12 116.235 ;
     RECT  2.16 116.505 96.12 116.775 ;
     RECT  2.16 117.045 96.12 117.315 ;
     RECT  2.16 117.585 96.12 117.855 ;
     RECT  2.16 118.125 96.12 118.395 ;
     RECT  2.16 118.665 96.12 118.935 ;
     RECT  2.16 119.205 96.12 119.475 ;
     RECT  2.16 119.745 96.12 120.015 ;
     RECT  2.16 120.285 96.12 120.555 ;
     RECT  2.16 120.825 96.12 121.095 ;
     RECT  2.16 121.365 96.12 121.635 ;
     RECT  2.16 121.905 96.12 122.175 ;
     RECT  2.16 122.445 96.12 122.715 ;
     RECT  2.16 122.985 96.12 123.255 ;
     RECT  2.16 123.525 96.12 123.795 ;
     RECT  2.16 124.065 96.12 124.335 ;
     RECT  2.16 124.605 96.12 124.875 ;
     RECT  2.16 125.145 96.12 125.415 ;
     RECT  2.16 125.685 96.12 125.955 ;
     RECT  2.16 126.225 96.12 126.495 ;
     RECT  2.16 126.765 96.12 127.035 ;
     RECT  2.16 127.305 96.12 127.44 ;
     RECT  2.16 127.44 41.148 127.575 ;
     RECT  77.22 127.44 96.12 127.575 ;
     RECT  2.16 127.845 41.148 128.115 ;
     RECT  77.22 127.845 96.12 128.115 ;
     RECT  2.16 128.385 41.148 128.655 ;
     RECT  77.22 128.385 96.12 128.655 ;
     RECT  2.16 128.925 41.148 129.195 ;
     RECT  77.22 128.925 96.12 129.195 ;
     RECT  2.16 129.465 41.148 129.735 ;
     RECT  77.22 129.465 96.12 129.735 ;
     RECT  2.16 130.005 41.148 130.275 ;
     RECT  77.22 130.005 96.12 130.275 ;
     RECT  2.16 130.545 41.148 130.815 ;
     RECT  77.22 130.545 96.12 130.815 ;
     RECT  2.16 131.085 41.148 131.355 ;
     RECT  77.22 131.085 96.12 131.355 ;
     RECT  2.16 131.625 41.148 131.895 ;
     RECT  77.22 131.625 96.12 131.895 ;
     RECT  2.16 132.165 41.148 132.435 ;
     RECT  77.22 132.165 96.12 132.435 ;
     RECT  2.16 132.705 41.148 132.975 ;
     RECT  77.22 132.705 96.12 132.975 ;
     RECT  2.16 133.245 41.148 133.515 ;
     RECT  77.22 133.245 96.12 133.515 ;
     RECT  2.16 133.785 41.148 134.055 ;
     RECT  77.22 133.785 96.12 134.055 ;
     RECT  2.16 134.325 41.148 134.595 ;
     RECT  77.22 134.325 96.12 134.595 ;
     RECT  2.16 134.865 41.148 135.135 ;
     RECT  77.22 134.865 96.12 135.135 ;
     RECT  2.16 135.405 41.148 135.675 ;
     RECT  77.22 135.405 96.12 135.675 ;
     RECT  2.16 135.945 41.148 136.215 ;
     RECT  77.22 135.945 96.12 136.215 ;
     RECT  2.16 136.485 41.148 136.755 ;
     RECT  77.22 136.485 96.12 136.755 ;
     RECT  2.16 137.025 41.148 137.295 ;
     RECT  77.22 137.025 96.12 137.295 ;
     RECT  2.16 137.565 41.148 137.835 ;
     RECT  77.22 137.565 96.12 137.835 ;
     RECT  2.16 138.105 41.148 138.375 ;
     RECT  77.22 138.105 96.12 138.375 ;
     RECT  2.16 138.645 41.148 138.915 ;
     RECT  77.22 138.645 96.12 138.915 ;
     RECT  2.16 139.185 41.148 139.455 ;
     RECT  77.22 139.185 96.12 139.455 ;
     RECT  2.16 139.725 41.148 139.995 ;
     RECT  77.22 139.725 96.12 139.995 ;
     RECT  2.16 140.265 41.148 140.535 ;
     RECT  77.22 140.265 96.12 140.535 ;
     RECT  2.16 140.805 41.148 141.075 ;
     RECT  77.22 140.805 96.12 141.075 ;
     RECT  2.16 141.345 41.148 141.615 ;
     RECT  77.22 141.345 96.12 141.615 ;
     RECT  2.16 141.885 41.148 142.155 ;
     RECT  77.22 141.885 96.12 142.155 ;
     RECT  2.16 142.425 41.148 142.695 ;
     RECT  77.22 142.425 96.12 142.695 ;
     RECT  2.16 142.965 41.148 143.235 ;
     RECT  77.22 142.965 96.12 143.235 ;
     RECT  2.16 143.505 41.148 143.775 ;
     RECT  77.22 143.505 96.12 143.775 ;
     RECT  2.16 144.045 41.148 144.315 ;
     RECT  77.22 144.045 96.12 144.315 ;
     RECT  2.16 144.585 41.148 144.855 ;
     RECT  77.22 144.585 96.12 144.855 ;
     RECT  2.16 145.125 41.148 145.395 ;
     RECT  77.22 145.125 96.12 145.395 ;
     RECT  2.16 145.665 41.148 145.935 ;
     RECT  77.22 145.665 96.12 145.935 ;
     RECT  2.16 146.205 41.148 146.475 ;
     RECT  77.22 146.205 96.12 146.475 ;
     RECT  2.16 146.745 41.148 147.015 ;
     RECT  77.22 146.745 96.12 147.015 ;
     RECT  2.16 147.285 41.148 147.555 ;
     RECT  77.22 147.285 96.12 147.555 ;
     RECT  2.16 147.825 41.148 148.095 ;
     RECT  77.22 147.825 96.12 148.095 ;
     RECT  2.16 148.365 41.148 148.635 ;
     RECT  77.22 148.365 96.12 148.635 ;
     RECT  2.16 148.905 41.148 149.04 ;
     RECT  77.22 148.905 96.12 149.04 ;
     RECT  2.16 149.04 96.12 149.175 ;
     RECT  2.16 149.445 96.12 149.715 ;
     RECT  2.16 149.985 96.12 150.255 ;
     RECT  2.16 150.525 96.12 150.795 ;
     RECT  2.16 151.065 96.12 151.335 ;
     RECT  2.16 151.605 96.12 151.875 ;
     RECT  2.16 152.145 96.12 152.415 ;
     RECT  2.16 152.685 96.12 152.955 ;
     RECT  2.16 153.225 96.12 153.495 ;
     RECT  2.16 153.765 96.12 154.035 ;
     RECT  2.16 154.305 96.12 154.575 ;
     RECT  2.16 154.845 96.12 155.115 ;
     RECT  2.16 155.385 96.12 155.655 ;
     RECT  2.16 155.925 96.12 156.195 ;
     RECT  2.16 156.465 96.12 156.735 ;
     RECT  2.16 157.005 96.12 157.275 ;
     RECT  2.16 157.545 96.12 157.815 ;
     RECT  2.16 158.085 96.12 158.355 ;
     RECT  2.16 158.625 96.12 158.895 ;
     RECT  2.16 159.165 96.12 159.435 ;
     RECT  2.16 159.705 96.12 159.975 ;
     RECT  2.16 160.245 96.12 160.515 ;
     RECT  2.16 160.785 96.12 161.055 ;
     RECT  2.16 161.325 96.12 161.595 ;
     RECT  2.16 161.865 96.12 162.135 ;
     RECT  2.16 162.405 96.12 162.675 ;
     RECT  2.16 162.945 96.12 163.215 ;
     RECT  2.16 163.485 96.12 163.755 ;
     RECT  2.16 164.025 96.12 164.295 ;
     RECT  2.16 164.565 96.12 164.835 ;
     RECT  2.16 165.105 96.12 165.375 ;
     RECT  2.16 165.645 96.12 165.915 ;
     RECT  2.16 166.185 96.12 166.455 ;
     RECT  2.16 166.725 96.12 166.995 ;
     RECT  2.16 167.265 96.12 167.535 ;
     RECT  2.16 167.805 96.12 168.075 ;
     RECT  2.16 168.345 96.12 168.48 ;
    LAYER RVTP ;
     RECT  2.16 2.295 96.12 2.565 ;
     RECT  2.16 2.835 96.12 3.105 ;
     RECT  2.16 3.375 96.12 3.645 ;
     RECT  2.16 3.915 96.12 4.185 ;
     RECT  2.16 4.455 96.12 4.725 ;
     RECT  2.16 4.995 96.12 5.265 ;
     RECT  2.16 5.535 96.12 5.805 ;
     RECT  2.16 6.075 96.12 6.345 ;
     RECT  2.16 6.615 96.12 6.885 ;
     RECT  2.16 7.155 96.12 7.425 ;
     RECT  2.16 7.695 96.12 7.965 ;
     RECT  2.16 8.235 96.12 8.505 ;
     RECT  2.16 8.775 96.12 9.045 ;
     RECT  2.16 9.315 96.12 9.585 ;
     RECT  2.16 9.855 96.12 10.125 ;
     RECT  2.16 10.395 96.12 10.665 ;
     RECT  2.16 10.935 96.12 11.205 ;
     RECT  2.16 11.475 96.12 11.745 ;
     RECT  2.16 12.015 96.12 12.285 ;
     RECT  2.16 12.555 96.12 12.825 ;
     RECT  2.16 13.095 96.12 13.365 ;
     RECT  2.16 13.635 96.12 13.905 ;
     RECT  2.16 14.175 96.12 14.445 ;
     RECT  2.16 14.715 96.12 14.985 ;
     RECT  2.16 15.255 96.12 15.525 ;
     RECT  2.16 15.795 96.12 16.065 ;
     RECT  2.16 16.335 96.12 16.605 ;
     RECT  2.16 16.875 96.12 17.145 ;
     RECT  2.16 17.415 96.12 17.685 ;
     RECT  2.16 17.955 96.12 18.225 ;
     RECT  2.16 18.495 96.12 18.765 ;
     RECT  2.16 19.035 96.12 19.305 ;
     RECT  2.16 19.575 96.12 19.845 ;
     RECT  2.16 20.115 96.12 20.385 ;
     RECT  2.16 20.655 96.12 20.925 ;
     RECT  2.16 21.195 96.12 21.465 ;
     RECT  2.16 21.735 96.12 22.005 ;
     RECT  2.16 22.275 96.12 22.545 ;
     RECT  2.16 22.815 96.12 23.085 ;
     RECT  2.16 23.355 96.12 23.625 ;
     RECT  2.16 23.895 96.12 24.165 ;
     RECT  2.16 24.435 96.12 24.705 ;
     RECT  2.16 24.975 96.12 25.245 ;
     RECT  2.16 25.515 96.12 25.785 ;
     RECT  2.16 26.055 96.12 26.325 ;
     RECT  2.16 26.595 96.12 26.865 ;
     RECT  2.16 27.135 96.12 27.405 ;
     RECT  2.16 27.675 96.12 27.945 ;
     RECT  2.16 28.215 96.12 28.485 ;
     RECT  2.16 28.755 96.12 29.025 ;
     RECT  2.16 29.295 96.12 29.565 ;
     RECT  2.16 29.835 96.12 30.105 ;
     RECT  2.16 30.375 96.12 30.645 ;
     RECT  2.16 30.915 96.12 31.185 ;
     RECT  2.16 31.455 96.12 31.725 ;
     RECT  2.16 31.995 96.12 32.265 ;
     RECT  2.16 32.535 96.12 32.805 ;
     RECT  2.16 33.075 96.12 33.345 ;
     RECT  2.16 33.615 96.12 33.885 ;
     RECT  2.16 34.155 96.12 34.425 ;
     RECT  2.16 34.695 96.12 34.965 ;
     RECT  2.16 35.235 96.12 35.505 ;
     RECT  2.16 35.775 96.12 36.045 ;
     RECT  2.16 36.315 96.12 36.585 ;
     RECT  2.16 36.855 96.12 37.125 ;
     RECT  2.16 37.395 96.12 37.665 ;
     RECT  2.16 37.935 96.12 38.205 ;
     RECT  2.16 38.475 96.12 38.745 ;
     RECT  2.16 39.015 96.12 39.285 ;
     RECT  2.16 39.555 96.12 39.825 ;
     RECT  2.16 40.095 96.12 40.365 ;
     RECT  2.16 40.635 96.12 40.905 ;
     RECT  2.16 41.175 41.148 41.445 ;
     RECT  77.22 41.175 96.12 41.445 ;
     RECT  2.16 41.715 41.148 41.985 ;
     RECT  77.22 41.715 96.12 41.985 ;
     RECT  2.16 42.255 41.148 42.525 ;
     RECT  77.22 42.255 96.12 42.525 ;
     RECT  2.16 42.795 41.148 43.065 ;
     RECT  77.22 42.795 96.12 43.065 ;
     RECT  2.16 43.335 41.148 43.605 ;
     RECT  77.22 43.335 96.12 43.605 ;
     RECT  2.16 43.875 41.148 44.145 ;
     RECT  77.22 43.875 96.12 44.145 ;
     RECT  2.16 44.415 41.148 44.685 ;
     RECT  77.22 44.415 96.12 44.685 ;
     RECT  2.16 44.955 41.148 45.225 ;
     RECT  77.22 44.955 96.12 45.225 ;
     RECT  2.16 45.495 41.148 45.765 ;
     RECT  77.22 45.495 96.12 45.765 ;
     RECT  2.16 46.035 41.148 46.305 ;
     RECT  77.22 46.035 96.12 46.305 ;
     RECT  2.16 46.575 41.148 46.845 ;
     RECT  77.22 46.575 96.12 46.845 ;
     RECT  2.16 47.115 41.148 47.385 ;
     RECT  77.22 47.115 96.12 47.385 ;
     RECT  2.16 47.655 41.148 47.925 ;
     RECT  77.22 47.655 96.12 47.925 ;
     RECT  2.16 48.195 41.148 48.465 ;
     RECT  77.22 48.195 96.12 48.465 ;
     RECT  2.16 48.735 41.148 49.005 ;
     RECT  77.22 48.735 96.12 49.005 ;
     RECT  2.16 49.275 41.148 49.545 ;
     RECT  77.22 49.275 96.12 49.545 ;
     RECT  2.16 49.815 41.148 50.085 ;
     RECT  77.22 49.815 96.12 50.085 ;
     RECT  2.16 50.355 41.148 50.625 ;
     RECT  77.22 50.355 96.12 50.625 ;
     RECT  2.16 50.895 41.148 51.165 ;
     RECT  77.22 50.895 96.12 51.165 ;
     RECT  2.16 51.435 41.148 51.705 ;
     RECT  77.22 51.435 96.12 51.705 ;
     RECT  2.16 51.975 41.148 52.245 ;
     RECT  77.22 51.975 96.12 52.245 ;
     RECT  2.16 52.515 41.148 52.785 ;
     RECT  77.22 52.515 96.12 52.785 ;
     RECT  2.16 53.055 41.148 53.325 ;
     RECT  77.22 53.055 96.12 53.325 ;
     RECT  2.16 53.595 41.148 53.865 ;
     RECT  77.22 53.595 96.12 53.865 ;
     RECT  2.16 54.135 41.148 54.405 ;
     RECT  77.22 54.135 96.12 54.405 ;
     RECT  2.16 54.675 41.148 54.945 ;
     RECT  77.22 54.675 96.12 54.945 ;
     RECT  2.16 55.215 41.148 55.485 ;
     RECT  77.22 55.215 96.12 55.485 ;
     RECT  2.16 55.755 41.148 56.025 ;
     RECT  77.22 55.755 96.12 56.025 ;
     RECT  2.16 56.295 41.148 56.565 ;
     RECT  77.22 56.295 96.12 56.565 ;
     RECT  2.16 56.835 41.148 57.105 ;
     RECT  77.22 56.835 96.12 57.105 ;
     RECT  2.16 57.375 41.148 57.645 ;
     RECT  77.22 57.375 96.12 57.645 ;
     RECT  2.16 57.915 41.148 58.185 ;
     RECT  77.22 57.915 96.12 58.185 ;
     RECT  2.16 58.455 41.148 58.725 ;
     RECT  77.22 58.455 96.12 58.725 ;
     RECT  2.16 58.995 41.148 59.265 ;
     RECT  77.22 58.995 96.12 59.265 ;
     RECT  2.16 59.535 41.148 59.805 ;
     RECT  77.22 59.535 96.12 59.805 ;
     RECT  2.16 60.075 41.148 60.345 ;
     RECT  77.22 60.075 96.12 60.345 ;
     RECT  2.16 60.615 41.148 60.885 ;
     RECT  77.22 60.615 96.12 60.885 ;
     RECT  2.16 61.155 41.148 61.425 ;
     RECT  77.22 61.155 96.12 61.425 ;
     RECT  2.16 61.695 41.148 61.965 ;
     RECT  77.22 61.695 96.12 61.965 ;
     RECT  2.16 62.235 41.148 62.505 ;
     RECT  77.22 62.235 96.12 62.505 ;
     RECT  2.16 62.775 96.12 63.045 ;
     RECT  2.16 63.315 96.12 63.585 ;
     RECT  2.16 63.855 96.12 64.125 ;
     RECT  2.16 64.395 96.12 64.665 ;
     RECT  2.16 64.935 96.12 65.205 ;
     RECT  2.16 65.475 96.12 65.745 ;
     RECT  2.16 66.015 96.12 66.285 ;
     RECT  2.16 66.555 96.12 66.825 ;
     RECT  2.16 67.095 96.12 67.365 ;
     RECT  2.16 67.635 96.12 67.905 ;
     RECT  2.16 68.175 96.12 68.445 ;
     RECT  2.16 68.715 96.12 68.985 ;
     RECT  2.16 69.255 96.12 69.525 ;
     RECT  2.16 69.795 96.12 70.065 ;
     RECT  2.16 70.335 96.12 70.605 ;
     RECT  2.16 70.875 96.12 71.145 ;
     RECT  2.16 71.415 96.12 71.685 ;
     RECT  2.16 71.955 96.12 72.225 ;
     RECT  2.16 72.495 96.12 72.765 ;
     RECT  2.16 73.035 96.12 73.305 ;
     RECT  2.16 73.575 96.12 73.845 ;
     RECT  2.16 74.115 96.12 74.385 ;
     RECT  2.16 74.655 96.12 74.925 ;
     RECT  2.16 75.195 96.12 75.465 ;
     RECT  2.16 75.735 96.12 76.005 ;
     RECT  2.16 76.275 96.12 76.545 ;
     RECT  2.16 76.815 96.12 77.085 ;
     RECT  2.16 77.355 96.12 77.625 ;
     RECT  2.16 77.895 96.12 78.165 ;
     RECT  2.16 78.435 96.12 78.705 ;
     RECT  2.16 78.975 96.12 79.245 ;
     RECT  2.16 79.515 96.12 79.785 ;
     RECT  2.16 80.055 96.12 80.325 ;
     RECT  2.16 80.595 96.12 80.865 ;
     RECT  2.16 81.135 96.12 81.405 ;
     RECT  2.16 81.675 96.12 81.945 ;
     RECT  2.16 82.215 96.12 82.485 ;
     RECT  2.16 82.755 96.12 83.025 ;
     RECT  2.16 83.295 96.12 83.565 ;
     RECT  2.16 83.835 96.12 84.105 ;
     RECT  2.16 84.375 41.148 84.645 ;
     RECT  77.22 84.375 96.12 84.645 ;
     RECT  2.16 84.915 41.148 85.185 ;
     RECT  77.22 84.915 96.12 85.185 ;
     RECT  2.16 85.455 41.148 85.725 ;
     RECT  77.22 85.455 96.12 85.725 ;
     RECT  2.16 85.995 41.148 86.265 ;
     RECT  77.22 85.995 96.12 86.265 ;
     RECT  2.16 86.535 41.148 86.805 ;
     RECT  77.22 86.535 96.12 86.805 ;
     RECT  2.16 87.075 41.148 87.345 ;
     RECT  77.22 87.075 96.12 87.345 ;
     RECT  2.16 87.615 41.148 87.885 ;
     RECT  77.22 87.615 96.12 87.885 ;
     RECT  2.16 88.155 41.148 88.425 ;
     RECT  77.22 88.155 96.12 88.425 ;
     RECT  2.16 88.695 41.148 88.965 ;
     RECT  77.22 88.695 96.12 88.965 ;
     RECT  2.16 89.235 41.148 89.505 ;
     RECT  77.22 89.235 96.12 89.505 ;
     RECT  2.16 89.775 41.148 90.045 ;
     RECT  77.22 89.775 96.12 90.045 ;
     RECT  2.16 90.315 41.148 90.585 ;
     RECT  77.22 90.315 96.12 90.585 ;
     RECT  2.16 90.855 41.148 91.125 ;
     RECT  77.22 90.855 96.12 91.125 ;
     RECT  2.16 91.395 41.148 91.665 ;
     RECT  77.22 91.395 96.12 91.665 ;
     RECT  2.16 91.935 41.148 92.205 ;
     RECT  77.22 91.935 96.12 92.205 ;
     RECT  2.16 92.475 41.148 92.745 ;
     RECT  77.22 92.475 96.12 92.745 ;
     RECT  2.16 93.015 41.148 93.285 ;
     RECT  77.22 93.015 96.12 93.285 ;
     RECT  2.16 93.555 41.148 93.825 ;
     RECT  77.22 93.555 96.12 93.825 ;
     RECT  2.16 94.095 41.148 94.365 ;
     RECT  77.22 94.095 96.12 94.365 ;
     RECT  2.16 94.635 41.148 94.905 ;
     RECT  77.22 94.635 96.12 94.905 ;
     RECT  2.16 95.175 41.148 95.445 ;
     RECT  77.22 95.175 96.12 95.445 ;
     RECT  2.16 95.715 41.148 95.985 ;
     RECT  77.22 95.715 96.12 95.985 ;
     RECT  2.16 96.255 41.148 96.525 ;
     RECT  77.22 96.255 96.12 96.525 ;
     RECT  2.16 96.795 41.148 97.065 ;
     RECT  77.22 96.795 96.12 97.065 ;
     RECT  2.16 97.335 41.148 97.605 ;
     RECT  77.22 97.335 96.12 97.605 ;
     RECT  2.16 97.875 41.148 98.145 ;
     RECT  77.22 97.875 96.12 98.145 ;
     RECT  2.16 98.415 41.148 98.685 ;
     RECT  77.22 98.415 96.12 98.685 ;
     RECT  2.16 98.955 41.148 99.225 ;
     RECT  77.22 98.955 96.12 99.225 ;
     RECT  2.16 99.495 41.148 99.765 ;
     RECT  77.22 99.495 96.12 99.765 ;
     RECT  2.16 100.035 41.148 100.305 ;
     RECT  77.22 100.035 96.12 100.305 ;
     RECT  2.16 100.575 41.148 100.845 ;
     RECT  77.22 100.575 96.12 100.845 ;
     RECT  2.16 101.115 41.148 101.385 ;
     RECT  77.22 101.115 96.12 101.385 ;
     RECT  2.16 101.655 41.148 101.925 ;
     RECT  77.22 101.655 96.12 101.925 ;
     RECT  2.16 102.195 41.148 102.465 ;
     RECT  77.22 102.195 96.12 102.465 ;
     RECT  2.16 102.735 41.148 103.005 ;
     RECT  77.22 102.735 96.12 103.005 ;
     RECT  2.16 103.275 41.148 103.545 ;
     RECT  77.22 103.275 96.12 103.545 ;
     RECT  2.16 103.815 41.148 104.085 ;
     RECT  77.22 103.815 96.12 104.085 ;
     RECT  2.16 104.355 41.148 104.625 ;
     RECT  77.22 104.355 96.12 104.625 ;
     RECT  2.16 104.895 41.148 105.165 ;
     RECT  77.22 104.895 96.12 105.165 ;
     RECT  2.16 105.435 41.148 105.705 ;
     RECT  77.22 105.435 96.12 105.705 ;
     RECT  2.16 105.975 96.12 106.245 ;
     RECT  2.16 106.515 96.12 106.785 ;
     RECT  2.16 107.055 96.12 107.325 ;
     RECT  2.16 107.595 96.12 107.865 ;
     RECT  2.16 108.135 96.12 108.405 ;
     RECT  2.16 108.675 96.12 108.945 ;
     RECT  2.16 109.215 96.12 109.485 ;
     RECT  2.16 109.755 96.12 110.025 ;
     RECT  2.16 110.295 96.12 110.565 ;
     RECT  2.16 110.835 96.12 111.105 ;
     RECT  2.16 111.375 96.12 111.645 ;
     RECT  2.16 111.915 96.12 112.185 ;
     RECT  2.16 112.455 96.12 112.725 ;
     RECT  2.16 112.995 96.12 113.265 ;
     RECT  2.16 113.535 96.12 113.805 ;
     RECT  2.16 114.075 96.12 114.345 ;
     RECT  2.16 114.615 96.12 114.885 ;
     RECT  2.16 115.155 96.12 115.425 ;
     RECT  2.16 115.695 96.12 115.965 ;
     RECT  2.16 116.235 96.12 116.505 ;
     RECT  2.16 116.775 96.12 117.045 ;
     RECT  2.16 117.315 96.12 117.585 ;
     RECT  2.16 117.855 96.12 118.125 ;
     RECT  2.16 118.395 96.12 118.665 ;
     RECT  2.16 118.935 96.12 119.205 ;
     RECT  2.16 119.475 96.12 119.745 ;
     RECT  2.16 120.015 96.12 120.285 ;
     RECT  2.16 120.555 96.12 120.825 ;
     RECT  2.16 121.095 96.12 121.365 ;
     RECT  2.16 121.635 96.12 121.905 ;
     RECT  2.16 122.175 96.12 122.445 ;
     RECT  2.16 122.715 96.12 122.985 ;
     RECT  2.16 123.255 96.12 123.525 ;
     RECT  2.16 123.795 96.12 124.065 ;
     RECT  2.16 124.335 96.12 124.605 ;
     RECT  2.16 124.875 96.12 125.145 ;
     RECT  2.16 125.415 96.12 125.685 ;
     RECT  2.16 125.955 96.12 126.225 ;
     RECT  2.16 126.495 96.12 126.765 ;
     RECT  2.16 127.035 96.12 127.305 ;
     RECT  2.16 127.575 41.148 127.845 ;
     RECT  77.22 127.575 96.12 127.845 ;
     RECT  2.16 128.115 41.148 128.385 ;
     RECT  77.22 128.115 96.12 128.385 ;
     RECT  2.16 128.655 41.148 128.925 ;
     RECT  77.22 128.655 96.12 128.925 ;
     RECT  2.16 129.195 41.148 129.465 ;
     RECT  77.22 129.195 96.12 129.465 ;
     RECT  2.16 129.735 41.148 130.005 ;
     RECT  77.22 129.735 96.12 130.005 ;
     RECT  2.16 130.275 41.148 130.545 ;
     RECT  77.22 130.275 96.12 130.545 ;
     RECT  2.16 130.815 41.148 131.085 ;
     RECT  77.22 130.815 96.12 131.085 ;
     RECT  2.16 131.355 41.148 131.625 ;
     RECT  77.22 131.355 96.12 131.625 ;
     RECT  2.16 131.895 41.148 132.165 ;
     RECT  77.22 131.895 96.12 132.165 ;
     RECT  2.16 132.435 41.148 132.705 ;
     RECT  77.22 132.435 96.12 132.705 ;
     RECT  2.16 132.975 41.148 133.245 ;
     RECT  77.22 132.975 96.12 133.245 ;
     RECT  2.16 133.515 41.148 133.785 ;
     RECT  77.22 133.515 96.12 133.785 ;
     RECT  2.16 134.055 41.148 134.325 ;
     RECT  77.22 134.055 96.12 134.325 ;
     RECT  2.16 134.595 41.148 134.865 ;
     RECT  77.22 134.595 96.12 134.865 ;
     RECT  2.16 135.135 41.148 135.405 ;
     RECT  77.22 135.135 96.12 135.405 ;
     RECT  2.16 135.675 41.148 135.945 ;
     RECT  77.22 135.675 96.12 135.945 ;
     RECT  2.16 136.215 41.148 136.485 ;
     RECT  77.22 136.215 96.12 136.485 ;
     RECT  2.16 136.755 41.148 137.025 ;
     RECT  77.22 136.755 96.12 137.025 ;
     RECT  2.16 137.295 41.148 137.565 ;
     RECT  77.22 137.295 96.12 137.565 ;
     RECT  2.16 137.835 41.148 138.105 ;
     RECT  77.22 137.835 96.12 138.105 ;
     RECT  2.16 138.375 41.148 138.645 ;
     RECT  77.22 138.375 96.12 138.645 ;
     RECT  2.16 138.915 41.148 139.185 ;
     RECT  77.22 138.915 96.12 139.185 ;
     RECT  2.16 139.455 41.148 139.725 ;
     RECT  77.22 139.455 96.12 139.725 ;
     RECT  2.16 139.995 41.148 140.265 ;
     RECT  77.22 139.995 96.12 140.265 ;
     RECT  2.16 140.535 41.148 140.805 ;
     RECT  77.22 140.535 96.12 140.805 ;
     RECT  2.16 141.075 41.148 141.345 ;
     RECT  77.22 141.075 96.12 141.345 ;
     RECT  2.16 141.615 41.148 141.885 ;
     RECT  77.22 141.615 96.12 141.885 ;
     RECT  2.16 142.155 41.148 142.425 ;
     RECT  77.22 142.155 96.12 142.425 ;
     RECT  2.16 142.695 41.148 142.965 ;
     RECT  77.22 142.695 96.12 142.965 ;
     RECT  2.16 143.235 41.148 143.505 ;
     RECT  77.22 143.235 96.12 143.505 ;
     RECT  2.16 143.775 41.148 144.045 ;
     RECT  77.22 143.775 96.12 144.045 ;
     RECT  2.16 144.315 41.148 144.585 ;
     RECT  77.22 144.315 96.12 144.585 ;
     RECT  2.16 144.855 41.148 145.125 ;
     RECT  77.22 144.855 96.12 145.125 ;
     RECT  2.16 145.395 41.148 145.665 ;
     RECT  77.22 145.395 96.12 145.665 ;
     RECT  2.16 145.935 41.148 146.205 ;
     RECT  77.22 145.935 96.12 146.205 ;
     RECT  2.16 146.475 41.148 146.745 ;
     RECT  77.22 146.475 96.12 146.745 ;
     RECT  2.16 147.015 41.148 147.285 ;
     RECT  77.22 147.015 96.12 147.285 ;
     RECT  2.16 147.555 41.148 147.825 ;
     RECT  77.22 147.555 96.12 147.825 ;
     RECT  2.16 148.095 41.148 148.365 ;
     RECT  77.22 148.095 96.12 148.365 ;
     RECT  2.16 148.635 41.148 148.905 ;
     RECT  77.22 148.635 96.12 148.905 ;
     RECT  2.16 149.175 96.12 149.445 ;
     RECT  2.16 149.715 96.12 149.985 ;
     RECT  2.16 150.255 96.12 150.525 ;
     RECT  2.16 150.795 96.12 151.065 ;
     RECT  2.16 151.335 96.12 151.605 ;
     RECT  2.16 151.875 96.12 152.145 ;
     RECT  2.16 152.415 96.12 152.685 ;
     RECT  2.16 152.955 96.12 153.225 ;
     RECT  2.16 153.495 96.12 153.765 ;
     RECT  2.16 154.035 96.12 154.305 ;
     RECT  2.16 154.575 96.12 154.845 ;
     RECT  2.16 155.115 96.12 155.385 ;
     RECT  2.16 155.655 96.12 155.925 ;
     RECT  2.16 156.195 96.12 156.465 ;
     RECT  2.16 156.735 96.12 157.005 ;
     RECT  2.16 157.275 96.12 157.545 ;
     RECT  2.16 157.815 96.12 158.085 ;
     RECT  2.16 158.355 96.12 158.625 ;
     RECT  2.16 158.895 96.12 159.165 ;
     RECT  2.16 159.435 96.12 159.705 ;
     RECT  2.16 159.975 96.12 160.245 ;
     RECT  2.16 160.515 96.12 160.785 ;
     RECT  2.16 161.055 96.12 161.325 ;
     RECT  2.16 161.595 96.12 161.865 ;
     RECT  2.16 162.135 96.12 162.405 ;
     RECT  2.16 162.675 96.12 162.945 ;
     RECT  2.16 163.215 96.12 163.485 ;
     RECT  2.16 163.755 96.12 164.025 ;
     RECT  2.16 164.295 96.12 164.565 ;
     RECT  2.16 164.835 96.12 165.105 ;
     RECT  2.16 165.375 96.12 165.645 ;
     RECT  2.16 165.915 96.12 166.185 ;
     RECT  2.16 166.455 96.12 166.725 ;
     RECT  2.16 166.995 96.12 167.265 ;
     RECT  2.16 167.535 96.12 167.805 ;
     RECT  2.16 168.075 96.12 168.345 ;
    LAYER M1 ;
     RECT  2.16 2.151 96.12 41.049 ;
     RECT  43.2 43.2 75.192 60.504 ;
     RECT  2.16 41.049 41.148 62.631 ;
     RECT  77.22 41.049 96.12 62.631 ;
     RECT  2.16 62.631 96.12 84.249 ;
     RECT  43.2 86.4 75.192 103.704 ;
     RECT  2.16 84.249 41.148 105.831 ;
     RECT  77.22 84.249 96.12 105.831 ;
     RECT  2.16 105.831 96.12 127.449 ;
     RECT  43.2 129.6 75.192 146.904 ;
     RECT  2.16 127.449 41.148 149.031 ;
     RECT  77.22 127.449 96.12 149.031 ;
     RECT  2.16 149.031 96.12 168.489 ;
    LAYER M2 ;
     RECT  0.103 43.686 0.139 44.559 ;
     RECT  0.103 87.696 0.203 88.956 ;
     RECT  0.103 32.706 0.535 34.146 ;
     RECT  0.139 43.686 0.535 44.604 ;
     RECT  0.535 32.706 2.16 34.524 ;
     RECT  0.103 35.316 2.16 35.874 ;
     RECT  0.535 42.606 2.16 44.604 ;
     RECT  0.103 79.056 2.16 80.154 ;
     RECT  0.535 81.216 2.16 81.234 ;
     RECT  0.103 82.026 2.16 83.124 ;
     RECT  0.103 84.726 2.16 85.446 ;
     RECT  0.535 86.346 2.16 86.364 ;
     RECT  0.203 87.696 2.16 88.254 ;
     RECT  0.103 123.606 2.16 123.624 ;
     RECT  1.723 125.388 2.16 125.406 ;
     RECT  0.103 126.306 2.16 126.324 ;
     RECT  1.723 130.518 2.16 130.536 ;
     RECT  0.103 131.976 2.16 131.994 ;
     RECT  37.831 170.586 37.903 170.604 ;
     RECT  37.903 170.514 38.003 170.604 ;
     RECT  38.003 170.586 38.039 170.604 ;
     RECT  2.16 2.151 41.148 168.489 ;
     RECT  41.148 85.428 41.315 85.482 ;
     RECT  41.148 105.831 41.315 128.34 ;
     RECT  41.148 136.764 41.315 140.994 ;
     RECT  41.315 85.428 41.387 85.446 ;
     RECT  41.148 50.4 41.423 56.214 ;
     RECT  41.423 50.4 41.459 54.054 ;
     RECT  41.148 86.472 41.459 89.298 ;
     RECT  41.148 96.966 41.459 100.566 ;
     RECT  41.459 87.048 41.495 89.298 ;
     RECT  41.459 96.966 41.495 98.874 ;
     RECT  41.495 87.048 41.531 88.92 ;
     RECT  41.495 97.236 41.531 98.874 ;
     RECT  41.459 50.4 41.567 52.974 ;
     RECT  41.423 54.954 41.567 56.214 ;
     RECT  41.531 97.236 41.567 97.794 ;
     RECT  41.459 54.036 41.603 54.054 ;
     RECT  41.567 97.416 41.603 97.794 ;
     RECT  41.148 45.198 41.639 49.5 ;
     RECT  41.148 132.984 41.639 133.2 ;
     RECT  41.639 45.198 41.675 47.484 ;
     RECT  41.639 48.276 41.675 49.5 ;
     RECT  41.148 94.032 41.675 96.174 ;
     RECT  41.315 137.574 41.675 140.994 ;
     RECT  41.675 137.844 41.747 140.994 ;
     RECT  41.675 48.438 41.783 49.5 ;
     RECT  41.675 46.476 41.819 47.484 ;
     RECT  41.567 50.4 41.891 52.884 ;
     RECT  41.459 99.936 41.891 100.566 ;
     RECT  41.567 54.954 41.927 55.044 ;
     RECT  41.567 56.106 41.963 56.214 ;
     RECT  41.148 60.471 41.999 61.758 ;
     RECT  41.531 87.354 41.999 88.92 ;
     RECT  41.148 141.786 41.999 143.334 ;
     RECT  41.963 56.196 42.035 56.214 ;
     RECT  41.999 88.47 42.071 88.92 ;
     RECT  41.675 94.842 42.071 96.174 ;
     RECT  41.148 130.284 42.071 130.536 ;
     RECT  41.891 50.4 42.143 52.776 ;
     RECT  41.747 138.078 42.143 140.994 ;
     RECT  42.143 50.4 42.179 51.264 ;
     RECT  42.143 52.146 42.179 52.614 ;
     RECT  42.071 94.878 42.179 96.174 ;
     RECT  42.143 138.078 42.179 139.104 ;
     RECT  41.148 44.154 42.215 44.442 ;
     RECT  41.675 45.198 42.215 45.522 ;
     RECT  41.819 46.656 42.215 47.484 ;
     RECT  41.783 48.438 42.215 48.456 ;
     RECT  42.179 50.4 42.215 50.994 ;
     RECT  42.215 46.854 42.251 47.484 ;
     RECT  41.999 87.354 42.259 87.678 ;
     RECT  41.148 42.696 42.287 42.786 ;
     RECT  41.148 131.526 42.323 132.228 ;
     RECT  41.148 62.631 42.331 84.249 ;
     RECT  42.323 131.526 42.359 131.85 ;
     RECT  42.331 62.631 42.431 84.294 ;
     RECT  41.927 54.954 42.467 54.972 ;
     RECT  41.603 97.416 42.467 97.434 ;
     RECT  42.511 102.546 42.547 102.564 ;
     RECT  41.148 103.752 42.547 105.039 ;
     RECT  41.315 105.831 42.547 127.674 ;
     RECT  41.783 49.248 42.943 49.5 ;
     RECT  42.979 90.711 43.015 90.729 ;
     RECT  41.999 60.552 43.087 61.758 ;
     RECT  42.431 62.631 43.087 84.249 ;
     RECT  42.547 103.752 43.115 127.674 ;
     RECT  43.087 60.552 43.187 84.249 ;
     RECT  42.287 42.696 43.2 42.75 ;
     RECT  42.215 44.154 43.2 44.172 ;
     RECT  42.215 45.504 43.2 45.522 ;
     RECT  42.251 47.466 43.2 47.484 ;
     RECT  42.943 49.248 43.2 49.644 ;
     RECT  42.215 50.4 43.2 50.724 ;
     RECT  43.051 54.72 43.2 54.738 ;
     RECT  41.148 57.276 43.2 57.294 ;
     RECT  43.187 60.552 43.2 61.758 ;
     RECT  42.259 86.616 43.2 87.678 ;
     RECT  42.071 88.47 43.2 88.614 ;
     RECT  43.015 90.63 43.2 90.729 ;
     RECT  42.871 92.376 43.2 92.394 ;
     RECT  41.675 94.032 43.2 94.05 ;
     RECT  42.179 94.878 43.2 94.896 ;
     RECT  42.179 95.886 43.2 95.904 ;
     RECT  41.531 98.586 43.2 98.604 ;
     RECT  41.891 100.476 43.2 100.566 ;
     RECT  42.547 102.546 43.2 102.762 ;
     RECT  43.115 103.752 43.2 127.602 ;
     RECT  41.148 129.276 43.2 129.294 ;
     RECT  42.071 130.446 43.2 130.536 ;
     RECT  42.359 131.526 43.2 131.544 ;
     RECT  41.639 132.984 43.2 133.002 ;
     RECT  42.763 134.298 43.2 134.316 ;
     RECT  41.315 136.764 43.2 136.782 ;
     RECT  42.179 138.078 43.2 138.834 ;
     RECT  42.143 140.166 43.2 140.994 ;
     RECT  41.999 141.786 43.2 143.154 ;
     RECT  41.148 147.06 43.2 168.489 ;
     RECT  43.2 42.696 46.759 61.758 ;
     RECT  43.187 62.514 46.759 84.249 ;
     RECT  46.759 42.696 50.855 84.249 ;
     RECT  43.2 86.4 54.743 127.602 ;
     RECT  50.855 42.696 74.659 61.758 ;
     RECT  50.855 62.514 74.659 84.249 ;
     RECT  54.743 86.4 75.055 127.449 ;
     RECT  74.659 42.696 75.192 84.249 ;
     RECT  75.055 86.076 75.192 127.449 ;
     RECT  43.2 129.276 75.192 168.489 ;
     RECT  75.192 86.076 75.263 86.364 ;
     RECT  75.192 60.246 75.271 84.249 ;
     RECT  75.019 128.241 75.271 128.259 ;
     RECT  75.192 129.276 75.271 130.302 ;
     RECT  75.192 54.72 75.335 54.738 ;
     RECT  75.192 91.296 75.335 91.386 ;
     RECT  75.271 128.241 75.335 130.302 ;
     RECT  75.192 146.448 75.335 168.489 ;
     RECT  75.192 58.698 75.371 58.716 ;
     RECT  75.271 60.246 75.371 84.942 ;
     RECT  75.192 98.046 75.371 98.64 ;
     RECT  75.335 128.781 75.371 130.302 ;
     RECT  75.192 103.752 75.379 127.449 ;
     RECT  75.335 91.296 75.443 91.314 ;
     RECT  75.371 60.246 75.479 84.249 ;
     RECT  75.192 44.73 75.515 45.144 ;
     RECT  75.263 86.346 75.623 86.364 ;
     RECT  75.379 103.752 75.659 127.53 ;
     RECT  75.192 89.856 75.803 89.874 ;
     RECT  75.192 132.714 76.055 132.804 ;
     RECT  75.192 100.206 76.063 100.224 ;
     RECT  75.192 139.932 76.099 139.95 ;
     RECT  76.099 55.836 76.135 55.854 ;
     RECT  75.371 98.046 76.135 98.064 ;
     RECT  76.063 54.954 76.171 54.972 ;
     RECT  76.135 55.836 76.171 55.944 ;
     RECT  76.099 97.074 76.171 97.092 ;
     RECT  76.099 139.932 76.171 140.562 ;
     RECT  76.063 141.318 76.171 141.336 ;
     RECT  76.135 98.046 76.207 98.172 ;
     RECT  76.171 139.932 76.235 141.336 ;
     RECT  76.171 54.954 76.243 55.944 ;
     RECT  75.192 48.366 76.279 48.384 ;
     RECT  76.063 100.008 76.279 100.224 ;
     RECT  76.279 91.17 76.315 91.188 ;
     RECT  76.279 48.366 76.351 48.996 ;
     RECT  76.315 91.17 76.351 91.728 ;
     RECT  75.192 92.79 76.351 92.808 ;
     RECT  75.192 94.032 76.351 95.13 ;
     RECT  75.192 134.766 76.351 137.358 ;
     RECT  76.351 48.132 76.387 48.996 ;
     RECT  75.192 50.058 76.387 50.076 ;
     RECT  76.351 91.17 76.387 92.808 ;
     RECT  76.351 93.798 76.387 95.13 ;
     RECT  76.171 97.074 76.387 97.254 ;
     RECT  76.351 134.37 76.387 137.358 ;
     RECT  76.243 142.128 76.387 142.146 ;
     RECT  76.387 52.146 76.423 52.164 ;
     RECT  76.387 52.992 76.423 53.01 ;
     RECT  76.387 134.37 76.423 138.708 ;
     RECT  76.423 52.146 76.675 53.01 ;
     RECT  75.371 129.276 76.891 130.302 ;
     RECT  76.639 54.108 76.963 54.126 ;
     RECT  76.243 54.954 76.963 56.052 ;
     RECT  76.891 129.204 76.963 130.302 ;
     RECT  76.423 134.37 77.215 138.87 ;
     RECT  76.235 139.932 77.215 141.174 ;
     RECT  41.148 2.151 77.22 41.049 ;
     RECT  75.192 42.696 77.22 42.75 ;
     RECT  75.192 43.956 77.22 43.974 ;
     RECT  75.515 44.892 77.22 45.144 ;
     RECT  75.192 46.926 77.22 46.944 ;
     RECT  76.387 48.132 77.22 51.39 ;
     RECT  76.675 52.146 77.22 53.352 ;
     RECT  76.963 54.108 77.22 56.052 ;
     RECT  75.479 60.246 77.22 61.758 ;
     RECT  75.479 62.514 77.22 84.249 ;
     RECT  75.192 87.156 77.22 87.174 ;
     RECT  75.192 88.902 77.22 88.92 ;
     RECT  76.387 91.17 77.22 97.254 ;
     RECT  76.207 98.046 77.22 98.37 ;
     RECT  76.279 99.576 77.22 100.224 ;
     RECT  76.675 101.592 77.22 101.61 ;
     RECT  75.659 103.752 77.22 127.449 ;
     RECT  76.963 129.204 77.22 130.5 ;
     RECT  76.387 132.336 77.22 132.354 ;
     RECT  76.387 133.416 77.22 133.434 ;
     RECT  77.215 134.37 77.22 141.174 ;
     RECT  76.387 142.128 77.22 142.65 ;
     RECT  75.192 143.712 77.22 143.73 ;
     RECT  76.135 145.872 77.22 145.89 ;
     RECT  75.335 146.952 77.22 168.489 ;
     RECT  77.22 2.151 96.12 168.489 ;
     RECT  96.12 38.718 96.935 38.736 ;
     RECT  96.12 52.56 96.935 52.578 ;
     RECT  96.12 83.268 96.935 83.628 ;
     RECT  96.12 97.308 96.935 98.748 ;
     RECT  96.12 40.068 97.475 41.166 ;
     RECT  96.12 42.228 97.475 42.246 ;
     RECT  96.12 54.108 97.475 54.396 ;
     RECT  96.12 82.458 97.475 82.476 ;
     RECT  96.935 83.268 97.475 83.286 ;
     RECT  96.12 84.618 97.475 84.636 ;
     RECT  96.12 85.428 97.475 85.446 ;
     RECT  96.12 96.498 97.475 96.516 ;
     RECT  96.935 97.308 97.475 97.326 ;
     RECT  96.935 98.118 97.475 98.136 ;
     RECT  96.12 99.738 97.475 99.756 ;
     RECT  96.12 100.548 97.475 100.566 ;
     RECT  96.12 139.968 97.475 139.986 ;
     RECT  96.12 141.858 97.475 141.876 ;
    LAYER M3 ;
     RECT  2.415 2.143 2.505 2.413 ;
     RECT  5.115 2.143 5.205 2.413 ;
     RECT  7.815 2.143 7.905 2.413 ;
     RECT  10.515 2.143 10.605 2.413 ;
     RECT  13.215 2.143 13.305 2.413 ;
     RECT  15.915 2.143 16.005 2.413 ;
     RECT  18.615 2.143 18.705 2.413 ;
     RECT  21.315 2.143 21.405 2.413 ;
     RECT  24.015 2.143 24.105 2.413 ;
     RECT  26.715 2.143 26.805 2.413 ;
     RECT  29.415 2.143 29.505 2.413 ;
     RECT  32.115 2.143 32.205 2.413 ;
     RECT  34.815 2.143 34.905 2.413 ;
     RECT  37.515 2.143 37.605 2.413 ;
     RECT  40.215 2.143 40.305 2.413 ;
     RECT  42.915 2.143 43.005 2.413 ;
     RECT  45.615 2.143 45.705 2.413 ;
     RECT  48.315 2.143 48.405 2.413 ;
     RECT  51.015 2.143 51.105 2.413 ;
     RECT  53.715 2.143 53.805 2.413 ;
     RECT  56.415 2.143 56.505 2.413 ;
     RECT  59.115 2.143 59.205 2.413 ;
     RECT  61.815 2.143 61.905 2.413 ;
     RECT  64.515 2.143 64.605 2.413 ;
     RECT  67.215 2.143 67.305 2.413 ;
     RECT  69.915 2.143 70.005 2.413 ;
     RECT  72.615 2.143 72.705 2.413 ;
     RECT  75.315 2.143 75.405 2.413 ;
     RECT  78.015 2.143 78.105 2.413 ;
     RECT  80.715 2.143 80.805 2.413 ;
     RECT  83.415 2.143 83.505 2.413 ;
     RECT  86.115 2.143 86.205 2.413 ;
     RECT  88.815 2.143 88.905 2.413 ;
     RECT  91.515 2.143 91.605 2.413 ;
     RECT  94.215 2.143 94.305 2.413 ;
     RECT  7.815 2.413 8.097 31.657 ;
     RECT  4.176 31.657 4.194 31.723 ;
     RECT  2.415 2.413 2.697 31.729 ;
     RECT  3.42 31.621 3.438 31.729 ;
     RECT  4.176 31.723 4.23 31.729 ;
     RECT  5.115 2.413 5.397 31.729 ;
     RECT  2.415 31.729 5.397 31.801 ;
     RECT  0.144 31.723 0.162 31.853 ;
     RECT  6.732 31.657 6.822 31.891 ;
     RECT  7.815 31.657 8.118 31.891 ;
     RECT  6.732 31.891 8.118 31.919 ;
     RECT  2.415 31.801 5.85 32.099 ;
     RECT  2.415 32.099 3.51 32.141 ;
     RECT  10.515 2.413 10.797 32.161 ;
     RECT  40.215 2.413 40.497 32.161 ;
     RECT  7.164 31.919 8.118 32.305 ;
     RECT  8.856 31.801 8.874 32.305 ;
     RECT  10.515 32.161 10.854 32.369 ;
     RECT  2.415 32.141 2.697 32.395 ;
     RECT  2.304 32.395 2.697 32.459 ;
     RECT  4.248 32.099 5.85 32.491 ;
     RECT  3.456 32.141 3.51 32.827 ;
     RECT  4.248 32.491 6.102 32.827 ;
     RECT  7.164 32.305 8.874 32.845 ;
     RECT  2.415 32.459 2.697 33.043 ;
     RECT  3.456 32.827 6.102 33.043 ;
     RECT  2.415 33.043 6.246 33.151 ;
     RECT  7.02 32.845 8.874 33.151 ;
     RECT  40.215 32.161 40.554 33.889 ;
     RECT  0.108 32.683 0.126 34.151 ;
     RECT  2.415 33.151 8.874 34.159 ;
     RECT  2.415 34.159 9.414 34.187 ;
     RECT  2.415 34.187 8.097 34.259 ;
     RECT  39.6 33.889 40.554 34.465 ;
     RECT  0.54 34.501 0.558 34.589 ;
     RECT  42.915 2.413 43.197 34.771 ;
     RECT  2.415 34.259 2.697 35.005 ;
     RECT  3.42 34.259 8.097 35.005 ;
     RECT  39.024 34.465 40.554 35.041 ;
     RECT  2.415 35.005 8.097 35.323 ;
     RECT  8.82 34.187 9.414 35.323 ;
     RECT  2.415 35.323 9.414 35.563 ;
     RECT  2.304 35.563 9.414 35.581 ;
     RECT  10.515 32.369 10.797 35.581 ;
     RECT  2.304 35.581 10.797 35.779 ;
     RECT  2.232 35.779 10.797 35.885 ;
     RECT  0.108 35.131 0.126 36.269 ;
     RECT  39.024 35.041 40.698 37.363 ;
     RECT  41.58 37.201 41.598 37.363 ;
     RECT  39.024 37.363 41.598 37.399 ;
     RECT  42.66 34.771 43.197 37.399 ;
     RECT  2.415 35.885 10.797 37.463 ;
     RECT  94.215 2.413 94.497 37.831 ;
     RECT  94.215 37.831 94.554 37.915 ;
     RECT  94.215 37.915 95.13 38.005 ;
     RECT  93.96 38.005 95.13 38.155 ;
     RECT  95.904 38.101 95.922 38.155 ;
     RECT  93.96 38.155 95.922 38.551 ;
     RECT  91.515 2.413 91.797 38.731 ;
     RECT  96.912 38.713 96.93 38.765 ;
     RECT  93.852 38.551 95.922 38.821 ;
     RECT  88.815 2.413 89.097 39.091 ;
     RECT  91.515 38.731 92.214 39.091 ;
     RECT  93.744 38.821 95.922 39.091 ;
     RECT  88.815 39.091 89.406 39.181 ;
     RECT  91.332 39.091 95.922 39.217 ;
     RECT  75.315 2.413 75.597 39.361 ;
     RECT  83.415 2.413 83.697 39.361 ;
     RECT  83.052 39.361 83.697 39.479 ;
     RECT  88.815 39.181 89.478 39.523 ;
     RECT  90.252 38.971 90.27 39.523 ;
     RECT  75.315 39.361 75.69 39.631 ;
     RECT  2.415 37.463 8.097 39.659 ;
     RECT  88.815 39.523 90.27 39.721 ;
     RECT  91.188 39.217 95.922 39.721 ;
     RECT  88.815 39.721 95.922 39.749 ;
     RECT  88.815 39.749 95.85 39.869 ;
     RECT  88.815 39.869 95.778 39.917 ;
     RECT  86.115 2.413 86.397 40.171 ;
     RECT  88.815 39.917 95.706 40.205 ;
     RECT  39.024 37.399 43.197 40.261 ;
     RECT  38.772 40.261 43.197 40.433 ;
     RECT  86.115 40.171 86.67 40.433 ;
     RECT  75.315 39.631 75.798 40.441 ;
     RECT  64.515 2.413 64.797 40.531 ;
     RECT  88.815 40.205 92.502 40.559 ;
     RECT  93.528 40.205 95.706 40.559 ;
     RECT  88.815 40.559 91.998 40.589 ;
     RECT  2.415 39.659 3.042 40.711 ;
     RECT  4.176 39.659 8.097 40.711 ;
     RECT  45.615 2.413 45.897 40.711 ;
     RECT  64.515 40.531 64.926 40.711 ;
     RECT  75.315 40.441 76.086 40.711 ;
     RECT  39.024 40.433 43.197 40.787 ;
     RECT  48.315 2.413 48.597 40.787 ;
     RECT  51.015 2.413 51.297 40.787 ;
     RECT  53.715 2.413 53.997 40.787 ;
     RECT  59.115 2.413 59.397 40.787 ;
     RECT  61.815 2.413 62.097 40.787 ;
     RECT  67.215 2.413 67.497 40.787 ;
     RECT  69.915 2.413 70.197 40.787 ;
     RECT  72.615 2.413 72.897 40.787 ;
     RECT  64.515 40.711 64.962 40.801 ;
     RECT  80.715 2.413 80.997 40.801 ;
     RECT  57.42 40.555 57.438 40.829 ;
     RECT  45.615 40.711 46.242 40.837 ;
     RECT  56.415 2.413 56.697 40.837 ;
     RECT  45.615 40.837 46.314 40.877 ;
     RECT  56.415 40.837 57.114 40.877 ;
     RECT  64.515 40.801 65.25 40.877 ;
     RECT  45.615 40.877 46.242 41.009 ;
     RECT  64.515 40.877 64.962 41.021 ;
     RECT  45.615 41.009 45.705 41.057 ;
     RECT  48.315 40.787 48.405 41.057 ;
     RECT  51.015 40.787 51.105 41.057 ;
     RECT  53.715 40.787 53.805 41.057 ;
     RECT  56.415 40.877 56.505 41.057 ;
     RECT  59.115 40.787 59.205 41.057 ;
     RECT  61.815 40.787 61.905 41.057 ;
     RECT  64.515 41.021 64.605 41.057 ;
     RECT  67.215 40.787 67.305 41.057 ;
     RECT  69.915 40.787 70.005 41.057 ;
     RECT  72.615 40.787 72.705 41.057 ;
     RECT  80.715 40.801 81.522 41.099 ;
     RECT  2.415 40.711 8.097 41.165 ;
     RECT  97.452 40.027 97.47 41.171 ;
     RECT  93.528 40.559 95.634 41.215 ;
     RECT  86.115 40.433 86.634 41.243 ;
     RECT  93.456 41.215 95.634 41.341 ;
     RECT  3.996 41.165 8.097 41.371 ;
     RECT  8.82 37.463 10.797 41.371 ;
     RECT  11.844 40.837 11.862 41.405 ;
     RECT  93.456 41.341 95.742 41.485 ;
     RECT  93.456 41.485 95.778 41.498 ;
     RECT  88.815 40.589 91.962 41.521 ;
     RECT  92.916 41.498 95.778 41.521 ;
     RECT  2.415 41.165 3.042 41.611 ;
     RECT  86.115 41.243 86.397 41.611 ;
     RECT  75.168 40.711 76.086 41.645 ;
     RECT  2.304 41.611 3.042 41.648 ;
     RECT  3.996 41.371 10.797 41.791 ;
     RECT  80.715 41.099 80.997 41.791 ;
     RECT  3.996 41.791 10.854 41.909 ;
     RECT  85.428 41.611 86.397 41.909 ;
     RECT  2.415 41.648 3.042 41.947 ;
     RECT  3.996 41.909 10.797 41.947 ;
     RECT  88.815 41.521 95.778 42.025 ;
     RECT  97.452 42.187 97.47 42.251 ;
     RECT  83.415 39.479 83.697 42.331 ;
     RECT  0.144 41.035 0.162 42.365 ;
     RECT  82.98 42.331 83.697 42.449 ;
     RECT  87.48 42.331 87.498 42.449 ;
     RECT  88.815 42.025 95.922 42.449 ;
     RECT  39.024 40.787 43.11 42.493 ;
     RECT  80.1 41.791 80.997 42.727 ;
     RECT  37.515 2.413 37.797 43.033 ;
     RECT  38.916 42.493 43.11 43.033 ;
     RECT  37.515 43.033 43.11 43.2 ;
     RECT  75.276 41.645 76.086 43.2 ;
     RECT  0.54 42.601 0.558 43.229 ;
     RECT  87.84 42.997 87.858 43.259 ;
     RECT  88.815 42.449 95.85 43.339 ;
     RECT  2.415 41.947 10.797 43.979 ;
     RECT  0.108 43.483 0.126 44.149 ;
     RECT  2.415 43.979 9.018 44.177 ;
     RECT  2.415 44.177 8.982 44.203 ;
     RECT  2.304 44.203 8.982 44.249 ;
     RECT  34.815 2.413 35.097 44.311 ;
     RECT  88.815 43.339 95.922 44.339 ;
     RECT  88.815 44.339 95.778 44.375 ;
     RECT  0.108 44.149 0.558 44.381 ;
     RECT  78.015 2.413 78.297 44.581 ;
     RECT  78.015 44.581 78.678 44.635 ;
     RECT  78.015 44.635 78.786 44.731 ;
     RECT  0.108 44.381 0.198 44.765 ;
     RECT  88.815 44.375 95.454 44.765 ;
     RECT  0.108 44.765 0.162 44.813 ;
     RECT  78.015 44.731 78.894 44.909 ;
     RECT  90.072 44.765 95.454 44.915 ;
     RECT  80.064 42.727 80.997 45.019 ;
     RECT  81.756 43.141 81.774 45.019 ;
     RECT  83.052 42.449 83.697 45.019 ;
     RECT  86.115 41.909 86.397 45.019 ;
     RECT  80.064 45.019 81.774 45.059 ;
     RECT  90.324 44.915 95.454 45.149 ;
     RECT  86.115 45.019 86.49 45.259 ;
     RECT  90.396 45.149 95.454 45.293 ;
     RECT  2.415 44.249 8.982 45.329 ;
     RECT  37.515 43.2 76.086 45.341 ;
     RECT  0.144 44.813 0.162 45.389 ;
     RECT  77.22 42.691 77.238 45.391 ;
     RECT  78.015 44.909 78.786 45.391 ;
     RECT  9.936 43.979 10.797 45.419 ;
     RECT  90.468 45.293 95.454 45.419 ;
     RECT  77.22 45.391 78.786 45.533 ;
     RECT  90.468 45.419 95.166 45.533 ;
     RECT  9.396 45.571 9.414 45.689 ;
     RECT  90.576 45.533 95.166 45.689 ;
     RECT  37.515 45.341 76.05 45.725 ;
     RECT  90.576 45.689 94.77 45.761 ;
     RECT  88.815 44.765 89.19 45.841 ;
     RECT  2.415 45.329 8.622 45.959 ;
     RECT  37.515 45.725 76.014 46.109 ;
     RECT  82.656 45.019 83.697 46.109 ;
     RECT  81.756 45.059 81.774 46.201 ;
     RECT  81.756 46.201 82.098 46.253 ;
     RECT  90.576 45.761 94.626 46.349 ;
     RECT  77.22 45.533 78.678 46.499 ;
     RECT  34.815 44.311 35.37 46.571 ;
     RECT  78.015 46.499 78.678 46.747 ;
     RECT  90.576 46.349 94.497 46.949 ;
     RECT  78.015 46.747 78.894 47.047 ;
     RECT  83.052 46.109 83.697 47.047 ;
     RECT  83.052 47.047 84.366 47.069 ;
     RECT  81.756 46.253 81.774 47.117 ;
     RECT  88.815 45.841 89.514 47.147 ;
     RECT  83.16 47.069 84.366 47.165 ;
     RECT  78.015 47.047 78.93 47.213 ;
     RECT  78.015 47.213 78.39 47.219 ;
     RECT  90.576 46.949 90.666 47.219 ;
     RECT  88.815 47.147 89.406 47.309 ;
     RECT  83.415 47.165 84.366 47.405 ;
     RECT  83.415 47.405 84.33 47.645 ;
     RECT  86.115 45.259 86.67 47.693 ;
     RECT  37.515 46.109 75.726 47.837 ;
     RECT  79.2 47.467 79.218 47.849 ;
     RECT  43.2 47.837 75.726 48.127 ;
     RECT  3.492 45.959 8.622 48.389 ;
     RECT  77.22 46.499 77.238 48.433 ;
     RECT  78.015 47.219 78.297 48.433 ;
     RECT  34.815 46.571 35.097 48.505 ;
     RECT  4.32 48.389 8.622 48.533 ;
     RECT  4.32 48.533 6.246 48.569 ;
     RECT  43.2 48.127 76.374 48.661 ;
     RECT  77.22 48.433 78.297 48.661 ;
     RECT  43.2 48.661 78.297 48.701 ;
     RECT  4.32 48.569 5.397 48.839 ;
     RECT  43.2 48.701 76.41 49.085 ;
     RECT  7.164 48.533 8.622 49.109 ;
     RECT  76.356 49.085 76.41 49.181 ;
     RECT  13.215 2.413 13.497 49.243 ;
     RECT  21.315 2.413 21.597 49.243 ;
     RECT  29.415 2.413 29.697 49.243 ;
     RECT  37.515 47.837 42.21 49.243 ;
     RECT  43.2 49.085 75.192 49.243 ;
     RECT  13.215 49.243 13.59 49.373 ;
     RECT  14.832 49.243 14.85 49.373 ;
     RECT  21.315 49.243 21.69 49.373 ;
     RECT  22.824 49.243 22.842 49.373 ;
     RECT  29.415 49.243 29.79 49.373 ;
     RECT  30.78 49.243 30.798 49.373 ;
     RECT  6.228 48.569 6.246 49.379 ;
     RECT  3.492 48.389 3.51 49.469 ;
     RECT  4.932 48.839 5.397 49.649 ;
     RECT  34.776 48.505 35.097 49.739 ;
     RECT  7.308 49.109 8.622 49.847 ;
     RECT  7.815 49.847 8.622 49.883 ;
     RECT  7.815 49.883 8.154 49.919 ;
     RECT  37.515 49.243 75.192 50.053 ;
     RECT  76.392 49.181 76.41 50.053 ;
     RECT  37.515 50.053 76.41 50.237 ;
     RECT  91.515 46.949 94.497 50.665 ;
     RECT  91.404 50.665 94.497 50.717 ;
     RECT  37.515 50.237 75.192 50.855 ;
     RECT  39.204 50.855 75.192 51.389 ;
     RECT  90.576 47.219 90.594 51.451 ;
     RECT  39.204 51.389 42.21 51.581 ;
     RECT  37.515 50.855 38.394 51.595 ;
     RECT  95.256 51.451 95.274 51.629 ;
     RECT  37.515 51.595 38.466 51.635 ;
     RECT  39.204 51.581 42.174 51.781 ;
     RECT  95.76 51.883 95.85 52.051 ;
     RECT  95.76 52.051 95.886 52.141 ;
     RECT  95.76 52.141 95.922 52.253 ;
     RECT  91.515 50.717 94.497 52.321 ;
     RECT  95.76 52.253 95.886 52.445 ;
     RECT  38.808 51.781 42.174 52.507 ;
     RECT  43.056 51.389 75.192 52.507 ;
     RECT  95.76 52.445 95.778 52.589 ;
     RECT  38.808 52.507 75.192 52.651 ;
     RECT  88.815 47.309 89.097 52.699 ;
     RECT  38.556 52.651 75.192 52.709 ;
     RECT  96.912 52.555 96.93 52.733 ;
     RECT  90.576 51.451 90.666 52.747 ;
     RECT  91.515 52.321 94.734 52.747 ;
     RECT  86.115 47.693 86.397 52.789 ;
     RECT  76.392 50.237 76.41 52.825 ;
     RECT  90.576 52.747 94.95 52.825 ;
     RECT  90.576 52.825 95.742 53.015 ;
     RECT  90.576 53.015 94.698 53.131 ;
     RECT  76.392 52.825 76.446 53.275 ;
     RECT  77.22 48.701 78.297 53.275 ;
     RECT  86.115 52.789 86.67 53.365 ;
     RECT  76.392 53.275 78.297 53.371 ;
     RECT  86.115 53.365 86.706 53.401 ;
     RECT  88.815 52.699 89.37 53.401 ;
     RECT  80.064 45.059 80.997 53.429 ;
     RECT  86.115 53.401 86.778 53.555 ;
     RECT  38.844 52.709 75.192 53.563 ;
     RECT  76.14 53.371 78.297 53.563 ;
     RECT  88.815 53.401 89.514 53.591 ;
     RECT  88.815 53.591 89.37 53.597 ;
     RECT  90.288 53.131 94.698 53.597 ;
     RECT  38.844 53.563 78.297 53.611 ;
     RECT  38.7 53.611 78.297 53.663 ;
     RECT  95.436 53.015 95.742 53.803 ;
     RECT  91.515 53.597 94.698 53.851 ;
     RECT  95.436 53.803 95.922 53.851 ;
     RECT  39.168 53.663 78.297 53.969 ;
     RECT  39.168 53.969 39.438 54.095 ;
     RECT  90.288 53.597 90.702 54.331 ;
     RECT  91.515 53.851 95.922 54.331 ;
     RECT  90.288 54.331 95.922 54.365 ;
     RECT  97.452 53.851 97.47 54.401 ;
     RECT  88.815 53.597 89.097 54.571 ;
     RECT  90.288 54.365 95.778 54.607 ;
     RECT  88.815 54.571 89.37 55.021 ;
     RECT  88.815 55.021 89.406 55.111 ;
     RECT  90.144 54.607 95.778 55.111 ;
     RECT  40.215 53.969 78.297 55.183 ;
     RECT  79.488 54.067 79.506 55.183 ;
     RECT  88.815 55.111 95.778 55.243 ;
     RECT  88.815 55.243 95.994 55.283 ;
     RECT  86.115 53.555 86.397 55.489 ;
     RECT  86.115 55.489 86.706 55.525 ;
     RECT  86.115 55.525 86.778 55.679 ;
     RECT  88.815 55.283 95.922 55.679 ;
     RECT  98.1 55.867 98.118 55.997 ;
     RECT  86.115 55.679 86.67 56.129 ;
     RECT  80.496 53.429 80.997 56.669 ;
     RECT  88.815 55.679 95.778 56.759 ;
     RECT  90.972 56.759 95.778 56.827 ;
     RECT  88.815 56.759 90.162 56.957 ;
     RECT  90.972 56.827 95.85 57.053 ;
     RECT  91.515 57.053 95.85 57.115 ;
     RECT  89.892 56.957 90.162 57.149 ;
     RECT  91.515 57.115 95.922 58.109 ;
     RECT  91.515 58.109 95.778 58.145 ;
     RECT  40.215 55.183 79.506 60.269 ;
     RECT  40.215 60.269 75.33 60.504 ;
     RECT  70.704 60.504 70.794 60.683 ;
     RECT  74.736 60.504 75.33 60.683 ;
     RECT  70.704 60.683 70.722 60.764 ;
     RECT  76.068 60.269 79.506 60.809 ;
     RECT  91.515 58.145 95.382 61.079 ;
     RECT  91.515 61.079 94.878 61.115 ;
     RECT  91.515 61.115 93.15 61.151 ;
     RECT  76.104 60.809 79.506 61.259 ;
     RECT  76.176 61.259 79.506 61.385 ;
     RECT  94.215 61.115 94.878 61.619 ;
     RECT  40.215 60.504 43.146 61.691 ;
     RECT  92.556 61.151 93.15 61.691 ;
     RECT  40.215 61.691 40.878 61.727 ;
     RECT  76.644 61.385 79.506 61.727 ;
     RECT  40.215 61.727 40.662 61.763 ;
     RECT  77.292 61.727 79.506 61.763 ;
     RECT  41.688 61.691 43.146 62.131 ;
     RECT  75.204 60.683 75.33 62.401 ;
     RECT  50.832 62.437 50.85 62.509 ;
     RECT  74.664 62.401 75.474 62.537 ;
     RECT  90.144 57.149 90.162 62.537 ;
     RECT  50.328 62.509 50.85 62.545 ;
     RECT  74.736 62.537 75.474 62.573 ;
     RECT  78.015 61.763 79.506 62.573 ;
     RECT  48.816 62.545 48.834 62.581 ;
     RECT  79.488 62.573 79.506 62.609 ;
     RECT  48.744 62.581 48.834 62.623 ;
     RECT  50.256 62.545 50.85 62.623 ;
     RECT  41.688 62.131 43.182 62.699 ;
     RECT  46.764 62.437 46.782 62.699 ;
     RECT  48.315 62.623 48.834 62.699 ;
     RECT  50.256 62.623 51.105 62.699 ;
     RECT  42.915 62.699 43.182 62.893 ;
     RECT  45.615 62.623 45.705 62.893 ;
     RECT  51.015 62.699 51.105 62.893 ;
     RECT  53.715 62.623 53.805 62.893 ;
     RECT  56.415 62.623 56.505 62.893 ;
     RECT  59.115 62.623 59.205 62.893 ;
     RECT  61.815 62.623 61.905 62.893 ;
     RECT  64.515 62.623 64.605 62.893 ;
     RECT  67.215 62.623 67.305 62.893 ;
     RECT  69.915 62.623 70.005 62.893 ;
     RECT  72.615 62.623 72.705 62.893 ;
     RECT  75.204 62.573 75.474 62.893 ;
     RECT  75.204 62.893 75.597 62.969 ;
     RECT  42.915 62.893 43.197 64.561 ;
     RECT  42.915 64.561 43.542 64.637 ;
     RECT  42.915 64.637 43.254 64.973 ;
     RECT  80.715 56.669 80.997 65.641 ;
     RECT  80.46 65.641 80.997 65.741 ;
     RECT  78.015 62.573 78.297 65.785 ;
     RECT  78.015 65.785 78.93 65.837 ;
     RECT  78.015 65.837 78.297 68.059 ;
     RECT  78.015 68.059 78.93 68.099 ;
     RECT  78.015 68.099 78.297 70.123 ;
     RECT  77.904 70.123 78.297 70.603 ;
     RECT  77.544 70.603 78.297 70.643 ;
     RECT  94.215 61.619 94.497 71.467 ;
     RECT  94.215 71.467 95.202 71.609 ;
     RECT  94.215 71.609 94.662 72.907 ;
     RECT  78.015 70.643 78.297 72.955 ;
     RECT  94.104 72.907 94.662 72.959 ;
     RECT  13.215 49.373 13.497 73.192 ;
     RECT  10.515 45.419 10.797 73.195 ;
     RECT  12.744 73.192 13.497 73.229 ;
     RECT  77.544 72.955 78.297 73.229 ;
     RECT  10.515 73.195 10.89 73.235 ;
     RECT  6.84 73.195 6.858 73.325 ;
     RECT  76.464 73.273 76.482 73.325 ;
     RECT  12.456 73.291 12.474 73.409 ;
     RECT  95.76 73.111 95.778 73.517 ;
     RECT  75.315 62.969 75.597 75.451 ;
     RECT  75.315 75.451 75.69 75.541 ;
     RECT  75.315 75.541 76.05 75.581 ;
     RECT  94.215 72.959 94.662 75.787 ;
     RECT  94.104 75.787 94.662 75.821 ;
     RECT  39.168 54.095 39.186 76.036 ;
     RECT  39.168 76.036 39.222 76.037 ;
     RECT  39.204 76.037 39.222 76.109 ;
     RECT  86.115 56.129 86.397 77.803 ;
     RECT  86.115 77.803 86.742 77.933 ;
     RECT  85.212 77.899 85.23 77.947 ;
     RECT  93.096 61.691 93.15 77.995 ;
     RECT  94.104 75.821 94.497 77.995 ;
     RECT  84.924 77.947 85.23 77.999 ;
     RECT  67.215 62.893 67.497 78.043 ;
     RECT  66.6 78.043 67.497 78.089 ;
     RECT  85.212 77.999 85.23 78.089 ;
     RECT  64.515 62.893 64.797 78.367 ;
     RECT  65.556 78.061 65.574 78.367 ;
     RECT  64.515 78.367 65.574 78.379 ;
     RECT  93.096 77.995 94.497 78.467 ;
     RECT  64.515 78.379 65.682 78.503 ;
     RECT  93.096 78.467 93.15 78.503 ;
     RECT  93.096 78.503 93.114 78.971 ;
     RECT  3.42 78.781 3.438 78.979 ;
     RECT  5.115 49.649 5.397 79.015 ;
     RECT  5.115 79.015 5.886 79.051 ;
     RECT  6.804 78.781 6.822 79.141 ;
     RECT  2.415 45.959 2.697 79.147 ;
     RECT  3.42 78.979 4.014 79.147 ;
     RECT  2.415 79.147 4.014 79.169 ;
     RECT  7.815 49.919 8.097 79.177 ;
     RECT  4.356 79.195 4.374 79.213 ;
     RECT  5.115 79.051 6.03 79.213 ;
     RECT  6.804 79.141 7.002 79.213 ;
     RECT  41.688 62.699 42.138 79.213 ;
     RECT  42.915 64.973 43.197 79.213 ;
     RECT  2.415 79.169 3.294 79.229 ;
     RECT  2.415 79.229 2.79 79.285 ;
     RECT  6.804 79.213 7.074 79.321 ;
     RECT  7.815 79.177 8.586 79.321 ;
     RECT  4.356 79.213 6.03 79.591 ;
     RECT  6.804 79.321 8.586 79.591 ;
     RECT  2.304 79.285 2.79 79.613 ;
     RECT  4.356 79.591 8.586 79.853 ;
     RECT  6.66 79.853 8.586 79.889 ;
     RECT  41.688 79.213 43.197 80.059 ;
     RECT  0.108 78.907 0.126 80.107 ;
     RECT  4.356 79.853 5.742 80.107 ;
     RECT  38.772 79.483 38.79 80.123 ;
     RECT  0.108 80.107 0.198 80.159 ;
     RECT  0.18 80.159 0.198 80.237 ;
     RECT  95.472 80.221 95.922 80.329 ;
     RECT  94.215 78.467 94.497 80.443 ;
     RECT  94.104 80.443 94.497 80.519 ;
     RECT  2.304 79.613 2.697 80.527 ;
     RECT  3.852 80.107 5.742 80.527 ;
     RECT  40.215 61.763 40.497 80.563 ;
     RECT  41.652 80.059 43.197 80.563 ;
     RECT  95.328 80.329 95.922 80.587 ;
     RECT  2.304 80.527 5.742 80.635 ;
     RECT  6.66 79.889 8.298 80.635 ;
     RECT  2.304 80.635 8.298 80.671 ;
     RECT  94.215 80.519 94.497 80.671 ;
     RECT  95.256 80.587 95.922 80.671 ;
     RECT  2.304 80.671 8.37 80.789 ;
     RECT  94.215 80.671 95.922 80.861 ;
     RECT  9.18 80.563 9.198 80.941 ;
     RECT  2.304 80.789 3.042 80.969 ;
     RECT  40.215 80.563 43.197 80.969 ;
     RECT  1.116 80.923 1.134 81.053 ;
     RECT  91.515 61.151 91.797 81.067 ;
     RECT  3.96 80.789 8.37 81.104 ;
     RECT  6.66 81.104 8.37 81.175 ;
     RECT  9.18 80.941 9.522 81.175 ;
     RECT  0.144 80.923 0.162 81.205 ;
     RECT  0.144 81.205 0.558 81.245 ;
     RECT  3.96 81.104 5.778 81.329 ;
     RECT  6.66 81.175 9.522 81.329 ;
     RECT  4.176 81.329 5.778 81.389 ;
     RECT  4.284 81.389 5.778 81.437 ;
     RECT  91.44 81.067 91.797 81.445 ;
     RECT  92.88 80.923 92.898 81.445 ;
     RECT  94.215 80.861 95.382 81.481 ;
     RECT  91.44 81.445 92.898 81.499 ;
     RECT  94.104 81.481 95.382 81.499 ;
     RECT  0.144 81.245 0.162 81.629 ;
     RECT  91.44 81.499 95.382 81.635 ;
     RECT  91.44 81.635 91.797 81.715 ;
     RECT  6.66 81.329 8.838 81.743 ;
     RECT  92.628 81.635 95.382 81.751 ;
     RECT  2.415 80.969 3.042 81.779 ;
     RECT  91.296 81.715 91.797 81.877 ;
     RECT  90 81.835 90.018 81.905 ;
     RECT  88.815 56.957 89.097 81.985 ;
     RECT  8.82 81.743 8.838 82.013 ;
     RECT  4.428 81.437 5.778 82.021 ;
     RECT  6.66 81.743 8.097 82.021 ;
     RECT  86.115 77.933 86.397 82.021 ;
     RECT  2.415 81.779 2.697 82.075 ;
     RECT  38.772 80.941 38.79 82.147 ;
     RECT  91.188 81.877 91.797 82.219 ;
     RECT  38.772 82.147 38.898 82.247 ;
     RECT  75.315 75.581 75.597 82.381 ;
     RECT  78.015 73.229 78.297 82.381 ;
     RECT  4.428 82.021 8.097 82.409 ;
     RECT  86.115 82.021 86.67 82.409 ;
     RECT  97.452 82.075 97.47 82.481 ;
     RECT  90.792 82.219 91.797 82.489 ;
     RECT  92.628 81.751 95.886 82.489 ;
     RECT  4.428 82.409 5.886 82.507 ;
     RECT  90.792 82.489 95.886 82.507 ;
     RECT  2.304 82.075 2.697 82.525 ;
     RECT  75.315 82.381 75.69 82.525 ;
     RECT  78.015 82.381 78.678 82.589 ;
     RECT  88.596 81.985 89.097 82.651 ;
     RECT  40.215 80.969 40.497 82.687 ;
     RECT  41.256 80.969 43.197 82.687 ;
     RECT  10.515 73.235 10.797 82.723 ;
     RECT  6.84 82.409 8.097 82.795 ;
     RECT  10.515 82.723 10.854 82.831 ;
     RECT  90.792 82.507 95.922 82.831 ;
     RECT  75.168 82.525 75.69 82.921 ;
     RECT  75.168 82.921 75.726 82.957 ;
     RECT  2.304 82.525 2.862 82.993 ;
     RECT  10.515 82.831 10.926 83.021 ;
     RECT  38.772 82.247 38.826 83.057 ;
     RECT  75.168 82.957 75.798 83.065 ;
     RECT  75.06 83.065 75.798 83.101 ;
     RECT  88.596 82.651 89.802 83.101 ;
     RECT  90.72 82.831 95.922 83.101 ;
     RECT  2.304 82.993 2.898 83.117 ;
     RECT  0.108 81.787 0.126 83.129 ;
     RECT  38.772 83.057 38.79 83.129 ;
     RECT  2.415 83.117 2.898 83.179 ;
     RECT  3.96 82.507 5.886 83.191 ;
     RECT  6.84 82.795 8.226 83.191 ;
     RECT  2.415 83.179 3.042 83.219 ;
     RECT  3.96 83.191 8.226 83.219 ;
     RECT  64.515 78.503 65.142 83.227 ;
     RECT  4.032 83.219 8.226 83.261 ;
     RECT  9.252 83.101 9.27 83.263 ;
     RECT  97.452 83.227 97.47 83.291 ;
     RECT  9.252 83.263 9.342 83.371 ;
     RECT  4.536 83.261 8.226 83.399 ;
     RECT  4.536 83.399 6.93 83.489 ;
     RECT  7.815 83.399 8.226 83.497 ;
     RECT  9.252 83.371 9.414 83.497 ;
     RECT  86.115 82.409 86.397 83.569 ;
     RECT  7.815 83.497 9.414 83.597 ;
     RECT  75.06 83.101 75.87 83.605 ;
     RECT  40.215 82.687 43.197 83.611 ;
     RECT  9.18 83.597 9.414 83.633 ;
     RECT  64.515 83.227 65.214 83.641 ;
     RECT  5.115 83.489 6.93 83.645 ;
     RECT  5.115 83.645 5.814 83.669 ;
     RECT  96.912 83.605 96.93 83.693 ;
     RECT  69.915 62.893 70.197 83.731 ;
     RECT  5.115 83.669 5.454 83.759 ;
     RECT  6.912 83.645 6.93 83.759 ;
     RECT  9.18 83.633 9.198 83.759 ;
     RECT  88.596 83.101 95.922 83.759 ;
     RECT  7.815 83.597 8.298 83.795 ;
     RECT  44.784 83.659 44.802 83.795 ;
     RECT  64.515 83.641 65.286 83.803 ;
     RECT  72.615 62.893 72.897 83.803 ;
     RECT  78.015 82.589 78.297 83.803 ;
     RECT  85.104 83.731 85.122 83.837 ;
     RECT  53.715 62.893 53.997 83.899 ;
     RECT  61.815 62.893 62.097 83.899 ;
     RECT  72.615 83.803 73.098 83.899 ;
     RECT  78.015 83.803 78.39 83.899 ;
     RECT  79.488 78.943 79.506 83.899 ;
     RECT  78.015 83.899 79.506 83.911 ;
     RECT  78.015 83.911 79.758 83.939 ;
     RECT  45.615 62.893 45.897 83.987 ;
     RECT  48.315 62.699 48.597 83.987 ;
     RECT  51.015 62.893 51.297 83.987 ;
     RECT  56.415 62.893 56.697 83.987 ;
     RECT  59.115 62.893 59.397 83.987 ;
     RECT  67.215 78.089 67.497 83.987 ;
     RECT  69.915 83.731 70.902 83.987 ;
     RECT  49.572 83.731 49.59 84.001 ;
     RECT  75.024 83.605 75.87 84.001 ;
     RECT  72.432 83.899 73.098 84.037 ;
     RECT  53.715 83.899 54.09 84.043 ;
     RECT  54.828 83.899 54.846 84.043 ;
     RECT  61.815 83.899 62.19 84.043 ;
     RECT  64.515 83.803 65.538 84.043 ;
     RECT  83.415 47.645 83.697 84.043 ;
     RECT  72.432 84.037 73.17 84.065 ;
     RECT  49.284 84.001 49.59 84.077 ;
     RECT  53.715 84.043 54.846 84.077 ;
     RECT  70.884 83.987 70.902 84.077 ;
     RECT  72.615 84.065 73.17 84.077 ;
     RECT  78.015 83.939 78.786 84.077 ;
     RECT  83.376 84.043 83.697 84.091 ;
     RECT  64.512 84.043 65.538 84.101 ;
     RECT  37.515 51.635 37.797 84.109 ;
     RECT  49.572 84.077 49.59 84.125 ;
     RECT  75.024 84.001 76.158 84.125 ;
     RECT  64.512 84.101 65.07 84.137 ;
     RECT  40.215 83.611 43.254 84.145 ;
     RECT  46.764 84.043 46.782 84.173 ;
     RECT  53.715 84.077 54.198 84.173 ;
     RECT  61.815 84.043 62.298 84.173 ;
     RECT  64.512 84.137 64.605 84.173 ;
     RECT  72.615 84.077 72.99 84.173 ;
     RECT  78.015 84.077 78.678 84.173 ;
     RECT  65.844 84.139 65.862 84.179 ;
     RECT  39.996 84.145 43.254 84.181 ;
     RECT  45.615 83.987 45.705 84.257 ;
     RECT  48.315 83.987 48.405 84.257 ;
     RECT  51.015 83.987 51.105 84.257 ;
     RECT  53.715 84.173 53.805 84.257 ;
     RECT  56.415 83.987 56.505 84.257 ;
     RECT  59.115 83.987 59.205 84.257 ;
     RECT  61.815 84.173 61.905 84.257 ;
     RECT  64.515 84.173 64.605 84.257 ;
     RECT  67.215 83.987 67.305 84.257 ;
     RECT  69.915 83.987 70.005 84.257 ;
     RECT  72.615 84.173 72.705 84.257 ;
     RECT  37.515 84.109 38.79 84.299 ;
     RECT  88.596 83.759 89.478 84.299 ;
     RECT  83.232 84.091 83.697 84.331 ;
     RECT  39.996 84.181 43.542 84.365 ;
     RECT  90.252 83.759 95.922 84.365 ;
     RECT  83.016 84.331 83.697 84.371 ;
     RECT  75.024 84.125 75.834 84.413 ;
     RECT  2.415 83.219 2.697 84.577 ;
     RECT  2.415 84.577 3.114 84.649 ;
     RECT  3.924 84.541 3.942 84.649 ;
     RECT  2.415 84.649 3.942 84.811 ;
     RECT  5.115 83.759 5.397 84.811 ;
     RECT  2.304 84.811 5.397 84.839 ;
     RECT  4.284 84.839 5.397 84.847 ;
     RECT  6.84 84.649 6.858 84.847 ;
     RECT  2.304 84.839 3.51 84.848 ;
     RECT  39.996 84.365 42.894 84.883 ;
     RECT  4.284 84.847 5.49 84.955 ;
     RECT  7.815 83.795 8.097 84.955 ;
     RECT  8.964 84.847 8.982 84.955 ;
     RECT  6.84 84.847 7.002 84.983 ;
     RECT  6.84 84.983 6.93 84.991 ;
     RECT  6.732 84.991 6.93 85.081 ;
     RECT  90.36 84.365 95.922 85.099 ;
     RECT  7.815 84.955 8.982 85.109 ;
     RECT  90.216 85.099 95.922 85.133 ;
     RECT  90.216 85.133 90.234 85.145 ;
     RECT  37.515 84.299 38.214 85.153 ;
     RECT  39.348 84.883 42.894 85.153 ;
     RECT  6.66 85.081 6.93 85.225 ;
     RECT  91.152 85.133 95.922 85.261 ;
     RECT  9.432 85.189 9.45 85.289 ;
     RECT  4.284 84.955 5.634 85.351 ;
     RECT  86.115 83.569 86.922 85.351 ;
     RECT  79.74 83.939 79.758 85.387 ;
     RECT  80.715 65.741 80.997 85.387 ;
     RECT  85.788 85.351 86.922 85.387 ;
     RECT  79.74 85.387 80.997 85.424 ;
     RECT  0.108 84.667 0.126 85.451 ;
     RECT  97.452 84.379 97.47 85.451 ;
     RECT  85.68 85.387 86.922 85.469 ;
     RECT  2.415 84.848 3.51 85.729 ;
     RECT  4.284 85.351 5.778 85.729 ;
     RECT  7.815 85.109 8.55 85.765 ;
     RECT  0.144 85.723 0.162 85.853 ;
     RECT  2.415 85.729 5.778 85.915 ;
     RECT  82.548 85.801 82.566 85.919 ;
     RECT  7.776 85.765 8.55 85.963 ;
     RECT  77.256 85.351 77.274 86.011 ;
     RECT  91.152 85.261 95.958 86.059 ;
     RECT  2.415 85.915 5.814 86.071 ;
     RECT  6.552 85.225 6.93 86.071 ;
     RECT  7.776 85.963 8.622 86.071 ;
     RECT  90.612 86.059 95.958 86.189 ;
     RECT  2.415 86.071 6.93 86.261 ;
     RECT  7.776 86.071 8.982 86.305 ;
     RECT  2.415 86.261 5.742 86.333 ;
     RECT  37.515 85.153 42.894 86.4 ;
     RECT  75.06 84.413 75.834 86.4 ;
     RECT  0.54 86.341 0.558 86.429 ;
     RECT  6.624 86.261 6.93 86.431 ;
     RECT  7.668 86.305 8.982 86.431 ;
     RECT  81.792 86.035 81.81 86.539 ;
     RECT  86.115 85.469 86.922 86.539 ;
     RECT  37.515 86.4 75.834 86.603 ;
     RECT  86.115 86.539 86.994 86.639 ;
     RECT  6.624 86.431 8.982 86.729 ;
     RECT  90.756 86.189 95.958 86.765 ;
     RECT  77.22 86.011 77.274 86.845 ;
     RECT  78.015 84.173 78.297 86.845 ;
     RECT  7.815 86.729 8.982 86.999 ;
     RECT  8.964 86.999 8.982 87.107 ;
     RECT  2.415 86.333 5.598 87.115 ;
     RECT  2.304 87.115 5.598 87.241 ;
     RECT  6.624 86.729 7.074 87.269 ;
     RECT  2.304 87.241 5.67 87.293 ;
     RECT  77.22 86.845 78.297 87.307 ;
     RECT  9.108 87.151 9.306 87.349 ;
     RECT  37.515 86.603 38.214 87.349 ;
     RECT  39.24 86.603 75.834 87.349 ;
     RECT  2.304 87.293 5.397 87.449 ;
     RECT  9.108 87.349 9.342 87.539 ;
     RECT  0.144 86.971 0.162 87.547 ;
     RECT  89.964 87.355 89.982 87.547 ;
     RECT  91.188 86.765 95.958 87.547 ;
     RECT  0.108 87.547 0.162 87.595 ;
     RECT  81.792 86.539 82.206 87.595 ;
     RECT  6.768 87.269 7.074 87.611 ;
     RECT  34.815 49.739 35.097 87.619 ;
     RECT  37.515 87.349 75.834 87.643 ;
     RECT  34.776 87.619 35.097 87.719 ;
     RECT  89.964 87.547 95.958 87.881 ;
     RECT  6.912 87.611 7.074 87.889 ;
     RECT  7.815 86.999 8.226 87.889 ;
     RECT  88.596 84.299 89.097 87.917 ;
     RECT  6.912 87.889 8.226 87.961 ;
     RECT  88.668 87.917 89.097 87.965 ;
     RECT  2.415 87.449 5.397 88.075 ;
     RECT  9.108 87.539 9.198 88.115 ;
     RECT  2.415 88.075 5.526 88.151 ;
     RECT  89.964 87.881 95.49 88.151 ;
     RECT  88.74 87.965 89.097 88.205 ;
     RECT  89.964 88.151 95.454 88.253 ;
     RECT  2.415 88.151 3.798 88.349 ;
     RECT  9.108 88.115 9.162 88.421 ;
     RECT  6.912 87.961 8.298 88.465 ;
     RECT  37.515 87.643 76.086 88.493 ;
     RECT  6.624 88.465 8.298 88.501 ;
     RECT  2.415 88.349 2.697 88.555 ;
     RECT  6.408 88.501 8.298 88.591 ;
     RECT  77.22 87.307 78.678 88.603 ;
     RECT  2.304 88.555 2.697 88.619 ;
     RECT  77.22 88.603 78.786 88.733 ;
     RECT  4.536 88.151 5.526 88.771 ;
     RECT  6.336 88.591 8.298 88.771 ;
     RECT  86.115 86.639 86.922 88.781 ;
     RECT  4.536 88.771 8.298 88.861 ;
     RECT  2.412 88.619 2.697 88.877 ;
     RECT  3.42 88.349 3.798 88.889 ;
     RECT  4.536 88.861 8.37 88.889 ;
     RECT  9.144 88.421 9.162 88.889 ;
     RECT  89.964 88.253 89.982 89.035 ;
     RECT  90.72 88.253 95.454 89.035 ;
     RECT  77.22 88.733 78.75 89.069 ;
     RECT  86.115 88.781 86.67 89.069 ;
     RECT  86.115 89.069 86.397 89.131 ;
     RECT  3.456 88.889 3.798 89.159 ;
     RECT  6.552 88.889 8.37 89.159 ;
     RECT  0.108 87.595 0.198 89.165 ;
     RECT  0.18 89.165 0.198 89.213 ;
     RECT  4.752 88.889 5.706 89.231 ;
     RECT  37.515 88.493 38.214 89.239 ;
     RECT  39.384 88.493 76.086 89.239 ;
     RECT  6.768 89.159 8.37 89.339 ;
     RECT  37.515 89.239 76.086 89.339 ;
     RECT  5.115 89.231 5.706 89.429 ;
     RECT  39.384 89.339 76.086 89.429 ;
     RECT  6.768 89.339 8.097 89.501 ;
     RECT  89.964 89.035 95.454 89.501 ;
     RECT  3.456 89.159 3.51 89.537 ;
     RECT  7.308 89.501 8.097 89.549 ;
     RECT  3.492 89.537 3.51 89.573 ;
     RECT  86.004 89.131 86.397 89.837 ;
     RECT  87.768 89.581 87.786 89.837 ;
     RECT  91.515 89.501 95.454 89.969 ;
     RECT  84.888 89.707 84.906 89.977 ;
     RECT  89.964 89.501 90.666 90.239 ;
     RECT  86.04 89.837 86.397 90.247 ;
     RECT  84.852 89.977 84.906 90.269 ;
     RECT  86.04 90.247 86.67 90.365 ;
     RECT  84.852 90.269 84.87 90.557 ;
     RECT  39.492 89.429 76.086 90.589 ;
     RECT  91.515 89.969 94.95 90.653 ;
     RECT  81.756 87.595 82.206 90.845 ;
     RECT  77.22 89.069 78.678 90.893 ;
     RECT  86.115 90.365 86.67 90.893 ;
     RECT  39.456 90.589 76.086 91.165 ;
     RECT  39.456 91.165 76.302 91.471 ;
     RECT  39.456 91.471 76.374 91.805 ;
     RECT  39.456 91.805 75.192 91.997 ;
     RECT  76.068 91.805 76.374 92.011 ;
     RECT  77.22 90.893 78.297 92.011 ;
     RECT  39.78 91.997 75.192 92.429 ;
     RECT  76.068 92.011 78.297 92.669 ;
     RECT  39.816 92.429 75.192 92.785 ;
     RECT  76.068 92.669 76.41 92.785 ;
     RECT  39.816 92.785 76.41 92.861 ;
     RECT  22.644 92.911 22.662 92.957 ;
     RECT  22.32 93.055 22.338 93.101 ;
     RECT  42.984 92.861 76.41 93.149 ;
     RECT  42.984 93.149 75.192 93.245 ;
     RECT  76.068 93.149 76.41 93.533 ;
     RECT  39.816 92.861 42.138 93.559 ;
     RECT  37.515 89.339 38.214 93.589 ;
     RECT  39.42 93.559 42.138 93.589 ;
     RECT  37.515 93.589 42.138 94.027 ;
     RECT  43.2 93.245 75.192 94.027 ;
     RECT  76.068 93.533 76.374 94.027 ;
     RECT  37.515 94.027 76.374 94.261 ;
     RECT  37.515 94.261 76.41 94.301 ;
     RECT  43.02 94.301 76.41 95.261 ;
     RECT  95.904 95.341 95.922 95.485 ;
     RECT  76.068 95.261 76.41 95.512 ;
     RECT  37.515 94.301 42.174 95.515 ;
     RECT  43.02 95.261 75.294 95.515 ;
     RECT  76.068 95.512 76.446 95.675 ;
     RECT  93.168 90.653 94.95 95.881 ;
     RECT  95.76 95.485 95.922 95.881 ;
     RECT  93.168 95.881 95.922 95.933 ;
     RECT  77.22 92.669 78.297 95.981 ;
     RECT  93.168 95.933 95.778 96.139 ;
     RECT  91.515 90.653 91.926 96.151 ;
     RECT  92.772 96.139 95.778 96.179 ;
     RECT  89.964 90.239 89.982 96.181 ;
     RECT  91.044 96.151 91.926 96.187 ;
     RECT  89.964 96.181 90.126 96.221 ;
     RECT  37.515 95.515 75.294 96.359 ;
     RECT  37.515 96.359 38.718 96.365 ;
     RECT  88.815 88.205 89.097 96.457 ;
     RECT  39.636 96.359 75.294 96.475 ;
     RECT  76.068 95.675 76.41 96.475 ;
     RECT  39.636 96.475 76.41 96.529 ;
     RECT  86.115 90.893 86.397 96.529 ;
     RECT  88.815 96.457 89.154 96.565 ;
     RECT  89.964 96.221 89.982 96.565 ;
     RECT  77.436 95.981 78.297 96.989 ;
     RECT  93.168 96.179 95.778 97.003 ;
     RECT  88.815 96.565 89.982 97.069 ;
     RECT  90.9 96.187 91.926 97.069 ;
     RECT  88.815 97.069 91.926 97.099 ;
     RECT  88.815 97.099 91.962 97.231 ;
     RECT  88.815 97.231 92.394 97.291 ;
     RECT  93.168 97.003 95.922 97.291 ;
     RECT  88.815 97.291 95.922 97.295 ;
     RECT  97.452 96.475 97.47 97.331 ;
     RECT  89.964 97.295 95.922 97.439 ;
     RECT  39.636 96.529 76.698 97.483 ;
     RECT  37.515 96.365 38.286 97.645 ;
     RECT  39.204 97.483 76.698 97.645 ;
     RECT  96.912 97.627 96.93 97.673 ;
     RECT  92.844 97.439 95.922 97.709 ;
     RECT  86.115 96.529 86.67 97.807 ;
     RECT  37.515 97.645 76.698 98.105 ;
     RECT  97.452 98.059 97.47 98.141 ;
     RECT  37.515 98.105 38.718 98.249 ;
     RECT  89.964 97.439 91.998 98.311 ;
     RECT  92.844 97.709 95.634 98.311 ;
     RECT  89.964 98.311 95.634 98.491 ;
     RECT  89.964 98.491 95.922 98.753 ;
     RECT  90.936 98.753 95.922 98.879 ;
     RECT  78.015 96.989 78.297 98.923 ;
     RECT  37.515 98.249 38.502 98.995 ;
     RECT  37.515 98.995 38.682 99.031 ;
     RECT  96.912 98.725 96.93 99.101 ;
     RECT  79.74 85.424 79.758 99.149 ;
     RECT  37.515 99.031 38.826 99.157 ;
     RECT  37.512 99.157 38.826 99.197 ;
     RECT  78.015 98.923 78.93 99.301 ;
     RECT  83.415 84.371 83.697 99.463 ;
     RECT  78.015 99.301 79.578 99.491 ;
     RECT  37.515 99.197 38.826 99.571 ;
     RECT  89.964 98.753 89.982 99.739 ;
     RECT  97.452 99.499 97.47 99.761 ;
     RECT  22.356 99.931 22.374 99.968 ;
     RECT  21.315 49.373 21.597 100.111 ;
     RECT  89.964 99.739 90.27 100.111 ;
     RECT  91.044 98.879 95.922 100.111 ;
     RECT  86.115 97.807 86.922 100.201 ;
     RECT  89.892 100.111 90.27 100.229 ;
     RECT  21.315 100.111 22.086 100.301 ;
     RECT  81.756 90.845 81.774 100.301 ;
     RECT  91.008 100.111 95.922 100.381 ;
     RECT  86.115 100.201 87.246 100.409 ;
     RECT  88.815 97.295 89.097 100.471 ;
     RECT  90.468 100.381 95.922 100.499 ;
     RECT  97.452 100.507 97.47 100.571 ;
     RECT  88.815 100.471 89.694 100.589 ;
     RECT  88.815 100.589 89.55 100.685 ;
     RECT  90.648 100.499 95.922 100.877 ;
     RECT  93.384 100.877 95.922 101.039 ;
     RECT  91.008 100.877 92.61 101.219 ;
     RECT  39.888 98.105 76.698 101.615 ;
     RECT  93.528 101.039 95.778 102.091 ;
     RECT  93.528 102.091 95.922 102.128 ;
     RECT  93.528 102.128 95.778 102.425 ;
     RECT  93.528 102.425 95.202 102.497 ;
     RECT  39.888 101.615 76.662 103.704 ;
     RECT  93.528 102.497 94.986 103.775 ;
     RECT  91.008 101.219 91.998 103.847 ;
     RECT  75.24 103.704 76.662 104.459 ;
     RECT  75.24 104.459 76.194 104.549 ;
     RECT  75.24 104.549 76.122 104.585 ;
     RECT  93.708 103.775 94.986 104.927 ;
     RECT  91.044 103.847 91.998 104.963 ;
     RECT  39.888 103.704 42.75 104.999 ;
     RECT  91.044 104.963 91.797 104.999 ;
     RECT  41.4 104.999 42.75 105.044 ;
     RECT  93.744 104.927 94.986 105.161 ;
     RECT  50.04 105.133 50.058 105.637 ;
     RECT  94.215 105.161 94.986 105.701 ;
     RECT  47.052 105.673 47.07 105.709 ;
     RECT  50.04 105.637 50.13 105.745 ;
     RECT  78.015 99.491 78.93 105.773 ;
     RECT  46.764 105.709 47.07 105.781 ;
     RECT  49.572 105.745 50.814 105.781 ;
     RECT  86.115 100.409 86.922 105.809 ;
     RECT  41.688 105.044 42.75 105.823 ;
     RECT  49.5 105.781 50.814 105.823 ;
     RECT  64.872 105.451 64.89 105.823 ;
     RECT  64.515 105.823 64.89 105.871 ;
     RECT  44.136 104.593 44.154 105.899 ;
     RECT  46.764 105.781 47.178 105.899 ;
     RECT  49.5 105.823 51.105 105.899 ;
     RECT  46.764 105.899 46.782 105.971 ;
     RECT  37.515 99.571 39.078 106.043 ;
     RECT  50.796 105.899 51.105 106.079 ;
     RECT  41.688 105.823 43.005 106.093 ;
     RECT  45.615 105.823 45.705 106.093 ;
     RECT  48.315 105.823 48.405 106.093 ;
     RECT  51.015 106.079 51.105 106.093 ;
     RECT  53.715 105.823 53.805 106.093 ;
     RECT  56.415 105.823 56.505 106.093 ;
     RECT  59.115 105.823 59.205 106.093 ;
     RECT  61.815 105.823 61.905 106.093 ;
     RECT  67.215 105.823 67.305 106.093 ;
     RECT  69.915 105.823 70.005 106.093 ;
     RECT  72.615 105.823 72.705 106.093 ;
     RECT  75.24 104.585 75.654 106.169 ;
     RECT  75.315 106.169 75.654 106.313 ;
     RECT  64.515 105.871 65.106 106.321 ;
     RECT  83.415 99.463 83.826 106.555 ;
     RECT  64.515 106.321 65.214 106.589 ;
     RECT  41.688 106.093 43.197 107.275 ;
     RECT  64.515 106.589 64.797 107.659 ;
     RECT  41.688 107.275 43.254 107.671 ;
     RECT  64.515 107.659 64.962 107.941 ;
     RECT  88.815 100.685 89.097 107.995 ;
     RECT  91.515 104.999 91.797 107.995 ;
     RECT  90.9 107.995 91.797 108.059 ;
     RECT  64.515 107.941 65.214 108.173 ;
     RECT  88.815 107.995 89.514 108.329 ;
     RECT  41.688 107.671 43.542 108.509 ;
     RECT  41.688 108.509 43.398 108.557 ;
     RECT  39.888 104.999 40.497 109.387 ;
     RECT  39.888 109.387 40.698 109.589 ;
     RECT  41.688 108.557 43.197 113.467 ;
     RECT  41.688 113.467 43.254 114.523 ;
     RECT  41.436 114.523 43.254 114.809 ;
     RECT  39.888 109.589 40.497 114.955 ;
     RECT  41.436 114.809 43.197 114.955 ;
     RECT  88.815 108.329 89.097 115.723 ;
     RECT  88.815 115.723 89.586 116.069 ;
     RECT  88.815 116.069 89.334 116.195 ;
     RECT  88.815 116.195 89.298 116.285 ;
     RECT  86.115 105.809 86.397 116.437 ;
     RECT  85.824 116.437 86.397 116.443 ;
     RECT  85.176 116.443 86.397 116.477 ;
     RECT  85.176 116.477 85.194 116.699 ;
     RECT  83.415 106.555 84.33 116.779 ;
     RECT  83.415 116.779 84.654 116.816 ;
     RECT  63.072 117.781 63.09 117.821 ;
     RECT  61.815 106.093 62.097 117.835 ;
     RECT  61.815 117.835 62.73 117.965 ;
     RECT  24.015 2.413 24.297 119.995 ;
     RECT  24.015 119.995 24.93 120.043 ;
     RECT  29.415 49.373 29.697 120.043 ;
     RECT  29.415 120.043 29.79 120.221 ;
     RECT  30.78 120.043 30.798 120.221 ;
     RECT  24.015 120.043 25.254 120.389 ;
     RECT  24.015 120.389 24.93 120.701 ;
     RECT  39.888 114.955 43.197 120.749 ;
     RECT  75.315 106.313 75.597 122.485 ;
     RECT  5.115 89.429 5.397 122.521 ;
     RECT  39.888 120.749 42.174 122.521 ;
     RECT  42.915 120.749 43.197 122.521 ;
     RECT  7.815 89.549 8.097 122.611 ;
     RECT  34.815 87.719 35.097 122.611 ;
     RECT  39.888 122.521 43.197 122.639 ;
     RECT  75.024 122.485 75.597 122.639 ;
     RECT  34.815 122.611 35.514 122.647 ;
     RECT  36.36 122.611 36.378 122.647 ;
     RECT  4.5 122.521 5.397 122.719 ;
     RECT  37.515 106.043 38.682 122.719 ;
     RECT  2.415 88.877 2.697 122.779 ;
     RECT  4.5 122.719 5.994 122.779 ;
     RECT  3.996 122.779 5.994 122.791 ;
     RECT  3.708 122.791 5.994 122.909 ;
     RECT  6.84 122.791 6.858 123.053 ;
     RECT  7.815 122.611 8.154 123.061 ;
     RECT  74.052 122.755 74.07 123.061 ;
     RECT  74.052 123.061 74.358 123.101 ;
     RECT  2.415 122.779 2.79 123.115 ;
     RECT  74.124 123.101 74.358 123.179 ;
     RECT  37.515 122.719 38.826 123.187 ;
     RECT  7.815 123.061 8.874 123.259 ;
     RECT  34.815 122.647 36.378 123.259 ;
     RECT  34.815 123.259 36.702 123.295 ;
     RECT  2.304 123.115 2.79 123.421 ;
     RECT  37.515 123.187 38.898 123.457 ;
     RECT  4.356 122.909 5.994 123.565 ;
     RECT  34.815 123.295 36.738 123.601 ;
     RECT  37.512 123.457 38.898 123.601 ;
     RECT  75.168 122.639 75.597 123.601 ;
     RECT  0.108 123.259 0.126 123.629 ;
     RECT  4.356 123.565 6.534 123.691 ;
     RECT  34.815 123.601 38.898 123.691 ;
     RECT  34.74 123.691 38.898 123.727 ;
     RECT  4.068 123.691 6.534 123.763 ;
     RECT  0.144 123.691 0.162 123.821 ;
     RECT  2.304 123.421 2.862 123.835 ;
     RECT  3.78 123.763 6.534 123.835 ;
     RECT  7.272 123.259 8.874 123.835 ;
     RECT  39.96 122.639 43.197 123.835 ;
     RECT  34.2 123.727 38.898 123.871 ;
     RECT  75.096 123.601 75.597 123.961 ;
     RECT  2.304 123.835 9.162 123.989 ;
     RECT  34.2 123.871 38.934 123.989 ;
     RECT  37.116 123.989 38.934 123.997 ;
     RECT  10.515 83.021 10.797 124.105 ;
     RECT  37.116 123.997 39.006 124.105 ;
     RECT  39.924 123.835 43.197 124.105 ;
     RECT  78.015 105.773 78.297 124.141 ;
     RECT  2.304 123.989 8.478 124.169 ;
     RECT  74.124 123.179 74.142 124.231 ;
     RECT  75.06 123.961 75.597 124.231 ;
     RECT  10.515 124.105 10.818 124.259 ;
     RECT  2.304 124.169 8.406 124.405 ;
     RECT  74.124 124.231 75.597 124.411 ;
     RECT  2.268 124.405 8.406 124.445 ;
     RECT  94.215 105.701 94.497 124.501 ;
     RECT  74.124 124.411 75.834 124.537 ;
     RECT  94.215 124.501 95.742 124.645 ;
     RECT  34.2 123.989 36.378 124.709 ;
     RECT  94.215 124.645 95.778 124.747 ;
     RECT  34.776 124.709 36.378 124.795 ;
     RECT  37.116 124.105 43.197 124.795 ;
     RECT  74.052 124.537 75.834 124.795 ;
     RECT  34.776 124.795 43.197 124.799 ;
     RECT  94.215 124.747 95.922 124.799 ;
     RECT  72.615 106.093 72.897 124.807 ;
     RECT  73.908 124.795 75.834 124.807 ;
     RECT  2.415 124.445 8.406 124.835 ;
     RECT  9.36 124.537 9.378 124.835 ;
     RECT  72.615 124.807 75.834 124.835 ;
     RECT  94.215 124.799 95.778 124.835 ;
     RECT  32.115 2.413 32.397 124.879 ;
     RECT  32.115 124.879 33.102 124.951 ;
     RECT  74.412 124.835 75.834 124.951 ;
     RECT  32.115 124.951 33.174 124.979 ;
     RECT  74.412 124.951 75.906 125.041 ;
     RECT  0.144 124.699 0.162 125.117 ;
     RECT  33.12 124.979 33.174 125.149 ;
     RECT  94.215 124.835 95.742 125.221 ;
     RECT  33.12 125.149 33.246 125.249 ;
     RECT  88.815 116.285 89.097 125.275 ;
     RECT  74.412 125.041 76.05 125.375 ;
     RECT  2.415 124.835 4.05 125.383 ;
     RECT  93.132 125.221 95.742 125.419 ;
     RECT  1.728 125.383 4.05 125.597 ;
     RECT  91.515 108.059 91.797 125.608 ;
     RECT  92.88 125.419 95.742 125.609 ;
     RECT  91.188 125.608 91.797 125.645 ;
     RECT  83.415 116.816 84.402 125.707 ;
     RECT  86.04 116.477 86.397 125.707 ;
     RECT  2.415 125.597 4.05 125.725 ;
     RECT  2.415 125.725 4.266 125.761 ;
     RECT  5.076 124.835 8.406 125.761 ;
     RECT  88.524 125.275 89.097 125.761 ;
     RECT  90.072 125.491 90.09 125.761 ;
     RECT  93.564 125.609 95.742 125.761 ;
     RECT  93.564 125.761 95.778 125.837 ;
     RECT  80.715 85.424 80.997 125.851 ;
     RECT  88.524 125.761 90.09 125.851 ;
     RECT  9.36 125.581 9.378 125.879 ;
     RECT  72.615 124.835 73.494 125.947 ;
     RECT  72.615 125.947 73.71 125.981 ;
     RECT  80.28 125.851 80.997 125.981 ;
     RECT  32.115 124.979 32.397 125.995 ;
     RECT  33.12 125.249 33.138 125.995 ;
     RECT  34.815 124.799 43.197 125.995 ;
     RECT  88.524 125.851 90.306 126.029 ;
     RECT  91.296 125.645 91.797 126.031 ;
     RECT  92.52 125.761 92.538 126.031 ;
     RECT  73.692 125.981 73.71 126.121 ;
     RECT  74.52 125.375 76.05 126.121 ;
     RECT  32.115 125.995 33.138 126.149 ;
     RECT  86.04 125.707 86.634 126.157 ;
     RECT  83.124 125.707 84.402 126.185 ;
     RECT  0.108 126.139 0.126 126.187 ;
     RECT  2.415 125.761 8.586 126.193 ;
     RECT  30.78 125.221 30.798 126.229 ;
     RECT  73.692 126.121 76.05 126.301 ;
     RECT  0.108 126.187 0.198 126.317 ;
     RECT  0.108 126.317 0.126 126.329 ;
     RECT  30.78 126.229 30.87 126.329 ;
     RECT  85.788 126.157 86.67 126.329 ;
     RECT  45.615 106.093 45.897 126.391 ;
     RECT  73.692 126.301 76.086 126.391 ;
     RECT  88.815 126.029 90.306 126.391 ;
     RECT  91.296 126.031 92.538 126.391 ;
     RECT  2.415 126.193 8.622 126.419 ;
     RECT  33.12 126.149 33.138 126.419 ;
     RECT  56.415 106.093 56.697 126.427 ;
     RECT  45.288 126.391 45.897 126.461 ;
     RECT  77.364 124.141 78.297 126.463 ;
     RECT  2.415 126.419 8.37 126.491 ;
     RECT  45.576 126.461 45.897 126.509 ;
     RECT  88.815 126.391 92.826 126.509 ;
     RECT  77.328 126.463 78.297 126.523 ;
     RECT  91.515 126.509 92.826 126.523 ;
     RECT  93.564 125.837 95.742 126.523 ;
     RECT  77.328 126.523 78.678 126.535 ;
     RECT  2.415 126.491 8.226 126.557 ;
     RECT  73.692 126.391 76.374 126.661 ;
     RECT  77.292 126.535 78.678 126.661 ;
     RECT  45.615 126.509 45.897 126.667 ;
     RECT  53.715 106.093 53.997 126.667 ;
     RECT  88.815 126.509 90.666 126.701 ;
     RECT  73.692 126.661 78.678 126.749 ;
     RECT  1.152 125.851 1.17 126.797 ;
     RECT  45.615 126.667 45.99 126.797 ;
     RECT  46.764 126.667 46.782 126.797 ;
     RECT  53.715 126.667 54.09 126.797 ;
     RECT  76.968 126.749 78.678 126.797 ;
     RECT  90.252 126.701 90.666 126.797 ;
     RECT  34.812 125.995 43.197 126.805 ;
     RECT  56.415 126.427 56.898 126.841 ;
     RECT  91.515 126.523 95.742 126.841 ;
     RECT  2.415 126.557 2.697 126.859 ;
     RECT  91.515 126.841 95.778 126.859 ;
     RECT  3.996 126.557 8.226 126.869 ;
     RECT  56.415 126.841 57.006 126.931 ;
     RECT  91.515 126.859 95.922 126.959 ;
     RECT  4.284 126.869 8.226 126.995 ;
     RECT  34.74 126.805 43.197 126.995 ;
     RECT  83.415 126.185 84.402 127.003 ;
     RECT  4.5 126.995 8.226 127.037 ;
     RECT  90.252 126.797 90.27 127.037 ;
     RECT  61.815 117.965 62.097 127.039 ;
     RECT  72.615 125.981 72.897 127.075 ;
     RECT  73.692 126.749 76.23 127.075 ;
     RECT  69.915 106.093 70.197 127.111 ;
     RECT  61.815 127.039 62.262 127.139 ;
     RECT  93.636 126.959 95.922 127.139 ;
     RECT  34.815 126.995 43.197 127.187 ;
     RECT  45.615 126.797 45.897 127.187 ;
     RECT  48.315 106.093 48.597 127.187 ;
     RECT  51.015 106.093 51.297 127.187 ;
     RECT  53.715 126.797 53.997 127.187 ;
     RECT  59.115 106.093 59.397 127.187 ;
     RECT  64.515 108.173 64.797 127.187 ;
     RECT  67.215 106.093 67.497 127.187 ;
     RECT  55.944 126.931 57.006 127.229 ;
     RECT  82.98 127.003 84.402 127.265 ;
     RECT  51.015 127.187 51.105 127.273 ;
     RECT  4.5 127.037 5.526 127.277 ;
     RECT  61.815 127.139 62.19 127.277 ;
     RECT  63.612 127.201 63.63 127.277 ;
     RECT  72.615 127.075 76.23 127.277 ;
     RECT  83.088 127.265 84.402 127.277 ;
     RECT  88.815 126.701 89.478 127.277 ;
     RECT  91.515 126.959 92.07 127.277 ;
     RECT  0.108 127.147 0.126 127.325 ;
     RECT  50.724 127.273 51.105 127.373 ;
     RECT  56.052 127.229 56.97 127.373 ;
     RECT  69.915 127.111 70.722 127.373 ;
     RECT  74.052 127.277 76.23 127.373 ;
     RECT  2.304 126.859 2.697 127.409 ;
     RECT  5.076 127.277 5.526 127.409 ;
     RECT  30.852 127.111 30.87 127.409 ;
     RECT  74.052 127.373 74.07 127.409 ;
     RECT  45.615 127.187 45.705 127.457 ;
     RECT  48.315 127.187 48.405 127.457 ;
     RECT  51.015 127.373 51.105 127.457 ;
     RECT  53.715 127.187 53.805 127.457 ;
     RECT  56.415 127.373 56.505 127.457 ;
     RECT  59.115 127.187 59.205 127.457 ;
     RECT  61.815 127.277 61.905 127.457 ;
     RECT  64.515 127.187 64.605 127.457 ;
     RECT  67.215 127.187 67.305 127.457 ;
     RECT  69.915 127.373 70.005 127.457 ;
     RECT  72.615 127.277 72.705 127.457 ;
     RECT  6.372 127.037 8.154 127.499 ;
     RECT  32.115 126.149 32.397 127.507 ;
     RECT  54.72 127.345 54.738 127.607 ;
     RECT  6.624 127.499 8.154 127.643 ;
     RECT  32.115 127.507 33.102 127.643 ;
     RECT  85.788 126.329 86.397 127.651 ;
     RECT  6.624 127.643 8.097 127.661 ;
     RECT  5.115 127.409 5.526 127.679 ;
     RECT  6.624 127.661 6.642 127.679 ;
     RECT  34.815 127.187 43.11 127.679 ;
     RECT  83.415 127.277 84.402 127.679 ;
     RECT  91.515 127.277 91.962 127.709 ;
     RECT  93.672 127.139 95.922 127.805 ;
     RECT  93.672 127.805 95.022 127.877 ;
     RECT  34.815 127.679 43.074 127.921 ;
     RECT  93.672 127.877 94.986 127.921 ;
     RECT  93.6 127.921 94.986 127.949 ;
     RECT  92.808 126.959 92.826 128.251 ;
     RECT  93.6 127.949 94.554 128.251 ;
     RECT  95.76 127.805 95.922 128.333 ;
     RECT  95.76 128.333 95.778 128.345 ;
     RECT  34.74 127.921 43.074 128.461 ;
     RECT  34.452 128.461 43.074 128.621 ;
     RECT  92.808 128.251 94.554 128.765 ;
     RECT  92.808 128.765 93.15 128.885 ;
     RECT  93.888 128.765 94.554 128.885 ;
     RECT  74.988 127.373 76.23 129.199 ;
     RECT  76.968 126.797 78.297 129.199 ;
     RECT  92.988 128.885 93.15 129.389 ;
     RECT  93.996 128.885 94.554 129.389 ;
     RECT  34.815 128.621 43.074 129.451 ;
     RECT  34.815 129.451 43.11 129.6 ;
     RECT  74.988 129.199 78.297 129.6 ;
     RECT  94.104 129.389 94.554 129.787 ;
     RECT  5.115 127.679 5.397 129.811 ;
     RECT  34.815 129.6 78.297 129.965 ;
     RECT  4.176 129.811 6.066 129.973 ;
     RECT  94.104 129.787 94.662 129.979 ;
     RECT  2.415 127.409 2.697 130.027 ;
     RECT  94.104 129.979 94.77 130.115 ;
     RECT  4.176 129.973 6.282 130.279 ;
     RECT  30.78 130.081 30.798 130.279 ;
     RECT  2.268 130.027 2.697 130.315 ;
     RECT  3.42 129.541 3.438 130.315 ;
     RECT  83.415 127.679 83.697 130.315 ;
     RECT  2.268 130.315 3.438 130.351 ;
     RECT  4.176 130.279 6.714 130.351 ;
     RECT  7.815 127.661 8.097 130.351 ;
     RECT  94.215 130.115 94.77 130.351 ;
     RECT  30.78 130.279 30.87 130.379 ;
     RECT  2.268 130.351 6.714 130.397 ;
     RECT  9.072 130.171 9.09 130.469 ;
     RECT  2.268 130.397 2.697 130.513 ;
     RECT  91.515 127.709 91.797 130.513 ;
     RECT  92.988 129.389 93.006 130.555 ;
     RECT  76.896 129.965 78.297 130.603 ;
     RECT  85.752 127.651 86.397 130.603 ;
     RECT  3.456 130.397 6.714 130.621 ;
     RECT  7.815 130.351 8.298 130.621 ;
     RECT  1.728 130.513 2.697 130.637 ;
     RECT  90.684 129.271 90.702 130.711 ;
     RECT  91.476 130.513 91.797 130.711 ;
     RECT  76.896 130.603 78.894 130.781 ;
     RECT  85.752 130.603 86.778 130.781 ;
     RECT  80.715 125.981 80.997 130.891 ;
     RECT  92.916 130.555 93.042 130.891 ;
     RECT  82.656 130.459 82.674 130.919 ;
     RECT  2.268 130.637 2.697 130.925 ;
     RECT  83.415 130.315 83.826 130.939 ;
     RECT  80.715 130.891 81.09 130.973 ;
     RECT  82.764 130.939 83.826 130.981 ;
     RECT  82.764 130.981 84.402 131.035 ;
     RECT  85.752 130.781 86.67 131.053 ;
     RECT  94.215 130.351 94.842 131.053 ;
     RECT  76.896 130.781 78.786 131.069 ;
     RECT  82.764 131.035 84.51 131.081 ;
     RECT  90.684 130.711 91.797 131.083 ;
     RECT  92.628 130.891 93.114 131.083 ;
     RECT  93.852 131.053 94.842 131.083 ;
     RECT  3.456 130.621 8.298 131.117 ;
     RECT  82.764 131.081 84.33 131.117 ;
     RECT  0.144 131.083 0.162 131.213 ;
     RECT  2.415 130.925 2.697 131.227 ;
     RECT  3.456 131.117 5.454 131.227 ;
     RECT  90.432 131.083 94.842 131.279 ;
     RECT  34.815 129.965 76.158 131.431 ;
     RECT  76.896 131.069 78.678 131.453 ;
     RECT  85.5 131.053 86.67 131.459 ;
     RECT  6.192 131.117 8.298 131.521 ;
     RECT  6.192 131.521 8.766 131.549 ;
     RECT  30.78 131.431 30.798 131.549 ;
     RECT  90.684 131.279 94.842 131.549 ;
     RECT  76.896 131.453 78.39 131.621 ;
     RECT  93.816 131.549 94.842 131.621 ;
     RECT  93.852 131.621 94.842 131.629 ;
     RECT  6.48 131.549 8.766 131.657 ;
     RECT  34.812 131.431 76.158 131.659 ;
     RECT  2.415 131.227 5.454 131.693 ;
     RECT  6.48 131.657 8.37 131.693 ;
     RECT  3.528 131.693 5.454 131.729 ;
     RECT  4.68 131.729 5.454 131.819 ;
     RECT  6.48 131.693 6.606 131.819 ;
     RECT  4.68 131.819 5.397 131.855 ;
     RECT  90.684 131.549 93.006 131.933 ;
     RECT  85.5 131.459 86.634 131.981 ;
     RECT  0.108 131.755 0.126 131.999 ;
     RECT  7.488 131.693 8.37 131.999 ;
     RECT  4.824 131.855 5.397 132.125 ;
     RECT  34.74 131.659 76.158 132.331 ;
     RECT  76.896 131.621 78.297 132.331 ;
     RECT  34.74 132.331 78.297 132.509 ;
     RECT  32.115 127.643 32.397 132.511 ;
     RECT  3.528 131.729 3.762 132.539 ;
     RECT  3.744 132.539 3.762 132.737 ;
     RECT  77.328 132.509 78.297 132.781 ;
     RECT  30.78 132.709 30.798 132.809 ;
     RECT  77.328 132.781 78.498 132.893 ;
     RECT  77.436 132.893 78.498 132.899 ;
     RECT  77.58 132.899 78.498 133.051 ;
     RECT  32.115 132.511 32.526 133.079 ;
     RECT  77.58 133.051 78.642 133.169 ;
     RECT  7.815 131.999 8.37 133.277 ;
     RECT  34.74 132.509 76.41 133.469 ;
     RECT  77.58 133.169 78.297 133.627 ;
     RECT  34.74 133.469 75.978 133.861 ;
     RECT  77.472 133.627 78.297 133.979 ;
     RECT  34.704 133.861 75.978 134.131 ;
     RECT  34.416 134.131 75.978 134.285 ;
     RECT  34.815 134.285 75.978 134.365 ;
     RECT  77.544 133.979 78.297 134.401 ;
     RECT  93.852 131.629 95.202 134.527 ;
     RECT  93.852 134.527 95.274 134.555 ;
     RECT  77.544 134.401 78.354 134.789 ;
     RECT  34.815 134.365 76.374 135.005 ;
     RECT  34.815 135.005 42.354 135.163 ;
     RECT  34.668 135.163 42.354 135.293 ;
     RECT  34.668 135.293 41.31 135.329 ;
     RECT  43.2 135.005 76.374 135.355 ;
     RECT  42.336 135.293 42.354 135.389 ;
     RECT  77.544 134.789 78.297 135.571 ;
     RECT  77.436 135.571 78.297 135.779 ;
     RECT  77.58 135.779 78.297 136.061 ;
     RECT  77.688 136.061 78.297 136.175 ;
     RECT  34.815 135.329 41.31 136.291 ;
     RECT  34.74 136.291 41.31 136.409 ;
     RECT  43.2 135.355 76.41 136.759 ;
     RECT  77.724 136.175 78.297 137.065 ;
     RECT  42.732 136.759 76.41 137.309 ;
     RECT  34.815 136.409 41.31 137.467 ;
     RECT  43.056 137.309 76.41 137.501 ;
     RECT  34.815 137.467 41.67 137.563 ;
     RECT  77.58 137.065 78.297 137.795 ;
     RECT  34.815 137.563 41.994 137.851 ;
     RECT  34.812 137.851 41.994 137.867 ;
     RECT  34.812 137.867 41.022 137.903 ;
     RECT  34.815 137.903 41.022 138.077 ;
     RECT  41.76 137.867 41.994 138.139 ;
     RECT  41.76 138.139 42.174 138.371 ;
     RECT  90.684 131.933 91.797 138.541 ;
     RECT  92.556 131.933 93.006 138.541 ;
     RECT  43.056 137.501 75.192 138.619 ;
     RECT  41.796 138.371 42.174 138.641 ;
     RECT  85.5 131.981 86.397 138.667 ;
     RECT  87.552 138.571 87.57 138.667 ;
     RECT  95.256 134.555 95.274 138.685 ;
     RECT  76.392 137.501 76.41 138.712 ;
     RECT  76.392 138.712 76.446 138.713 ;
     RECT  90.684 138.541 93.006 138.721 ;
     RECT  93.852 134.555 94.497 138.721 ;
     RECT  95.256 138.685 95.778 138.721 ;
     RECT  85.5 138.667 87.57 138.839 ;
     RECT  90.684 138.721 94.497 138.847 ;
     RECT  76.428 138.713 76.446 138.875 ;
     RECT  90.648 138.847 94.497 138.991 ;
     RECT  95.256 138.721 95.922 138.991 ;
     RECT  41.868 138.641 42.174 139.003 ;
     RECT  43.02 138.619 75.192 139.003 ;
     RECT  90.648 138.991 95.922 139.019 ;
     RECT  77.616 137.795 78.297 139.081 ;
     RECT  90.684 139.019 95.922 139.109 ;
     RECT  77.436 139.081 78.297 139.189 ;
     RECT  88.815 127.277 89.097 139.243 ;
     RECT  88.815 139.243 89.766 139.261 ;
     RECT  88.815 139.261 89.91 139.289 ;
     RECT  90.828 139.109 95.922 139.373 ;
     RECT  89.892 139.289 89.91 139.379 ;
     RECT  41.868 139.003 75.192 139.483 ;
     RECT  77.292 139.189 78.297 139.495 ;
     RECT  90.828 139.373 95.742 139.559 ;
     RECT  34.815 138.077 40.95 139.729 ;
     RECT  41.868 139.483 76.374 139.729 ;
     RECT  34.815 139.729 76.374 139.771 ;
     RECT  90.828 139.559 95.706 139.891 ;
     RECT  87.552 138.839 87.57 139.915 ;
     RECT  87.408 139.915 87.57 139.927 ;
     RECT  97.452 139.819 97.47 139.991 ;
     RECT  82.656 139.927 82.674 140.027 ;
     RECT  87.408 139.927 87.642 140.071 ;
     RECT  34.815 139.771 76.41 140.161 ;
     RECT  77.22 139.495 78.297 140.161 ;
     RECT  87.408 140.071 87.714 140.189 ;
     RECT  87.696 140.189 87.714 140.237 ;
     RECT  90.684 139.891 95.706 140.299 ;
     RECT  90.684 140.299 95.742 140.341 ;
     RECT  90.648 140.341 95.742 140.683 ;
     RECT  89.892 140.539 89.91 140.845 ;
     RECT  90.648 140.683 95.778 140.845 ;
     RECT  88.815 139.289 89.097 140.971 ;
     RECT  89.892 140.845 95.778 140.971 ;
     RECT  85.5 138.839 86.397 141.007 ;
     RECT  88.815 140.971 95.922 141.053 ;
     RECT  85.5 141.007 86.706 141.143 ;
     RECT  88.815 141.053 95.742 141.269 ;
     RECT  34.815 140.161 78.297 141.305 ;
     RECT  88.815 141.269 95.67 141.305 ;
     RECT  36.18 141.305 78.297 141.413 ;
     RECT  36.324 141.413 78.297 141.539 ;
     RECT  88.815 141.305 95.634 141.575 ;
     RECT  36.324 141.539 36.486 141.809 ;
     RECT  36.324 141.809 36.342 141.845 ;
     RECT  97.452 141.691 97.47 141.881 ;
     RECT  89.964 141.575 95.634 141.917 ;
     RECT  90.108 141.917 95.634 142.051 ;
     RECT  37.332 141.539 78.297 142.079 ;
     RECT  90.108 142.051 95.742 142.312 ;
     RECT  90.108 142.312 95.922 142.385 ;
     RECT  37.476 142.079 78.297 142.529 ;
     RECT  90.216 142.385 95.922 143.195 ;
     RECT  85.5 141.143 86.397 143.203 ;
     RECT  85.5 143.203 86.67 143.231 ;
     RECT  86.115 143.231 86.67 143.339 ;
     RECT  90.36 143.195 95.922 143.609 ;
     RECT  37.515 142.529 78.297 143.735 ;
     RECT  93.528 143.609 95.814 143.969 ;
     RECT  37.515 143.735 75.33 144.125 ;
     RECT  93.528 143.969 95.274 144.149 ;
     RECT  38.628 144.125 75.33 144.419 ;
     RECT  38.664 144.419 75.33 144.509 ;
     RECT  38.736 144.509 75.33 145.561 ;
     RECT  37.515 144.125 37.797 145.741 ;
     RECT  38.664 145.561 75.33 145.741 ;
     RECT  37.515 145.741 75.33 146.477 ;
     RECT  38.664 146.477 75.33 146.482 ;
     RECT  38.664 146.482 75.294 146.813 ;
     RECT  38.736 146.813 75.294 146.904 ;
     RECT  93.528 144.149 95.238 147.119 ;
     RECT  38.736 146.904 43.146 147.589 ;
     RECT  37.515 146.477 37.797 147.643 ;
     RECT  90.36 143.609 92.79 147.659 ;
     RECT  90.36 147.659 92.538 147.785 ;
     RECT  38.7 147.589 43.146 147.821 ;
     RECT  90.36 147.785 91.797 147.821 ;
     RECT  91.116 147.821 91.797 147.857 ;
     RECT  93.528 147.119 94.734 147.857 ;
     RECT  37.515 147.643 37.89 147.901 ;
     RECT  38.7 147.821 41.418 147.901 ;
     RECT  37.515 147.901 41.418 148.199 ;
     RECT  94.215 147.857 94.734 148.289 ;
     RECT  38.7 148.199 41.418 148.325 ;
     RECT  92.52 147.785 92.538 148.325 ;
     RECT  38.7 148.325 40.95 148.361 ;
     RECT  76.068 143.735 78.297 148.361 ;
     RECT  77.328 148.361 78.297 148.469 ;
     RECT  76.068 148.361 76.086 148.514 ;
     RECT  38.7 148.361 40.497 148.877 ;
     RECT  48.132 148.441 48.15 148.909 ;
     RECT  49.536 148.486 49.554 148.945 ;
     RECT  50.544 148.837 50.562 148.945 ;
     RECT  42.696 147.821 43.146 149.009 ;
     RECT  74.664 146.904 75.294 149.009 ;
     RECT  48.132 148.909 48.258 149.023 ;
     RECT  49.536 148.945 50.562 149.023 ;
     RECT  75.168 149.009 75.294 149.023 ;
     RECT  48.132 149.023 48.405 149.099 ;
     RECT  49.536 149.023 51.105 149.099 ;
     RECT  90.36 147.821 90.378 149.099 ;
     RECT  75.168 149.023 75.405 149.135 ;
     RECT  50.724 149.099 51.105 149.171 ;
     RECT  42.915 149.009 43.146 149.293 ;
     RECT  45.615 149.023 45.705 149.293 ;
     RECT  48.315 149.099 48.405 149.293 ;
     RECT  51.015 149.171 51.105 149.293 ;
     RECT  53.715 149.023 53.805 149.293 ;
     RECT  56.415 149.023 56.505 149.293 ;
     RECT  59.115 149.023 59.205 149.293 ;
     RECT  61.815 149.023 61.905 149.293 ;
     RECT  64.515 149.023 64.605 149.293 ;
     RECT  67.215 149.023 67.305 149.293 ;
     RECT  69.915 149.023 70.005 149.293 ;
     RECT  72.615 149.023 72.705 149.293 ;
     RECT  75.315 149.135 75.405 149.293 ;
     RECT  38.736 148.877 40.497 149.899 ;
     RECT  37.515 148.199 37.797 151.051 ;
     RECT  38.52 149.899 40.497 151.051 ;
     RECT  37.515 151.051 40.497 151.259 ;
     RECT  37.515 151.259 37.998 151.421 ;
     RECT  37.515 151.421 37.797 155.611 ;
     RECT  38.736 151.259 40.497 155.611 ;
     RECT  37.515 155.611 40.497 156.119 ;
     RECT  37.515 156.119 37.998 156.173 ;
     RECT  37.515 156.173 37.797 160.747 ;
     RECT  38.736 156.119 40.497 160.747 ;
     RECT  37.515 160.747 40.497 160.979 ;
     RECT  37.515 160.979 37.998 161.069 ;
     RECT  38.736 160.979 40.497 162.985 ;
     RECT  38.7 162.985 40.497 163.147 ;
     RECT  37.515 161.069 37.797 163.831 ;
     RECT  38.52 163.147 40.497 163.831 ;
     RECT  37.515 163.831 40.497 164.291 ;
     RECT  37.515 164.291 37.797 165.145 ;
     RECT  38.736 164.291 40.497 165.145 ;
     RECT  37.515 165.145 40.497 167.801 ;
     RECT  40.032 167.801 40.497 167.873 ;
     RECT  37.515 167.801 39.114 167.999 ;
     RECT  2.415 131.693 2.697 168.227 ;
     RECT  5.115 132.125 5.397 168.227 ;
     RECT  7.815 133.277 8.097 168.227 ;
     RECT  10.515 124.259 10.797 168.227 ;
     RECT  13.215 73.229 13.497 168.227 ;
     RECT  15.915 2.413 16.197 168.227 ;
     RECT  18.615 2.413 18.897 168.227 ;
     RECT  21.315 100.301 21.597 168.227 ;
     RECT  24.015 120.701 24.297 168.227 ;
     RECT  26.715 2.413 26.997 168.227 ;
     RECT  29.415 120.221 29.697 168.227 ;
     RECT  32.115 133.079 32.397 168.227 ;
     RECT  34.815 141.305 35.097 168.227 ;
     RECT  40.215 167.873 40.497 168.227 ;
     RECT  42.915 149.293 43.197 168.227 ;
     RECT  45.615 149.293 45.897 168.227 ;
     RECT  48.315 149.293 48.597 168.227 ;
     RECT  51.015 149.293 51.297 168.227 ;
     RECT  53.715 149.293 53.997 168.227 ;
     RECT  56.415 149.293 56.697 168.227 ;
     RECT  59.115 149.293 59.397 168.227 ;
     RECT  61.815 149.293 62.097 168.227 ;
     RECT  64.515 149.293 64.797 168.227 ;
     RECT  67.215 149.293 67.497 168.227 ;
     RECT  69.915 149.293 70.197 168.227 ;
     RECT  72.615 149.293 72.897 168.227 ;
     RECT  75.315 149.293 75.597 168.227 ;
     RECT  78.015 148.469 78.297 168.227 ;
     RECT  80.715 130.973 80.997 168.227 ;
     RECT  83.415 131.117 83.697 168.227 ;
     RECT  86.115 143.339 86.397 168.227 ;
     RECT  88.815 141.575 89.097 168.227 ;
     RECT  91.515 147.857 91.797 168.227 ;
     RECT  94.215 148.289 94.497 168.227 ;
     RECT  2.415 168.227 2.505 168.497 ;
     RECT  5.115 168.227 5.205 168.497 ;
     RECT  7.815 168.227 7.905 168.497 ;
     RECT  10.515 168.227 10.605 168.497 ;
     RECT  13.215 168.227 13.305 168.497 ;
     RECT  15.915 168.227 16.005 168.497 ;
     RECT  18.615 168.227 18.705 168.497 ;
     RECT  21.315 168.227 21.405 168.497 ;
     RECT  24.015 168.227 24.105 168.497 ;
     RECT  26.715 168.227 26.805 168.497 ;
     RECT  29.415 168.227 29.505 168.497 ;
     RECT  32.115 168.227 32.205 168.497 ;
     RECT  34.815 168.227 34.905 168.497 ;
     RECT  37.515 167.999 39.006 168.497 ;
     RECT  40.215 168.227 40.305 168.497 ;
     RECT  42.915 168.227 43.005 168.497 ;
     RECT  45.615 168.227 45.705 168.497 ;
     RECT  48.315 168.227 48.405 168.497 ;
     RECT  51.015 168.227 51.105 168.497 ;
     RECT  53.715 168.227 53.805 168.497 ;
     RECT  56.415 168.227 56.505 168.497 ;
     RECT  59.115 168.227 59.205 168.497 ;
     RECT  61.815 168.227 61.905 168.497 ;
     RECT  64.515 168.227 64.605 168.497 ;
     RECT  67.215 168.227 67.305 168.497 ;
     RECT  69.915 168.227 70.005 168.497 ;
     RECT  72.615 168.227 72.705 168.497 ;
     RECT  75.315 168.227 75.405 168.497 ;
     RECT  78.015 168.227 78.105 168.497 ;
     RECT  80.715 168.227 80.805 168.497 ;
     RECT  83.415 168.227 83.505 168.497 ;
     RECT  86.115 168.227 86.205 168.497 ;
     RECT  88.815 168.227 88.905 168.497 ;
     RECT  91.515 168.227 91.605 168.497 ;
     RECT  94.215 168.227 94.305 168.497 ;
     RECT  38.124 168.497 39.006 170.395 ;
     RECT  37.836 170.395 39.006 170.609 ;
     RECT  37.908 170.609 39.006 170.621 ;
    LAYER M4 ;
     RECT  0.06 31.68 0.097 36.168 ;
     RECT  0.06 122.688 0.097 127.176 ;
     RECT  0.06 78.912 0.137 83.4 ;
     RECT  0.06 84.672 0.137 89.16 ;
     RECT  0.06 130.032 0.137 131.784 ;
     RECT  0.137 84.816 0.169 89.16 ;
     RECT  0.06 40.896 0.173 45.384 ;
     RECT  0.097 31.68 2.408 36.264 ;
     RECT  0.173 40.896 2.408 45.288 ;
     RECT  0.137 79.056 2.408 83.4 ;
     RECT  0.169 84.816 2.408 89.208 ;
     RECT  0.097 122.688 2.408 127.32 ;
     RECT  0.137 130.032 2.408 131.64 ;
     RECT  2.408 2.148 2.512 168.492 ;
     RECT  2.512 2.418 2.704 168.222 ;
     RECT  2.704 84.768 3.197 89.208 ;
     RECT  2.704 31.68 3.449 36.264 ;
     RECT  3.449 31.728 4.025 36.264 ;
     RECT  4.025 31.728 5.108 36.024 ;
     RECT  2.704 40.56 5.108 45.288 ;
     RECT  2.704 79.152 5.108 83.784 ;
     RECT  3.197 84.816 5.108 89.208 ;
     RECT  2.704 122.688 5.108 127.32 ;
     RECT  2.704 130.176 5.108 131.688 ;
     RECT  5.108 2.148 5.212 168.492 ;
     RECT  5.212 2.418 5.404 168.222 ;
     RECT  5.404 31.968 5.465 33.912 ;
     RECT  5.404 79.056 5.465 89.016 ;
     RECT  5.465 79.056 5.501 86.28 ;
     RECT  5.465 31.968 5.537 33.288 ;
     RECT  5.465 87.264 5.537 89.016 ;
     RECT  5.404 122.976 5.555 127.656 ;
     RECT  5.404 130.032 5.555 131.688 ;
     RECT  5.555 122.976 5.573 127.032 ;
     RECT  5.404 34.992 5.609 35.304 ;
     RECT  5.573 122.976 5.609 123 ;
     RECT  5.501 79.056 5.645 86.232 ;
     RECT  5.555 130.464 5.645 131.112 ;
     RECT  5.645 79.056 5.681 84.072 ;
     RECT  5.537 87.264 5.681 87.912 ;
     RECT  5.537 88.896 5.681 89.016 ;
     RECT  5.645 130.464 5.681 131.064 ;
     RECT  5.537 31.968 5.717 33.048 ;
     RECT  5.681 79.056 5.717 81.624 ;
     RECT  5.573 124.08 5.717 127.032 ;
     RECT  5.681 131.04 5.717 131.064 ;
     RECT  5.717 125.952 5.789 126.984 ;
     RECT  5.717 79.056 5.795 81.288 ;
     RECT  5.404 36.768 5.833 37.032 ;
     RECT  5.404 44.208 5.861 45.288 ;
     RECT  5.681 82.8 5.897 84.072 ;
     RECT  5.795 79.056 5.932 81.096 ;
     RECT  5.404 42.72 5.987 42.792 ;
     RECT  5.681 87.888 5.987 87.912 ;
     RECT  5.789 126 6.041 126.984 ;
     RECT  5.717 32.496 6.113 33.048 ;
     RECT  5.987 42.768 6.437 42.792 ;
     RECT  5.897 83.616 6.437 84.072 ;
     RECT  5.645 85.344 6.581 86.232 ;
     RECT  6.581 85.392 6.613 86.232 ;
     RECT  5.609 34.992 6.685 35.016 ;
     RECT  5.681 88.896 6.685 88.92 ;
     RECT  5.932 79.776 6.757 81.096 ;
     RECT  5.404 73.2 6.829 73.224 ;
     RECT  5.717 124.08 6.829 124.872 ;
     RECT  6.113 33.024 6.853 33.048 ;
     RECT  6.685 34.32 6.853 35.016 ;
     RECT  6.757 79.776 6.865 81.624 ;
     RECT  6.041 126.336 7.009 126.984 ;
     RECT  6.865 79.776 7.141 82.584 ;
     RECT  5.861 44.208 7.153 44.232 ;
     RECT  5.861 45.264 7.153 45.288 ;
     RECT  7.009 126.192 7.153 126.984 ;
     RECT  7.153 126.144 7.261 126.984 ;
     RECT  6.685 88.656 7.297 88.92 ;
     RECT  6.853 33.024 7.808 35.016 ;
     RECT  5.833 36.768 7.808 36.792 ;
     RECT  5.404 40.848 7.808 41.64 ;
     RECT  7.153 44.208 7.808 45.288 ;
     RECT  6.829 73.2 7.808 73.32 ;
     RECT  7.141 79.584 7.808 82.584 ;
     RECT  6.437 84.048 7.808 84.072 ;
     RECT  6.613 85.392 7.808 86.664 ;
     RECT  7.297 88.656 7.808 89.544 ;
     RECT  6.829 124.08 7.808 124.92 ;
     RECT  7.261 126.144 7.808 127.656 ;
     RECT  7.297 131.376 7.808 131.4 ;
     RECT  7.808 2.148 7.912 168.492 ;
     RECT  7.912 2.418 8.104 168.222 ;
     RECT  8.104 79.776 8.201 81.48 ;
     RECT  8.104 33.6 8.243 33.624 ;
     RECT  8.104 82.8 8.243 86.664 ;
     RECT  8.104 126.96 8.243 127.656 ;
     RECT  8.104 130.464 8.243 131.544 ;
     RECT  8.104 35.328 8.281 35.352 ;
     RECT  8.243 84.048 8.281 86.664 ;
     RECT  8.243 131.52 8.281 131.544 ;
     RECT  8.281 84.048 8.309 86.04 ;
     RECT  8.104 44.88 8.381 44.904 ;
     RECT  8.201 79.776 8.381 79.8 ;
     RECT  8.243 82.8 8.387 82.824 ;
     RECT  8.104 124.656 8.417 124.68 ;
     RECT  8.104 36.432 8.483 36.456 ;
     RECT  8.201 81.456 8.489 81.48 ;
     RECT  8.309 84.048 8.489 84.984 ;
     RECT  8.309 86.016 8.489 86.04 ;
     RECT  8.104 43.536 8.524 43.8 ;
     RECT  8.104 40.848 8.525 42.168 ;
     RECT  8.524 43.728 8.675 43.8 ;
     RECT  8.675 43.776 8.705 43.8 ;
     RECT  8.525 40.848 10.508 41.4 ;
     RECT  8.104 49.248 10.508 49.272 ;
     RECT  8.104 73.296 10.508 73.32 ;
     RECT  8.489 84.048 10.508 84.072 ;
     RECT  8.104 89.52 10.508 89.544 ;
     RECT  8.243 126.96 10.508 126.984 ;
     RECT  10.508 2.148 10.612 168.492 ;
     RECT  10.612 2.418 10.804 168.222 ;
     RECT  10.804 40.848 11.873 41.4 ;
     RECT  10.804 73.2 12.445 73.224 ;
     RECT  11.873 41.376 13.208 41.4 ;
     RECT  10.804 49.248 13.208 49.272 ;
     RECT  12.445 73.2 13.208 73.32 ;
     RECT  10.804 84.048 13.208 84.072 ;
     RECT  10.804 89.52 13.208 89.544 ;
     RECT  10.804 126.96 13.208 126.984 ;
     RECT  13.208 2.148 13.312 168.492 ;
     RECT  13.312 2.418 13.504 168.222 ;
     RECT  13.504 49.248 13.601 49.368 ;
     RECT  13.601 49.344 14.821 49.368 ;
     RECT  14.821 49.248 14.861 49.368 ;
     RECT  13.504 41.376 15.908 41.4 ;
     RECT  14.861 49.248 15.908 49.272 ;
     RECT  13.504 73.296 15.908 73.32 ;
     RECT  13.504 84.048 15.908 84.072 ;
     RECT  13.504 89.52 15.908 89.544 ;
     RECT  13.504 126.96 15.908 126.984 ;
     RECT  15.908 2.148 16.012 168.492 ;
     RECT  16.012 2.418 16.204 168.222 ;
     RECT  16.204 41.376 18.608 41.4 ;
     RECT  16.204 49.248 18.608 49.272 ;
     RECT  16.204 73.296 18.608 73.32 ;
     RECT  16.204 84.048 18.608 84.072 ;
     RECT  16.204 89.52 18.608 89.544 ;
     RECT  16.204 126.96 18.608 126.984 ;
     RECT  18.608 2.148 18.712 168.492 ;
     RECT  18.712 2.418 18.904 168.222 ;
     RECT  18.904 41.376 21.308 41.4 ;
     RECT  18.904 49.248 21.308 49.272 ;
     RECT  18.904 73.296 21.308 73.32 ;
     RECT  18.904 84.048 21.308 84.072 ;
     RECT  18.904 89.52 21.308 89.544 ;
     RECT  18.904 126.96 21.308 126.984 ;
     RECT  21.308 2.148 21.412 168.492 ;
     RECT  21.412 2.418 21.604 168.222 ;
     RECT  21.604 49.248 21.701 49.368 ;
     RECT  21.604 99.936 22.141 100.296 ;
     RECT  21.604 93.072 22.355 93.096 ;
     RECT  22.141 99.936 22.385 99.96 ;
     RECT  21.604 73.296 22.691 73.32 ;
     RECT  22.604 92.928 22.691 92.952 ;
     RECT  21.701 49.344 22.813 49.368 ;
     RECT  22.813 49.248 22.853 49.368 ;
     RECT  21.604 41.376 24.008 41.4 ;
     RECT  22.853 49.248 24.008 49.272 ;
     RECT  21.604 84.048 24.008 84.072 ;
     RECT  21.604 89.52 24.008 89.544 ;
     RECT  22.645 120 24.008 120.024 ;
     RECT  21.604 126.96 24.008 126.984 ;
     RECT  21.604 144 24.008 144.024 ;
     RECT  24.008 2.148 24.112 168.492 ;
     RECT  24.112 2.418 24.304 168.222 ;
     RECT  24.304 120 24.941 120.696 ;
     RECT  24.941 120.048 24.947 120.696 ;
     RECT  24.304 126.96 24.947 126.984 ;
     RECT  24.304 41.376 26.708 41.4 ;
     RECT  24.304 49.248 26.708 49.272 ;
     RECT  24.304 84.048 26.708 84.072 ;
     RECT  24.304 89.52 26.708 89.544 ;
     RECT  24.947 120.048 26.708 120.072 ;
     RECT  24.304 144 26.708 144.024 ;
     RECT  26.708 2.148 26.812 168.492 ;
     RECT  26.812 2.418 27.004 168.222 ;
     RECT  27.004 41.376 29.408 41.4 ;
     RECT  27.004 49.248 29.408 49.272 ;
     RECT  27.004 84.048 29.408 84.072 ;
     RECT  27.004 89.52 29.408 89.544 ;
     RECT  27.004 120.048 29.408 120.072 ;
     RECT  27.004 144 29.408 144.024 ;
     RECT  29.408 2.148 29.512 168.492 ;
     RECT  29.512 2.418 29.704 168.222 ;
     RECT  29.704 49.248 29.801 49.368 ;
     RECT  29.704 120.048 29.801 120.216 ;
     RECT  29.801 49.344 30.769 49.368 ;
     RECT  29.801 120.192 30.769 120.216 ;
     RECT  30.769 49.248 30.809 49.368 ;
     RECT  30.769 120.048 30.809 120.216 ;
     RECT  29.704 41.376 32.108 41.4 ;
     RECT  30.809 49.248 32.108 49.272 ;
     RECT  29.704 84.048 32.108 84.072 ;
     RECT  29.704 89.52 32.108 89.544 ;
     RECT  30.809 120.048 32.108 120.072 ;
     RECT  29.704 144 32.108 144.024 ;
     RECT  32.108 2.148 32.212 168.492 ;
     RECT  32.212 2.418 32.404 168.222 ;
     RECT  32.404 49.248 34.765 49.272 ;
     RECT  34.729 132.912 34.765 132.936 ;
     RECT  32.404 41.376 34.808 41.4 ;
     RECT  34.765 49.248 34.808 49.512 ;
     RECT  32.404 84.048 34.808 84.072 ;
     RECT  32.404 89.52 34.808 89.544 ;
     RECT  32.404 120.048 34.808 120.072 ;
     RECT  34.765 124.08 34.808 124.104 ;
     RECT  34.441 128.592 34.808 128.616 ;
     RECT  34.729 131.664 34.808 131.688 ;
     RECT  34.765 132.72 34.808 132.936 ;
     RECT  34.657 135.168 34.808 135.192 ;
     RECT  34.801 137.856 34.808 137.88 ;
     RECT  32.404 144 34.808 144.024 ;
     RECT  34.808 2.148 34.912 168.492 ;
     RECT  34.912 2.418 35.104 168.222 ;
     RECT  35.104 126.96 35.219 128.616 ;
     RECT  35.104 134.496 35.273 139.128 ;
     RECT  35.219 126.96 35.525 127.848 ;
     RECT  35.273 135.168 35.555 139.128 ;
     RECT  35.555 135.168 35.561 138.984 ;
     RECT  35.561 135.168 35.596 137.016 ;
     RECT  35.104 129.792 35.705 132.936 ;
     RECT  35.104 140.16 35.741 141 ;
     RECT  35.525 126.96 35.747 127.656 ;
     RECT  35.741 140.16 35.849 140.184 ;
     RECT  35.705 129.792 36.065 132.648 ;
     RECT  35.596 135.168 36.065 135.192 ;
     RECT  35.104 122.784 36.133 125.976 ;
     RECT  36.065 129.792 36.137 132.504 ;
     RECT  35.596 136.992 36.137 137.016 ;
     RECT  36.133 122.784 36.281 126.264 ;
     RECT  35.747 127.632 36.281 127.656 ;
     RECT  36.281 123.36 36.389 126.264 ;
     RECT  36.668 133.872 36.745 133.896 ;
     RECT  36.709 136.944 36.817 136.968 ;
     RECT  36.601 141.36 36.817 141.384 ;
     RECT  36.389 124.8 37.141 126.264 ;
     RECT  36.817 136.08 37.141 136.968 ;
     RECT  35.561 138.576 37.141 138.984 ;
     RECT  36.137 129.888 37.189 132.504 ;
     RECT  37.141 124.8 37.224 126.504 ;
     RECT  35.104 41.376 37.508 41.4 ;
     RECT  35.104 49.488 37.508 49.512 ;
     RECT  35.104 84.048 37.508 84.072 ;
     RECT  35.104 89.52 37.508 89.544 ;
     RECT  37.501 99.168 37.508 99.192 ;
     RECT  36.133 117.84 37.508 117.864 ;
     RECT  35.104 120.048 37.508 120.072 ;
     RECT  36.389 123.36 37.508 123.624 ;
     RECT  37.224 124.8 37.508 126.792 ;
     RECT  37.141 128.64 37.508 128.664 ;
     RECT  37.189 129.696 37.508 132.504 ;
     RECT  36.745 133.872 37.508 134.856 ;
     RECT  37.141 136.08 37.508 139.704 ;
     RECT  36.817 140.784 37.508 141.384 ;
     RECT  35.104 144 37.508 144.024 ;
     RECT  37.381 148.176 37.508 148.2 ;
     RECT  37.381 165.312 37.508 165.336 ;
     RECT  37.508 2.148 37.612 168.492 ;
     RECT  37.612 2.418 37.804 168.222 ;
     RECT  37.825 170.4 37.957 170.424 ;
     RECT  37.804 115.584 38.003 115.704 ;
     RECT  37.957 170.4 38.044 170.52 ;
     RECT  37.804 97.92 38.099 98.184 ;
     RECT  37.804 99.168 38.099 99.192 ;
     RECT  37.804 123.504 38.099 124.632 ;
     RECT  37.804 126 38.099 127.656 ;
     RECT  37.804 145.872 38.147 147.672 ;
     RECT  37.804 155.616 38.147 156.168 ;
     RECT  38.044 170.4 38.147 170.424 ;
     RECT  38.003 115.584 38.153 115.608 ;
     RECT  37.804 143.616 38.153 144.12 ;
     RECT  38.153 144 38.188 144.12 ;
     RECT  37.804 149.904 38.195 151.416 ;
     RECT  37.804 160.752 38.195 161.064 ;
     RECT  37.804 162.48 38.195 163.176 ;
     RECT  38.099 98.16 38.225 98.184 ;
     RECT  37.804 164.256 38.225 167.592 ;
     RECT  38.147 145.872 38.243 147.624 ;
     RECT  37.804 129.024 38.261 135.096 ;
     RECT  37.804 136.176 38.261 141.336 ;
     RECT  38.261 136.176 38.284 140.184 ;
     RECT  38.225 165.312 38.291 167.592 ;
     RECT  38.291 166.656 38.297 167.592 ;
     RECT  38.147 155.616 38.333 155.64 ;
     RECT  38.195 160.752 38.333 160.776 ;
     RECT  38.195 149.904 38.377 151.08 ;
     RECT  37.804 119.712 38.387 120.072 ;
     RECT  38.261 132.864 38.387 135.096 ;
     RECT  38.284 136.176 38.387 139.704 ;
     RECT  38.243 145.872 38.387 145.944 ;
     RECT  38.387 136.176 38.441 136.968 ;
     RECT  38.387 132.864 38.477 135 ;
     RECT  37.804 50.544 38.483 51.624 ;
     RECT  38.291 165.312 38.483 165.336 ;
     RECT  38.297 166.656 38.549 166.68 ;
     RECT  38.387 119.712 38.579 119.736 ;
     RECT  38.377 149.904 38.579 150.456 ;
     RECT  38.195 163.152 38.579 163.176 ;
     RECT  38.225 164.256 38.579 164.28 ;
     RECT  38.579 149.904 38.593 150.168 ;
     RECT  38.477 133.968 38.627 135 ;
     RECT  38.387 138.048 38.627 138.696 ;
     RECT  38.627 138.048 38.657 138.072 ;
     RECT  38.261 141.312 38.723 141.336 ;
     RECT  38.387 145.92 38.723 145.944 ;
     RECT  37.804 52.656 38.729 53.64 ;
     RECT  38.243 146.976 38.771 147.624 ;
     RECT  37.804 148.848 38.771 148.872 ;
     RECT  37.804 49.248 38.797 49.512 ;
     RECT  38.483 50.544 38.797 50.952 ;
     RECT  37.804 47.856 38.8 47.88 ;
     RECT  38.261 129.024 38.837 131.64 ;
     RECT  38.8 47.808 38.869 47.88 ;
     RECT  38.797 49.248 38.869 50.952 ;
     RECT  38.771 146.976 38.873 147 ;
     RECT  38.593 150.144 38.873 150.168 ;
     RECT  38.837 131.328 38.909 131.64 ;
     RECT  38.099 126.144 38.941 127.656 ;
     RECT  38.941 126.144 39.085 127.848 ;
     RECT  39.157 86.64 39.229 86.664 ;
     RECT  39.157 76.08 39.244 76.104 ;
     RECT  37.804 89.52 39.373 89.544 ;
     RECT  38.188 144 39.373 144.024 ;
     RECT  39.373 144 39.445 144.12 ;
     RECT  39.445 91.968 39.481 91.992 ;
     RECT  37.804 41.376 39.589 41.4 ;
     RECT  38.797 93.6 39.596 93.624 ;
     RECT  39.409 94.656 39.596 94.68 ;
     RECT  37.804 83.76 39.637 84.072 ;
     RECT  38.869 47.808 39.692 50.952 ;
     RECT  39.637 83.76 39.733 84.12 ;
     RECT  39.481 91.344 39.769 91.992 ;
     RECT  39.085 125.616 39.836 127.848 ;
     RECT  38.837 129.024 39.836 129.96 ;
     RECT  38.387 139.68 39.841 139.704 ;
     RECT  39.841 139.68 39.877 140.232 ;
     RECT  39.373 88.896 39.98 89.544 ;
     RECT  39.769 91.344 39.98 92.424 ;
     RECT  38.099 124.224 39.98 124.632 ;
     RECT  39.836 125.616 39.98 129.96 ;
     RECT  39.98 124.224 40.021 129.96 ;
     RECT  37.804 109.392 40.069 109.416 ;
     RECT  39.98 88.608 40.093 92.424 ;
     RECT  39.596 93.6 40.093 94.68 ;
     RECT  40.057 46.08 40.129 46.104 ;
     RECT  40.129 45.696 40.165 46.104 ;
     RECT  39.692 47.28 40.165 50.952 ;
     RECT  40.021 123.456 40.201 129.96 ;
     RECT  39.589 40.896 40.208 41.4 ;
     RECT  40.165 45.696 40.208 50.952 ;
     RECT  38.729 52.656 40.208 52.68 ;
     RECT  39.733 83.76 40.208 84.936 ;
     RECT  39.229 86.64 40.208 87.192 ;
     RECT  40.093 88.608 40.208 94.68 ;
     RECT  37.804 96.336 40.208 96.36 ;
     RECT  39.193 97.488 40.208 97.512 ;
     RECT  40.069 109.392 40.208 109.56 ;
     RECT  37.804 117.84 40.208 117.864 ;
     RECT  40.201 122.64 40.208 129.96 ;
     RECT  38.477 132.864 40.208 132.888 ;
     RECT  38.627 133.968 40.208 134.568 ;
     RECT  38.441 136.944 40.208 136.968 ;
     RECT  39.877 139.536 40.208 140.232 ;
     RECT  39.445 143.616 40.208 144.12 ;
     RECT  40.208 2.148 40.312 168.492 ;
     RECT  40.312 2.418 40.504 168.222 ;
     RECT  40.504 87.456 40.637 89.544 ;
     RECT  40.504 122.544 40.709 126.984 ;
     RECT  40.637 87.456 40.781 89.304 ;
     RECT  40.504 91.008 40.979 97.176 ;
     RECT  40.504 103.728 40.979 103.944 ;
     RECT  40.709 122.544 40.997 124.632 ;
     RECT  40.504 129.6 41.027 130.776 ;
     RECT  40.504 143.664 41.033 143.688 ;
     RECT  40.504 109.392 41.123 109.416 ;
     RECT  40.504 114.528 41.123 114.984 ;
     RECT  40.997 122.544 41.149 124.344 ;
     RECT  40.504 121.536 41.321 121.56 ;
     RECT  40.504 98.592 41.465 98.616 ;
     RECT  41.123 114.528 41.465 114.552 ;
     RECT  40.504 45.216 41.497 46.776 ;
     RECT  41.497 45.12 41.533 46.776 ;
     RECT  40.504 47.904 41.533 51.096 ;
     RECT  40.504 52.32 41.533 53.592 ;
     RECT  40.979 91.008 41.533 96.888 ;
     RECT  41.533 44.832 41.557 46.776 ;
     RECT  40.504 132.48 41.569 133.08 ;
     RECT  41.557 44.352 41.605 46.776 ;
     RECT  41.533 47.904 41.605 53.592 ;
     RECT  40.504 134.592 41.605 135.192 ;
     RECT  40.504 138.048 41.605 138.072 ;
     RECT  41.569 132.48 41.641 133.272 ;
     RECT  41.605 137.664 41.641 138.072 ;
     RECT  41.149 122.88 41.645 124.344 ;
     RECT  41.605 44.352 41.677 53.592 ;
     RECT  41.641 132.48 41.677 133.368 ;
     RECT  40.504 83.76 41.749 84.12 ;
     RECT  41.557 113.472 41.749 113.496 ;
     RECT  40.709 126.48 41.749 126.984 ;
     RECT  41.027 130.656 41.749 130.776 ;
     RECT  41.677 132.288 41.749 133.368 ;
     RECT  41.641 137.472 41.749 138.072 ;
     RECT  41.605 134.592 41.785 135.288 ;
     RECT  41.749 137.472 41.785 138.264 ;
     RECT  41.569 140.064 41.785 140.088 ;
     RECT  40.781 87.456 41.821 87.816 ;
     RECT  40.781 88.896 41.821 89.304 ;
     RECT  41.749 130.656 41.821 133.368 ;
     RECT  41.785 134.4 41.821 135.288 ;
     RECT  41.749 113.472 41.833 114.024 ;
     RECT  41.533 90.72 41.857 96.888 ;
     RECT  41.821 87.456 41.929 89.304 ;
     RECT  41.677 44.16 42.001 53.592 ;
     RECT  41.785 137.472 42.037 138.552 ;
     RECT  42.037 137.472 42.073 138.744 ;
     RECT  41.785 139.968 42.073 140.088 ;
     RECT  42.073 137.472 42.109 140.088 ;
     RECT  41.749 83.616 42.133 84.12 ;
     RECT  41.929 87.456 42.133 89.4 ;
     RECT  41.857 90.624 42.133 96.888 ;
     RECT  42.133 83.616 42.181 84.216 ;
     RECT  42.181 83.28 42.217 84.216 ;
     RECT  42.217 82.608 42.289 84.216 ;
     RECT  41.749 125.952 42.325 127.032 ;
     RECT  41.821 130.656 42.325 135.288 ;
     RECT  42.325 125.952 42.397 127.08 ;
     RECT  42.397 125.952 42.505 127.176 ;
     RECT  42.289 82.512 42.565 84.216 ;
     RECT  42.133 87.456 42.577 96.888 ;
     RECT  42.565 82.224 42.613 84.216 ;
     RECT  42.577 87.456 42.613 96.984 ;
     RECT  42.505 125.424 42.613 127.176 ;
     RECT  42.001 44.16 42.661 53.688 ;
     RECT  42.325 130.656 42.661 135.384 ;
     RECT  42.661 44.064 42.709 53.688 ;
     RECT  42.661 64.944 42.709 64.968 ;
     RECT  42.613 82.224 42.709 84.264 ;
     RECT  42.661 130.56 42.709 135.384 ;
     RECT  42.109 137.472 42.721 140.184 ;
     RECT  42.661 128.784 42.833 128.808 ;
     RECT  40.504 40.896 42.908 40.92 ;
     RECT  42.709 64.608 42.908 64.968 ;
     RECT  42.613 79.584 42.908 79.608 ;
     RECT  42.709 82.224 42.908 84.36 ;
     RECT  42.709 107.28 42.908 108.216 ;
     RECT  41.833 113.472 42.908 113.496 ;
     RECT  40.504 117.84 42.908 117.864 ;
     RECT  41.645 122.88 42.908 123.528 ;
     RECT  42.613 124.848 42.908 127.176 ;
     RECT  42.709 43.968 42.973 53.688 ;
     RECT  42.908 2.148 43.012 41.052 ;
     RECT  42.908 62.628 43.012 84.36 ;
     RECT  42.908 105.828 43.012 127.452 ;
     RECT  42.908 149.028 43.012 168.492 ;
     RECT  42.709 130.368 43.081 135.384 ;
     RECT  43.081 129.456 43.2 135.384 ;
     RECT  42.721 137.28 43.2 140.184 ;
     RECT  43.012 2.418 43.204 40.92 ;
     RECT  43.012 62.898 43.204 84.36 ;
     RECT  43.012 106.098 43.204 127.182 ;
     RECT  43.012 149.298 43.204 168.222 ;
     RECT  43.204 83.616 43.265 84.36 ;
     RECT  43.204 107.28 43.265 108.552 ;
     RECT  43.204 113.472 43.265 113.496 ;
     RECT  42.973 43.968 43.272 53.784 ;
     RECT  40.504 60.576 43.272 60.6 ;
     RECT  40.504 86.016 43.272 86.04 ;
     RECT  42.613 87.168 43.272 96.984 ;
     RECT  40.979 103.776 43.272 103.944 ;
     RECT  43.2 129.456 43.272 140.184 ;
     RECT  43.272 129.456 43.331 146.904 ;
     RECT  43.265 107.808 43.409 108.552 ;
     RECT  43.204 64.608 43.553 64.968 ;
     RECT  43.265 83.76 43.553 84.36 ;
     RECT  43.553 83.76 44.732 84.12 ;
     RECT  43.204 40.896 45.608 40.92 ;
     RECT  43.553 64.944 45.608 64.968 ;
     RECT  44.732 83.664 45.608 84.12 ;
     RECT  43.409 107.808 45.608 107.832 ;
     RECT  43.204 117.84 45.608 117.864 ;
     RECT  43.204 126.432 45.608 126.792 ;
     RECT  45.608 2.148 45.712 41.052 ;
     RECT  45.608 62.628 45.712 84.252 ;
     RECT  45.608 105.828 45.712 127.452 ;
     RECT  45.608 149.028 45.712 168.492 ;
     RECT  45.712 2.418 45.904 40.92 ;
     RECT  45.712 62.898 45.904 84.12 ;
     RECT  45.712 106.098 45.904 127.182 ;
     RECT  45.712 149.298 45.904 168.222 ;
     RECT  45.904 40.848 46.286 40.92 ;
     RECT  45.904 83.76 46.753 84.12 ;
     RECT  46.286 40.848 48.308 40.872 ;
     RECT  46.753 83.76 48.308 84.168 ;
     RECT  45.904 117.84 48.308 117.864 ;
     RECT  45.904 126.432 48.308 126.792 ;
     RECT  48.308 2.148 48.412 41.052 ;
     RECT  48.308 62.628 48.412 84.252 ;
     RECT  48.308 105.828 48.412 127.452 ;
     RECT  48.308 149.028 48.412 168.492 ;
     RECT  48.412 2.418 48.604 40.872 ;
     RECT  48.412 62.898 48.604 84.168 ;
     RECT  48.412 106.098 48.604 127.182 ;
     RECT  48.412 149.298 48.604 168.222 ;
     RECT  48.604 40.848 51.008 40.872 ;
     RECT  48.604 83.76 51.008 84.168 ;
     RECT  48.604 117.84 51.008 117.864 ;
     RECT  48.604 126.432 51.008 126.792 ;
     RECT  51.008 2.148 51.112 41.052 ;
     RECT  51.008 62.628 51.112 84.252 ;
     RECT  51.008 105.828 51.112 127.452 ;
     RECT  51.008 149.028 51.112 168.492 ;
     RECT  51.112 2.418 51.304 40.872 ;
     RECT  51.112 62.898 51.304 84.168 ;
     RECT  51.112 106.098 51.304 127.182 ;
     RECT  51.112 149.298 51.304 168.222 ;
     RECT  51.304 40.848 53.708 40.872 ;
     RECT  51.304 83.76 53.708 84.168 ;
     RECT  51.304 117.84 53.708 117.864 ;
     RECT  51.304 126.432 53.708 126.792 ;
     RECT  53.708 2.148 53.812 41.052 ;
     RECT  53.708 62.628 53.812 84.252 ;
     RECT  53.708 105.828 53.812 127.452 ;
     RECT  53.708 149.028 53.812 168.492 ;
     RECT  53.812 2.418 54.004 40.872 ;
     RECT  53.812 62.898 54.004 84.168 ;
     RECT  53.812 106.098 54.004 127.182 ;
     RECT  53.812 149.298 54.004 168.222 ;
     RECT  54.004 126.432 54.101 126.792 ;
     RECT  54.101 126.432 56.041 126.696 ;
     RECT  54.004 40.848 56.408 40.872 ;
     RECT  54.004 83.76 56.408 84.168 ;
     RECT  54.004 117.84 56.408 117.864 ;
     RECT  56.041 126.432 56.408 127.368 ;
     RECT  56.408 2.148 56.512 41.052 ;
     RECT  56.408 62.628 56.512 84.252 ;
     RECT  56.408 105.828 56.512 127.452 ;
     RECT  56.408 149.028 56.512 168.492 ;
     RECT  56.512 2.418 56.704 40.872 ;
     RECT  56.512 62.898 56.704 84.168 ;
     RECT  56.512 106.098 56.704 127.368 ;
     RECT  56.512 149.298 56.704 168.222 ;
     RECT  56.704 126.432 56.909 127.368 ;
     RECT  56.704 40.56 59.108 40.872 ;
     RECT  56.704 83.76 59.108 84.168 ;
     RECT  56.704 117.84 59.108 117.864 ;
     RECT  56.909 127.248 59.108 127.368 ;
     RECT  59.108 2.148 59.212 41.052 ;
     RECT  59.108 62.628 59.212 84.252 ;
     RECT  59.108 105.828 59.212 127.452 ;
     RECT  59.108 149.028 59.212 168.492 ;
     RECT  59.212 2.418 59.404 40.872 ;
     RECT  59.212 62.898 59.404 84.168 ;
     RECT  59.212 106.098 59.404 127.368 ;
     RECT  59.212 149.298 59.404 168.222 ;
     RECT  59.404 40.56 61.808 40.872 ;
     RECT  59.404 83.76 61.808 84.168 ;
     RECT  59.404 117.84 61.808 117.864 ;
     RECT  59.404 127.248 61.808 127.368 ;
     RECT  61.808 2.148 61.912 41.052 ;
     RECT  61.808 62.628 61.912 84.252 ;
     RECT  61.808 105.828 61.912 127.452 ;
     RECT  61.808 149.028 61.912 168.492 ;
     RECT  61.912 2.418 62.104 40.872 ;
     RECT  61.912 62.898 62.104 84.168 ;
     RECT  61.912 106.098 62.104 127.368 ;
     RECT  61.912 149.298 62.104 168.222 ;
     RECT  62.104 83.76 62.309 84.168 ;
     RECT  62.104 117.792 63.107 117.96 ;
     RECT  62.104 127.248 63.107 127.368 ;
     RECT  62.309 83.76 64.501 84.072 ;
     RECT  62.104 40.56 64.508 40.872 ;
     RECT  64.501 83.76 64.508 84.168 ;
     RECT  62.104 108.144 64.508 108.168 ;
     RECT  63.107 117.936 64.508 117.96 ;
     RECT  63.107 127.248 64.508 127.272 ;
     RECT  64.508 2.148 64.612 41.052 ;
     RECT  64.508 62.628 64.612 84.252 ;
     RECT  64.508 105.828 64.612 127.452 ;
     RECT  64.508 149.028 64.612 168.492 ;
     RECT  64.612 2.418 64.804 41.016 ;
     RECT  64.612 62.898 64.804 84.168 ;
     RECT  64.612 105.828 64.804 127.272 ;
     RECT  64.612 149.298 64.804 168.222 ;
     RECT  64.804 40.56 65.017 41.016 ;
     RECT  64.804 107.664 65.017 108.168 ;
     RECT  64.804 106.56 65.225 106.584 ;
     RECT  65.017 108.144 65.225 108.168 ;
     RECT  64.861 105.456 65.267 105.48 ;
     RECT  64.804 83.232 65.411 84.168 ;
     RECT  64.804 78.384 65.737 78.408 ;
     RECT  65.411 83.808 65.873 84.168 ;
     RECT  65.017 40.56 67.208 40.872 ;
     RECT  64.804 65.712 67.208 65.736 ;
     RECT  64.804 75.456 67.208 75.48 ;
     RECT  66.589 78.048 67.208 78.072 ;
     RECT  65.873 83.808 67.208 84.072 ;
     RECT  64.804 117.84 67.208 117.864 ;
     RECT  64.804 127.248 67.208 127.272 ;
     RECT  67.208 2.148 67.312 41.052 ;
     RECT  67.208 62.628 67.312 84.252 ;
     RECT  67.208 105.828 67.312 127.452 ;
     RECT  67.208 149.028 67.312 168.492 ;
     RECT  67.312 2.418 67.504 40.872 ;
     RECT  67.312 62.898 67.504 84.072 ;
     RECT  67.312 106.098 67.504 127.272 ;
     RECT  67.312 149.298 67.504 168.222 ;
     RECT  67.504 40.56 69.908 40.872 ;
     RECT  67.504 65.712 69.908 65.736 ;
     RECT  67.504 75.456 69.908 75.48 ;
     RECT  67.504 83.808 69.908 84.072 ;
     RECT  67.504 117.84 69.908 117.864 ;
     RECT  67.504 127.248 69.908 127.272 ;
     RECT  69.908 2.148 70.012 41.052 ;
     RECT  69.908 62.628 70.012 84.252 ;
     RECT  69.908 105.828 70.012 127.452 ;
     RECT  69.908 149.028 70.012 168.492 ;
     RECT  70.012 2.418 70.204 40.872 ;
     RECT  70.012 62.898 70.204 84.072 ;
     RECT  70.012 106.098 70.204 127.272 ;
     RECT  70.012 149.298 70.204 168.222 ;
     RECT  70.204 40.56 72.608 40.872 ;
     RECT  70.204 65.712 72.608 65.736 ;
     RECT  70.204 75.456 72.608 75.48 ;
     RECT  70.204 83.808 72.608 84.072 ;
     RECT  70.204 117.84 72.608 117.864 ;
     RECT  70.204 127.248 72.608 127.272 ;
     RECT  72.608 2.148 72.712 41.052 ;
     RECT  72.608 62.628 72.712 84.252 ;
     RECT  72.608 105.828 72.712 127.452 ;
     RECT  72.608 149.028 72.712 168.492 ;
     RECT  72.712 2.418 72.904 40.872 ;
     RECT  72.712 62.898 72.904 84.168 ;
     RECT  72.712 106.098 72.904 127.272 ;
     RECT  72.712 149.298 72.904 168.222 ;
     RECT  72.904 125.952 73.721 125.976 ;
     RECT  73.868 124.8 73.955 124.824 ;
     RECT  72.904 127.248 74.045 127.272 ;
     RECT  73.909 123.072 74.081 123.096 ;
     RECT  43.331 129.6 74.977 146.904 ;
     RECT  72.904 83.808 75.013 84.168 ;
     RECT  74.533 125.856 75.109 125.88 ;
     RECT  72.904 40.56 75.116 40.872 ;
     RECT  43.272 43.2 75.12 60.6 ;
     RECT  43.272 86.016 75.12 103.944 ;
     RECT  74.977 129.504 75.12 146.904 ;
     RECT  75.12 43.2 75.157 53.88 ;
     RECT  75.013 83.808 75.157 84.408 ;
     RECT  75.116 40.56 75.203 41.64 ;
     RECT  74.113 124.512 75.229 124.536 ;
     RECT  75.157 147.072 75.269 147.096 ;
     RECT  75.12 87.168 75.305 97.08 ;
     RECT  75.12 129.504 75.305 140.184 ;
     RECT  75.203 40.56 75.308 41.052 ;
     RECT  72.904 65.712 75.308 65.736 ;
     RECT  72.904 75.456 75.308 75.48 ;
     RECT  75.157 83.808 75.308 84.984 ;
     RECT  72.904 117.84 75.308 117.864 ;
     RECT  75.229 124.272 75.308 124.536 ;
     RECT  75.109 125.712 75.308 126.648 ;
     RECT  75.157 43.056 75.341 53.88 ;
     RECT  75.305 87.264 75.341 97.08 ;
     RECT  75.305 129.504 75.341 140.088 ;
     RECT  75.341 43.968 75.377 53.688 ;
     RECT  75.308 2.148 75.412 41.052 ;
     RECT  75.308 62.628 75.412 84.984 ;
     RECT  75.308 105.828 75.412 127.452 ;
     RECT  75.308 149.028 75.412 168.492 ;
     RECT  75.412 62.898 75.413 84.984 ;
     RECT  75.341 129.504 75.449 139.992 ;
     RECT  75.377 44.064 75.521 53.592 ;
     RECT  75.412 2.418 75.604 40.872 ;
     RECT  75.413 62.898 75.604 84.168 ;
     RECT  75.412 106.098 75.604 127.272 ;
     RECT  75.412 149.298 75.604 168.222 ;
     RECT  75.341 87.264 75.665 96.888 ;
     RECT  75.604 75.456 75.701 75.576 ;
     RECT  75.12 60.576 75.731 60.6 ;
     RECT  75.12 103.776 75.731 103.944 ;
     RECT  75.731 103.776 75.779 103.896 ;
     RECT  75.604 124.272 75.779 124.296 ;
     RECT  75.779 103.872 75.827 103.896 ;
     RECT  75.449 130.224 75.827 139.992 ;
     RECT  75.827 130.32 75.989 139.992 ;
     RECT  75.701 75.552 76.067 75.576 ;
     RECT  75.604 83.808 76.067 84.168 ;
     RECT  75.989 134.88 76.169 139.992 ;
     RECT  76.169 134.88 76.421 139.8 ;
     RECT  75.604 73.296 76.493 73.32 ;
     RECT  75.989 130.32 77.533 133.656 ;
     RECT  76.421 134.88 77.533 139.704 ;
     RECT  77.533 130.32 77.557 139.704 ;
     RECT  77.317 70.608 77.852 70.632 ;
     RECT  75.604 40.56 78.008 40.872 ;
     RECT  75.521 44.064 78.008 53.496 ;
     RECT  75.604 65.712 78.008 65.736 ;
     RECT  77.893 68.16 78.008 68.184 ;
     RECT  77.852 70.128 78.008 70.632 ;
     RECT  77.317 72.96 78.008 72.984 ;
     RECT  76.067 83.808 78.008 84.12 ;
     RECT  75.12 86.016 78.008 86.04 ;
     RECT  75.665 87.264 78.008 96.744 ;
     RECT  75.12 98.928 78.008 98.952 ;
     RECT  75.604 117.84 78.008 117.864 ;
     RECT  75.604 125.712 78.008 127.272 ;
     RECT  77.557 130.32 78.008 139.944 ;
     RECT  78.008 2.148 78.112 168.492 ;
     RECT  78.112 2.418 78.304 168.222 ;
     RECT  78.304 83.808 78.401 84.168 ;
     RECT  78.401 83.904 78.797 84.168 ;
     RECT  78.304 40.56 78.947 40.872 ;
     RECT  78.304 65.712 78.947 65.832 ;
     RECT  78.304 68.064 78.985 68.088 ;
     RECT  78.947 40.56 80.708 40.584 ;
     RECT  78.304 44.064 80.708 47.688 ;
     RECT  78.304 51.696 80.708 51.72 ;
     RECT  78.947 65.712 80.708 65.736 ;
     RECT  78.797 84.048 80.708 84.168 ;
     RECT  80.233 85.392 80.708 85.416 ;
     RECT  78.304 87.264 80.708 90.888 ;
     RECT  78.304 95.952 80.708 96.744 ;
     RECT  78.304 98.928 80.708 98.952 ;
     RECT  78.304 117.84 80.708 117.864 ;
     RECT  78.304 125.904 80.708 127.272 ;
     RECT  78.304 130.32 80.708 132.216 ;
     RECT  78.304 139.92 80.708 139.944 ;
     RECT  80.708 2.148 80.812 168.492 ;
     RECT  80.812 2.418 81.004 168.222 ;
     RECT  81.004 87.264 82.105 90.888 ;
     RECT  81.004 84.048 83.005 84.168 ;
     RECT  81.004 125.952 83.113 127.272 ;
     RECT  83.005 84.048 83.269 84.36 ;
     RECT  81.004 40.56 83.408 40.584 ;
     RECT  81.004 44.064 83.408 47.688 ;
     RECT  81.004 51.696 83.408 51.72 ;
     RECT  81.004 65.712 83.408 65.736 ;
     RECT  83.269 77.952 83.408 77.976 ;
     RECT  83.269 83.616 83.408 84.36 ;
     RECT  81.004 85.392 83.408 85.416 ;
     RECT  82.105 86.544 83.408 90.888 ;
     RECT  81.004 95.952 83.408 96.744 ;
     RECT  81.004 98.928 83.408 98.952 ;
     RECT  81.004 117.84 83.408 117.864 ;
     RECT  83.113 125.712 83.408 127.272 ;
     RECT  81.004 130.32 83.408 132.216 ;
     RECT  81.004 139.92 83.408 139.944 ;
     RECT  83.408 2.148 83.512 168.492 ;
     RECT  83.512 2.418 83.704 168.222 ;
     RECT  83.704 130.32 83.837 132.216 ;
     RECT  83.704 117.84 84.659 117.864 ;
     RECT  83.704 116.448 84.665 116.808 ;
     RECT  83.704 77.952 84.953 77.976 ;
     RECT  83.704 84.048 85.093 84.36 ;
     RECT  83.704 85.392 85.669 85.416 ;
     RECT  83.704 138.912 85.993 138.936 ;
     RECT  83.704 40.56 86.108 40.584 ;
     RECT  83.704 44.064 86.108 47.688 ;
     RECT  83.704 51.696 86.108 51.72 ;
     RECT  83.704 65.712 86.108 65.736 ;
     RECT  85.201 77.904 86.108 77.928 ;
     RECT  85.093 83.808 86.108 84.36 ;
     RECT  85.669 85.392 86.108 85.464 ;
     RECT  83.704 86.544 86.108 90.888 ;
     RECT  83.704 95.952 86.108 96.744 ;
     RECT  83.704 98.928 86.108 98.952 ;
     RECT  84.665 116.448 86.108 116.472 ;
     RECT  83.704 125.712 86.108 127.032 ;
     RECT  83.837 130.56 86.108 132.216 ;
     RECT  85.993 138.672 86.108 138.936 ;
     RECT  83.704 139.92 86.108 139.944 ;
     RECT  86.108 2.148 86.212 168.492 ;
     RECT  86.212 2.418 86.404 168.222 ;
     RECT  86.404 83.808 86.645 84.36 ;
     RECT  86.404 125.712 86.645 127.032 ;
     RECT  86.404 77.808 86.753 77.928 ;
     RECT  86.404 138.672 86.933 138.696 ;
     RECT  86.404 139.92 87.437 139.944 ;
     RECT  86.404 116.448 88.357 116.472 ;
     RECT  86.645 125.856 88.508 127.032 ;
     RECT  86.404 40.56 88.808 40.584 ;
     RECT  86.404 44.064 88.808 47.688 ;
     RECT  86.404 51.696 88.808 51.72 ;
     RECT  86.404 65.712 88.808 65.736 ;
     RECT  86.753 77.904 88.808 77.928 ;
     RECT  86.645 83.904 88.808 84.36 ;
     RECT  86.404 85.44 88.808 85.464 ;
     RECT  86.404 86.496 88.808 90.888 ;
     RECT  86.404 95.952 88.808 96.744 ;
     RECT  86.404 98.928 88.808 98.952 ;
     RECT  88.357 116.256 88.808 116.472 ;
     RECT  88.508 125.28 88.808 127.032 ;
     RECT  86.404 130.56 88.808 132.216 ;
     RECT  87.541 138.576 88.808 138.6 ;
     RECT  87.685 140.208 88.808 140.232 ;
     RECT  88.808 2.148 88.912 168.492 ;
     RECT  88.912 2.418 89.104 168.222 ;
     RECT  89.104 42.144 89.219 42.168 ;
     RECT  89.104 43.536 89.219 47.688 ;
     RECT  89.104 39.936 89.267 40.584 ;
     RECT  89.104 54.672 89.267 57.144 ;
     RECT  89.104 115.728 89.309 116.28 ;
     RECT  89.309 115.728 89.356 116.184 ;
     RECT  89.104 52.704 89.381 53.592 ;
     RECT  89.104 108 89.459 108.264 ;
     RECT  89.356 115.728 89.459 115.848 ;
     RECT  89.104 100.08 89.603 100.68 ;
     RECT  89.459 115.728 89.641 115.752 ;
     RECT  89.104 77.904 89.795 78.072 ;
     RECT  89.795 78.048 90.035 78.072 ;
     RECT  89.104 81.84 90.035 82.68 ;
     RECT  89.104 83.76 90.205 84.408 ;
     RECT  89.104 85.44 90.205 85.464 ;
     RECT  89.267 39.936 90.241 39.96 ;
     RECT  89.104 98.928 90.241 98.952 ;
     RECT  89.603 100.08 90.241 100.584 ;
     RECT  89.381 53.568 90.277 53.592 ;
     RECT  89.267 54.72 90.277 57.144 ;
     RECT  90.241 98.928 90.277 100.584 ;
     RECT  90.205 83.76 90.349 85.464 ;
     RECT  90.277 98.592 90.421 100.584 ;
     RECT  89.104 95.952 90.457 97.176 ;
     RECT  90.421 98.352 90.457 100.584 ;
     RECT  89.104 141.072 90.565 141.288 ;
     RECT  90.277 53.568 90.601 57.144 ;
     RECT  90.349 83.664 90.601 85.464 ;
     RECT  89.104 86.496 90.601 90.888 ;
     RECT  89.104 51.696 90.637 51.72 ;
     RECT  90.457 95.952 90.637 100.584 ;
     RECT  90.601 83.664 90.673 90.888 ;
     RECT  90.565 141.072 90.673 141.624 ;
     RECT  90.205 143.088 90.673 143.112 ;
     RECT  89.219 43.536 90.709 47.448 ;
     RECT  90.812 41.28 90.853 41.304 ;
     RECT  90.709 42.768 90.853 47.448 ;
     RECT  90.673 141.072 90.961 143.112 ;
     RECT  90.035 81.84 91.105 82.248 ;
     RECT  90.673 83.568 91.105 90.888 ;
     RECT  90.637 95.952 91.105 100.872 ;
     RECT  89.104 125.856 91.177 127.272 ;
     RECT  89.104 138.576 91.213 139.272 ;
     RECT  90.853 50.304 91.237 50.328 ;
     RECT  90.637 51.456 91.237 51.72 ;
     RECT  90.601 52.8 91.321 57.144 ;
     RECT  90.241 38.976 91.349 39.96 ;
     RECT  90.853 41.28 91.349 47.448 ;
     RECT  91.105 95.952 91.381 100.92 ;
     RECT  90.565 129.216 91.381 129.24 ;
     RECT  91.105 81.84 91.429 90.888 ;
     RECT  91.349 38.976 91.508 47.448 ;
     RECT  91.237 50.304 91.508 51.72 ;
     RECT  91.321 52.752 91.508 57.144 ;
     RECT  89.104 65.712 91.508 65.736 ;
     RECT  91.429 81.072 91.508 90.888 ;
     RECT  91.381 95.952 91.508 101.112 ;
     RECT  89.459 108 91.508 108.024 ;
     RECT  91.177 125.616 91.508 127.272 ;
     RECT  91.381 129.12 91.508 129.24 ;
     RECT  89.104 130.56 91.508 132.216 ;
     RECT  91.213 138.576 91.508 139.416 ;
     RECT  90.961 140.4 91.508 143.112 ;
     RECT  91.508 2.148 91.612 168.492 ;
     RECT  91.612 2.418 91.804 168.222 ;
     RECT  91.804 50.304 91.865 50.328 ;
     RECT  91.804 46.272 92.045 47.448 ;
     RECT  91.804 130.56 92.333 132.216 ;
     RECT  91.804 52.464 92.405 57.48 ;
     RECT  91.804 82.224 92.477 90.648 ;
     RECT  91.804 138.48 92.771 143.736 ;
     RECT  92.477 82.224 92.797 90.504 ;
     RECT  91.804 81.072 92.821 81.096 ;
     RECT  92.821 80.784 92.869 81.096 ;
     RECT  91.804 125.616 92.869 127.704 ;
     RECT  91.804 38.736 92.905 40.584 ;
     RECT  91.804 41.712 92.905 45.192 ;
     RECT  92.797 82.08 92.945 90.504 ;
     RECT  92.333 132.192 92.945 132.216 ;
     RECT  92.045 46.32 93.013 47.448 ;
     RECT  91.804 129.36 93.013 129.384 ;
     RECT  92.965 50.16 93.109 50.184 ;
     RECT  91.804 51.456 93.157 51.48 ;
     RECT  92.405 52.464 93.157 53.064 ;
     RECT  93.109 50.16 93.197 50.424 ;
     RECT  92.869 80.256 93.229 81.096 ;
     RECT  92.945 82.08 93.229 88.488 ;
     RECT  93.157 51.456 93.373 53.064 ;
     RECT  92.405 54.048 93.373 57.48 ;
     RECT  93.349 78.048 93.373 78.072 ;
     RECT  93.013 128.832 93.397 129.384 ;
     RECT  92.945 89.664 93.445 90.504 ;
     RECT  92.869 124.56 93.517 127.704 ;
     RECT  93.397 128.736 93.517 129.384 ;
     RECT  91.804 95.952 93.589 101.208 ;
     RECT  91.804 65.712 93.637 65.736 ;
     RECT  93.373 78 93.733 78.072 ;
     RECT  93.013 46.32 93.769 47.784 ;
     RECT  93.589 95.952 93.816 101.64 ;
     RECT  92.905 38.736 93.925 45.192 ;
     RECT  93.517 124.56 94.021 129.384 ;
     RECT  92.333 130.56 94.021 131.16 ;
     RECT  93.877 71.472 94.069 71.496 ;
     RECT  93.816 95.76 94.069 101.64 ;
     RECT  94.021 124.56 94.069 131.16 ;
     RECT  92.771 138.96 94.069 143.736 ;
     RECT  93.925 37.92 94.208 45.192 ;
     RECT  93.769 46.32 94.208 47.88 ;
     RECT  93.197 50.16 94.208 50.184 ;
     RECT  93.373 51.456 94.208 57.48 ;
     RECT  93.637 65.712 94.208 66.696 ;
     RECT  94.069 71.472 94.208 71.64 ;
     RECT  94.049 72.912 94.208 72.936 ;
     RECT  94.093 75.792 94.208 75.816 ;
     RECT  93.733 78 94.208 78.456 ;
     RECT  93.229 80.256 94.208 88.488 ;
     RECT  93.445 89.664 94.208 90.6 ;
     RECT  94.069 95.376 94.208 101.64 ;
     RECT  94.069 124.56 94.208 131.88 ;
     RECT  94.069 138.96 94.208 144.312 ;
     RECT  94.208 2.148 94.312 168.492 ;
     RECT  94.312 2.418 94.504 168.222 ;
     RECT  94.504 46.32 94.637 46.344 ;
     RECT  94.504 71.472 94.673 71.928 ;
     RECT  94.504 75.792 94.673 75.816 ;
     RECT  94.504 129.792 94.673 130.008 ;
     RECT  94.504 74.64 94.684 74.76 ;
     RECT  94.504 89.664 94.817 90.12 ;
     RECT  94.504 131.04 94.853 131.064 ;
     RECT  94.817 89.664 94.925 90.072 ;
     RECT  94.673 129.984 94.931 130.008 ;
     RECT  94.504 138.96 95.069 144.312 ;
     RECT  94.925 89.664 95.075 89.688 ;
     RECT  94.504 37.92 95.141 44.616 ;
     RECT  95.069 138.96 95.171 144.264 ;
     RECT  94.673 71.472 95.213 71.496 ;
     RECT  94.504 51.456 95.285 57.672 ;
     RECT  95.141 38.112 95.393 44.616 ;
     RECT  94.504 80.256 95.393 87.288 ;
     RECT  95.171 138.96 95.429 143.736 ;
     RECT  95.393 80.256 95.501 87.24 ;
     RECT  94.504 124.56 95.645 128.328 ;
     RECT  95.429 138.96 95.699 143.688 ;
     RECT  95.699 138.96 95.708 143.592 ;
     RECT  95.285 51.888 95.749 57.672 ;
     RECT  94.504 95.376 95.749 102.12 ;
     RECT  95.645 124.656 95.795 128.328 ;
     RECT  95.708 138.72 95.795 143.592 ;
     RECT  95.501 80.304 95.843 87.24 ;
     RECT  95.749 51.888 95.861 57.96 ;
     RECT  95.393 38.112 95.933 43.944 ;
     RECT  95.861 52.224 95.933 57.96 ;
     RECT  95.843 80.304 95.933 80.328 ;
     RECT  95.749 95.376 95.933 102.216 ;
     RECT  95.795 124.752 95.933 128.328 ;
     RECT  95.795 138.96 95.933 143.592 ;
     RECT  95.749 73.488 96.035 73.512 ;
     RECT  95.933 96.336 96.179 102.216 ;
     RECT  95.843 81.36 96.227 87.24 ;
     RECT  96.179 96.336 96.227 102.072 ;
     RECT  95.933 125.136 96.227 128.28 ;
     RECT  95.933 38.88 96.275 43.944 ;
     RECT  95.933 52.56 96.275 57.96 ;
     RECT  96.227 81.36 96.275 86.664 ;
     RECT  96.227 96.336 96.275 101.544 ;
     RECT  96.227 125.136 96.275 127.752 ;
     RECT  96.275 38.88 96.323 43.368 ;
     RECT  96.275 52.56 96.323 57.624 ;
     RECT  96.275 81.36 96.323 86.136 ;
     RECT  96.275 96.336 96.323 100.92 ;
     RECT  96.275 125.136 96.323 127.128 ;
     RECT  96.323 38.88 96.901 43.224 ;
     RECT  96.901 38.736 98.22 43.224 ;
     RECT  96.323 52.56 98.22 57.048 ;
     RECT  96.323 81.36 98.22 85.848 ;
     RECT  96.323 96.336 98.22 100.824 ;
     RECT  96.323 125.136 98.22 126.888 ;
     RECT  95.933 138.96 98.22 143.448 ;
    LAYER M5 ;
     RECT  2.4 2.137 2.52 2.151 ;
     RECT  5.1 2.137 5.22 2.151 ;
     RECT  7.8 2.137 7.92 2.151 ;
     RECT  10.5 2.137 10.62 2.151 ;
     RECT  13.2 2.137 13.32 2.151 ;
     RECT  15.9 2.137 16.02 2.151 ;
     RECT  18.6 2.137 18.72 2.151 ;
     RECT  21.3 2.137 21.42 2.151 ;
     RECT  24 2.137 24.12 2.151 ;
     RECT  26.7 2.137 26.82 2.151 ;
     RECT  29.4 2.137 29.52 2.151 ;
     RECT  32.1 2.137 32.22 2.151 ;
     RECT  34.8 2.137 34.92 2.151 ;
     RECT  37.5 2.137 37.62 2.151 ;
     RECT  40.2 2.137 40.32 2.151 ;
     RECT  42.9 2.137 43.02 2.151 ;
     RECT  45.6 2.137 45.72 2.151 ;
     RECT  48.3 2.137 48.42 2.151 ;
     RECT  51 2.137 51.12 2.151 ;
     RECT  53.7 2.137 53.82 2.151 ;
     RECT  56.4 2.137 56.52 2.151 ;
     RECT  59.1 2.137 59.22 2.151 ;
     RECT  61.8 2.137 61.92 2.151 ;
     RECT  64.5 2.137 64.62 2.151 ;
     RECT  67.2 2.137 67.32 2.151 ;
     RECT  69.9 2.137 70.02 2.151 ;
     RECT  72.6 2.137 72.72 2.151 ;
     RECT  75.3 2.137 75.42 2.151 ;
     RECT  78 2.137 78.12 2.151 ;
     RECT  80.7 2.137 80.82 2.151 ;
     RECT  83.4 2.137 83.52 2.151 ;
     RECT  86.1 2.137 86.22 2.151 ;
     RECT  88.8 2.137 88.92 2.151 ;
     RECT  91.5 2.137 91.62 2.151 ;
     RECT  94.2 2.137 94.32 2.151 ;
     RECT  2.4 2.151 2.712 32.101 ;
     RECT  7.8 2.151 8.112 33.589 ;
     RECT  2.4 32.101 3.288 33.635 ;
     RECT  6.864 33.589 8.232 34.355 ;
     RECT  7.8 34.355 8.232 35.363 ;
     RECT  7.8 35.363 8.112 36.421 ;
     RECT  5.1 2.151 5.412 36.757 ;
     RECT  94.2 2.151 94.512 37.909 ;
     RECT  93.936 37.909 94.512 38.149 ;
     RECT  91.5 2.151 91.812 39.253 ;
     RECT  93.936 38.149 95.784 39.395 ;
     RECT  95.76 39.395 95.784 39.491 ;
     RECT  91.152 39.253 91.812 39.971 ;
     RECT  93.936 39.395 94.512 40.165 ;
     RECT  88.8 2.151 89.112 40.549 ;
     RECT  2.4 33.635 2.904 40.595 ;
     RECT  95.856 39.829 95.88 40.643 ;
     RECT  78 2.151 78.312 40.837 ;
     RECT  40.2 2.151 40.512 40.885 ;
     RECT  64.5 2.151 64.812 40.981 ;
     RECT  91.392 39.971 91.812 41.269 ;
     RECT  93.216 40.165 94.512 41.555 ;
     RECT  5.1 36.757 6.264 41.605 ;
     RECT  75.3 2.151 75.612 41.605 ;
     RECT  90.864 41.269 91.812 41.797 ;
     RECT  96.288 41.749 96.312 41.893 ;
     RECT  95.712 41.893 96.312 42.037 ;
     RECT  90.864 41.797 92.76 42.757 ;
     RECT  5.1 41.605 6.408 42.803 ;
     RECT  75.168 41.605 75.612 43.091 ;
     RECT  95.664 42.037 96.312 43.379 ;
     RECT  7.8 36.421 8.472 43.717 ;
     RECT  90.72 42.757 92.76 43.765 ;
     RECT  94.2 41.555 94.512 43.765 ;
     RECT  96.24 43.379 96.264 43.955 ;
     RECT  42.9 2.151 43.212 43.957 ;
     RECT  42.72 43.957 43.212 44.053 ;
     RECT  90.72 43.765 93.048 44.483 ;
     RECT  94.2 43.765 95.16 44.483 ;
     RECT  78 40.837 78.936 46.165 ;
     RECT  90.72 44.483 91.812 46.259 ;
     RECT  78 46.165 79.224 47.507 ;
     RECT  92.976 44.483 93.048 47.749 ;
     RECT  94.2 44.483 94.512 47.749 ;
     RECT  7.8 43.717 8.664 49.283 ;
     RECT  92.976 47.749 94.512 50.195 ;
     RECT  90.864 46.259 91.812 50.339 ;
     RECT  37.5 2.151 37.812 50.533 ;
     RECT  39.6 40.885 40.512 50.771 ;
     RECT  75.3 43.091 75.612 51.685 ;
     RECT  37.5 50.533 38.472 52.645 ;
     RECT  93.12 50.195 94.512 52.885 ;
     RECT  93.12 52.885 94.68 52.933 ;
     RECT  95.808 52.309 95.832 52.933 ;
     RECT  39.792 50.771 40.512 52.981 ;
     RECT  41.568 44.341 41.592 52.981 ;
     RECT  93.12 52.933 95.832 53.315 ;
     RECT  91.248 50.339 91.812 53.557 ;
     RECT  93.12 53.315 95.64 53.603 ;
     RECT  37.5 52.645 38.712 53.651 ;
     RECT  95.616 53.603 95.64 53.747 ;
     RECT  91.2 53.557 91.812 54.083 ;
     RECT  88.8 40.549 89.256 54.707 ;
     RECT  91.248 54.083 91.812 55.045 ;
     RECT  91.248 55.045 91.944 55.189 ;
     RECT  95.712 55.141 95.736 55.429 ;
     RECT  95.616 55.429 95.736 55.813 ;
     RECT  91.152 55.189 91.944 55.907 ;
     RECT  93.12 53.603 94.512 55.907 ;
     RECT  93.792 55.907 94.512 55.957 ;
     RECT  95.616 55.813 95.832 55.957 ;
     RECT  91.248 55.907 91.944 56.003 ;
     RECT  91.392 56.003 91.944 56.291 ;
     RECT  93.792 55.957 95.832 56.437 ;
     RECT  91.392 56.291 91.812 56.531 ;
     RECT  88.8 54.707 89.112 56.917 ;
     RECT  93.792 56.437 96.312 57.059 ;
     RECT  95.664 57.059 96.312 57.635 ;
     RECT  93.792 57.059 94.68 57.683 ;
     RECT  96.24 57.635 96.264 57.971 ;
     RECT  39.792 52.981 41.592 60.611 ;
     RECT  75.3 51.685 75.72 60.611 ;
     RECT  42.672 44.053 43.212 64.741 ;
     RECT  45.6 2.151 45.912 64.933 ;
     RECT  64.5 40.981 64.968 65.701 ;
     RECT  93.792 57.683 94.512 65.701 ;
     RECT  78 47.507 78.312 65.797 ;
     RECT  93.648 65.701 94.512 66.707 ;
     RECT  78 65.797 78.936 68.099 ;
     RECT  78 68.099 78.312 68.149 ;
     RECT  77.904 68.149 78.312 70.597 ;
     RECT  77.328 70.597 78.312 72.995 ;
     RECT  5.1 42.803 5.976 73.235 ;
     RECT  75.3 60.611 75.612 73.285 ;
     RECT  93.744 66.707 94.512 74.629 ;
     RECT  93.744 74.629 94.632 74.771 ;
     RECT  39.792 60.611 40.512 76.069 ;
     RECT  83.4 2.151 83.712 77.941 ;
     RECT  64.5 65.701 65.688 78.037 ;
     RECT  67.2 2.151 67.512 78.037 ;
     RECT  88.8 56.917 89.784 78.037 ;
     RECT  93.744 74.771 94.512 78.037 ;
     RECT  64.5 78.037 67.512 78.419 ;
     RECT  5.1 73.235 5.784 79.045 ;
     RECT  7.8 49.283 8.112 79.573 ;
     RECT  42.672 64.741 43.32 79.573 ;
     RECT  93.36 78.037 94.512 80.245 ;
     RECT  5.1 79.045 5.88 80.291 ;
     RECT  92.88 80.245 94.512 80.293 ;
     RECT  96 73.477 96.024 80.293 ;
     RECT  92.88 80.293 96.024 80.773 ;
     RECT  7.152 79.573 8.112 81.061 ;
     RECT  6.864 81.061 8.112 81.445 ;
     RECT  6.864 81.445 8.376 81.635 ;
     RECT  92.832 80.773 96.024 81.923 ;
     RECT  5.1 80.291 5.784 82.021 ;
     RECT  92.832 81.923 95.736 82.115 ;
     RECT  42.624 79.573 43.32 82.213 ;
     RECT  41.568 60.611 41.592 82.501 ;
     RECT  42.576 82.213 43.32 82.501 ;
     RECT  4.464 82.021 5.784 82.691 ;
     RECT  88.8 78.037 90.024 82.691 ;
     RECT  7.8 81.635 8.376 82.835 ;
     RECT  5.1 82.691 5.784 83.077 ;
     RECT  2.4 40.595 2.712 83.173 ;
     RECT  64.5 78.419 65.4 83.267 ;
     RECT  91.5 56.531 91.812 83.653 ;
     RECT  37.5 53.651 37.812 83.749 ;
     RECT  39.168 76.069 40.512 83.749 ;
     RECT  88.8 82.691 89.112 83.749 ;
     RECT  91.5 83.653 91.944 83.749 ;
     RECT  93.312 82.115 95.736 83.749 ;
     RECT  91.5 83.749 95.832 83.797 ;
     RECT  72.6 2.151 72.912 83.941 ;
     RECT  53.7 2.151 54.012 84.037 ;
     RECT  5.1 83.077 5.832 84.083 ;
     RECT  66.624 78.419 67.512 84.083 ;
     RECT  72.6 83.941 73.032 84.083 ;
     RECT  83.28 77.941 83.712 84.083 ;
     RECT  53.7 84.037 54.744 84.179 ;
     RECT  75.3 73.285 76.056 84.179 ;
     RECT  88.8 83.749 89.448 84.181 ;
     RECT  91.5 83.797 96.312 84.325 ;
     RECT  41.568 82.501 43.32 84.371 ;
     RECT  88.8 84.181 90.408 84.419 ;
     RECT  91.392 84.325 96.312 84.419 ;
     RECT  90.384 84.419 90.408 84.707 ;
     RECT  7.8 82.835 8.232 84.995 ;
     RECT  5.1 84.083 5.784 85.381 ;
     RECT  91.392 84.419 91.812 85.381 ;
     RECT  91.248 85.381 91.812 85.813 ;
     RECT  92.784 84.419 96.312 85.813 ;
     RECT  2.4 83.173 3.144 85.955 ;
     RECT  7.8 84.995 8.112 86.005 ;
     RECT  37.5 83.749 40.512 86.005 ;
     RECT  41.568 84.371 43.212 86.005 ;
     RECT  91.248 85.813 96.312 86.147 ;
     RECT  7.8 86.005 8.232 86.675 ;
     RECT  91.248 86.147 96.264 86.675 ;
     RECT  2.4 85.955 2.712 86.677 ;
     RECT  2.256 86.677 2.712 86.819 ;
     RECT  91.248 86.675 95.064 87.061 ;
     RECT  96.192 86.675 96.216 87.251 ;
     RECT  5.1 85.381 5.976 87.923 ;
     RECT  91.104 87.061 95.064 88.403 ;
     RECT  91.104 88.403 91.812 88.453 ;
     RECT  75.3 84.179 75.612 88.645 ;
     RECT  90.624 88.453 91.812 88.691 ;
     RECT  75.3 88.645 75.816 88.787 ;
     RECT  91.104 88.691 91.812 89.075 ;
     RECT  93.024 88.403 95.064 89.699 ;
     RECT  91.152 89.075 91.812 90.083 ;
     RECT  93.024 89.699 94.512 90.083 ;
     RECT  21.3 2.151 21.612 93.061 ;
     RECT  22.656 73.285 22.68 93.061 ;
     RECT  93.168 90.083 94.512 95.605 ;
     RECT  95.808 95.509 95.832 95.605 ;
     RECT  93.168 95.605 95.832 96.133 ;
     RECT  75.3 88.787 75.612 96.229 ;
     RECT  88.8 84.419 89.208 96.515 ;
     RECT  75.3 96.229 75.72 96.709 ;
     RECT  91.296 90.083 91.812 97.045 ;
     RECT  92.88 96.133 95.832 97.045 ;
     RECT  91.296 97.045 95.832 97.141 ;
     RECT  37.5 86.005 43.212 97.523 ;
     RECT  90.48 97.141 95.832 97.763 ;
     RECT  91.296 97.763 95.832 98.099 ;
     RECT  91.5 98.099 95.832 98.147 ;
     RECT  94.032 98.147 95.832 98.197 ;
     RECT  91.5 98.147 92.904 98.579 ;
     RECT  92.832 98.579 92.904 98.675 ;
     RECT  94.032 98.197 95.976 98.675 ;
     RECT  92.88 98.675 92.904 98.867 ;
     RECT  91.5 98.579 91.812 99.637 ;
     RECT  94.2 98.675 95.976 99.637 ;
     RECT  88.8 96.515 89.112 100.069 ;
     RECT  94.2 99.637 96.312 100.117 ;
     RECT  91.296 99.637 91.812 100.547 ;
     RECT  93.6 100.117 96.312 100.931 ;
     RECT  93.6 100.931 96.264 101.507 ;
     RECT  96.144 101.507 96.264 101.555 ;
     RECT  93.6 101.507 95.112 101.651 ;
     RECT  96.144 101.555 96.216 102.083 ;
     RECT  94.2 101.651 95.112 102.131 ;
     RECT  96.144 102.083 96.168 102.227 ;
     RECT  75.3 96.709 75.816 103.907 ;
     RECT  75.3 103.907 75.72 103.955 ;
     RECT  64.5 83.267 65.256 105.491 ;
     RECT  64.5 105.491 64.812 106.549 ;
     RECT  64.5 106.549 64.968 107.699 ;
     RECT  44.784 64.933 45.912 107.843 ;
     RECT  91.392 100.547 91.812 108.035 ;
     RECT  61.8 2.151 62.112 108.133 ;
     RECT  39.744 97.523 43.212 108.517 ;
     RECT  37.5 97.523 38.472 109.381 ;
     RECT  39.744 108.517 43.32 114.035 ;
     RECT  88.8 100.069 89.592 115.763 ;
     RECT  88.8 115.763 89.448 115.859 ;
     RECT  88.8 115.859 89.304 116.245 ;
     RECT  88.368 116.245 89.304 116.483 ;
     RECT  83.4 84.083 83.712 116.773 ;
     RECT  37.5 109.381 38.568 119.747 ;
     RECT  21.3 93.061 22.68 120.035 ;
     RECT  24 2.151 24.312 120.661 ;
     RECT  34.8 2.151 35.112 122.917 ;
     RECT  36.144 117.829 36.168 122.917 ;
     RECT  39.744 114.035 41.16 123.731 ;
     RECT  75.3 103.955 75.612 124.261 ;
     RECT  73.92 123.061 73.944 124.501 ;
     RECT  75.3 124.261 75.768 124.501 ;
     RECT  94.2 102.131 94.512 124.645 ;
     RECT  94.032 124.645 94.512 124.741 ;
     RECT  95.568 124.645 95.784 124.741 ;
     RECT  37.5 119.747 38.472 124.789 ;
     RECT  94.032 124.741 95.784 124.789 ;
     RECT  73.92 124.501 75.768 124.835 ;
     RECT  42.72 114.035 43.32 124.837 ;
     RECT  2.4 86.819 2.712 125.173 ;
     RECT  2.304 125.173 2.712 125.315 ;
     RECT  92.88 124.549 92.904 125.365 ;
     RECT  94.032 124.789 95.832 125.365 ;
     RECT  42.624 124.837 43.32 125.413 ;
     RECT  92.88 125.365 95.832 125.459 ;
     RECT  78 72.995 78.312 125.701 ;
     RECT  5.1 87.923 5.412 125.749 ;
     RECT  74.544 124.835 75.768 125.891 ;
     RECT  88.56 116.483 89.304 125.891 ;
     RECT  42.576 125.413 43.32 125.989 ;
     RECT  91.5 108.035 91.812 125.989 ;
     RECT  92.976 125.459 95.832 125.989 ;
     RECT  92.976 125.989 95.88 126.277 ;
     RECT  37.296 124.789 38.472 126.469 ;
     RECT  77.472 125.701 78.312 126.517 ;
     RECT  4.224 125.749 5.412 126.563 ;
     RECT  92.976 126.277 96.312 126.563 ;
     RECT  88.8 125.891 89.304 126.611 ;
     RECT  75.12 125.891 75.768 126.659 ;
     RECT  77.472 126.517 78.648 126.755 ;
     RECT  42.384 125.989 43.32 126.949 ;
     RECT  75.3 126.659 75.768 126.949 ;
     RECT  24 120.661 24.936 126.995 ;
     RECT  7.8 86.675 8.112 126.997 ;
     RECT  93.456 126.563 96.312 127.139 ;
     RECT  75.3 126.949 75.816 127.283 ;
     RECT  61.8 108.133 63.096 127.379 ;
     RECT  5.1 126.563 5.412 127.621 ;
     RECT  93.456 127.139 96.264 127.715 ;
     RECT  96.192 127.715 96.264 127.763 ;
     RECT  39.744 123.731 41.016 127.811 ;
     RECT  93.456 127.715 95.16 127.811 ;
     RECT  93.456 127.811 95.064 127.907 ;
     RECT  96.192 127.763 96.216 128.291 ;
     RECT  39.888 127.811 41.016 128.579 ;
     RECT  93.456 127.907 94.92 128.725 ;
     RECT  93.408 128.725 94.92 129.109 ;
     RECT  91.392 125.989 91.812 129.205 ;
     RECT  90.576 129.205 91.812 129.349 ;
     RECT  42.24 126.949 43.32 129.491 ;
     RECT  40.2 128.579 41.016 129.925 ;
     RECT  93.36 129.109 94.92 130.019 ;
     RECT  5.1 127.621 5.544 130.067 ;
     RECT  75.3 127.283 75.768 130.213 ;
     RECT  75.3 130.213 75.816 130.355 ;
     RECT  2.4 125.315 2.712 130.357 ;
     RECT  34.8 122.917 36.168 130.885 ;
     RECT  37.152 126.469 38.472 130.885 ;
     RECT  77.472 126.755 78.312 130.885 ;
     RECT  77.472 130.885 78.696 131.075 ;
     RECT  5.1 130.067 5.412 131.077 ;
     RECT  83.4 116.773 84.648 131.077 ;
     RECT  90.576 129.349 92.328 131.123 ;
     RECT  93.36 130.019 94.512 131.171 ;
     RECT  2.4 130.357 3.384 131.267 ;
     RECT  82.656 131.077 84.648 131.315 ;
     RECT  7.8 126.997 8.232 131.555 ;
     RECT  5.1 131.077 5.544 131.699 ;
     RECT  34.8 130.885 38.472 131.699 ;
     RECT  42.24 129.491 43.212 131.843 ;
     RECT  75.3 130.355 75.768 131.845 ;
     RECT  94.08 131.171 94.512 131.891 ;
     RECT  42.336 131.843 43.212 131.939 ;
     RECT  75.3 131.845 75.816 131.987 ;
     RECT  34.8 131.699 35.736 132.131 ;
     RECT  77.472 131.075 78.312 132.899 ;
     RECT  42.384 131.939 43.212 133.571 ;
     RECT  37.152 131.699 38.472 133.861 ;
     RECT  36.72 133.861 38.472 133.957 ;
     RECT  39.792 129.925 41.016 134.003 ;
     RECT  75.3 131.987 75.768 134.051 ;
     RECT  78 132.899 78.312 134.485 ;
     RECT  36.72 133.957 38.664 134.579 ;
     RECT  34.8 132.131 35.448 136.021 ;
     RECT  36.72 134.579 38.616 136.979 ;
     RECT  34.8 136.021 35.544 137.027 ;
     RECT  34.8 137.027 35.352 138.469 ;
     RECT  91.5 131.123 91.812 138.469 ;
     RECT  91.5 138.469 92.76 138.565 ;
     RECT  37.152 136.979 38.616 138.707 ;
     RECT  83.4 131.315 84.648 138.947 ;
     RECT  94.2 131.891 94.512 138.997 ;
     RECT  95.76 138.709 95.784 138.997 ;
     RECT  94.2 138.997 95.784 139.045 ;
     RECT  91.2 138.565 92.76 139.187 ;
     RECT  94.2 139.045 95.832 139.333 ;
     RECT  40.2 134.003 41.016 139.525 ;
     RECT  93.408 139.333 95.832 139.907 ;
     RECT  77.568 134.485 78.312 139.955 ;
     RECT  94.2 139.907 95.832 140.003 ;
     RECT  39.888 139.525 41.016 140.243 ;
     RECT  37.152 138.707 38.568 140.819 ;
     RECT  91.2 139.187 91.812 140.867 ;
     RECT  34.8 138.469 35.544 141.011 ;
     RECT  94.2 140.003 95.352 141.013 ;
     RECT  93.456 141.013 95.352 141.155 ;
     RECT  91.5 140.867 91.812 141.157 ;
     RECT  91.5 141.157 92.328 141.253 ;
     RECT  93.456 141.155 94.512 141.253 ;
     RECT  37.392 140.819 38.568 141.301 ;
     RECT  91.5 141.253 94.512 141.925 ;
     RECT  91.152 141.925 94.512 142.019 ;
     RECT  93.456 142.019 94.512 142.405 ;
     RECT  95.712 142.405 95.736 142.453 ;
     RECT  91.152 142.019 92.328 142.547 ;
     RECT  93.456 142.405 94.632 142.547 ;
     RECT  95.712 142.453 95.928 142.549 ;
     RECT  91.344 142.547 92.328 142.691 ;
     RECT  95.664 142.549 95.928 142.739 ;
     RECT  94.08 142.547 94.632 143.029 ;
     RECT  95.664 142.739 95.736 143.029 ;
     RECT  94.08 143.029 95.736 143.123 ;
     RECT  91.5 142.691 92.328 143.315 ;
     RECT  40.2 140.243 41.016 143.699 ;
     RECT  94.08 143.123 95.688 143.699 ;
     RECT  91.5 143.315 92.28 143.747 ;
     RECT  21.3 120.035 22.104 144.035 ;
     RECT  94.08 143.699 95.16 144.275 ;
     RECT  94.08 144.275 94.512 144.323 ;
     RECT  37.392 141.301 38.712 145.955 ;
     RECT  37.392 145.955 38.568 146.965 ;
     RECT  37.392 146.965 38.76 150.179 ;
     RECT  37.392 150.179 38.568 164.291 ;
     RECT  37.392 164.291 38.472 165.347 ;
     RECT  37.5 165.347 38.28 167.603 ;
     RECT  2.4 131.267 2.712 168.489 ;
     RECT  5.1 131.699 5.412 168.489 ;
     RECT  7.8 131.555 8.112 168.489 ;
     RECT  10.5 2.151 10.812 168.489 ;
     RECT  13.2 2.151 13.512 168.489 ;
     RECT  15.9 2.151 16.212 168.489 ;
     RECT  18.6 2.151 18.912 168.489 ;
     RECT  21.3 144.035 21.612 168.489 ;
     RECT  24 126.995 24.312 168.489 ;
     RECT  26.7 2.151 27.012 168.489 ;
     RECT  29.4 2.151 29.712 168.489 ;
     RECT  32.1 2.151 32.412 168.489 ;
     RECT  34.8 141.011 35.112 168.489 ;
     RECT  40.2 143.699 40.512 168.489 ;
     RECT  42.9 133.571 43.212 168.489 ;
     RECT  45.6 107.843 45.912 168.489 ;
     RECT  48.3 2.151 48.612 168.489 ;
     RECT  51 2.151 51.312 168.489 ;
     RECT  53.7 84.179 54.012 168.489 ;
     RECT  56.4 2.151 56.712 168.489 ;
     RECT  59.1 2.151 59.412 168.489 ;
     RECT  61.8 127.379 62.112 168.489 ;
     RECT  64.5 107.699 64.812 168.489 ;
     RECT  67.2 84.083 67.512 168.489 ;
     RECT  69.9 2.151 70.212 168.489 ;
     RECT  72.6 84.083 72.912 168.489 ;
     RECT  75.3 134.051 75.612 168.489 ;
     RECT  78 139.955 78.312 168.489 ;
     RECT  80.7 2.151 81.012 168.489 ;
     RECT  83.4 138.947 83.712 168.489 ;
     RECT  86.1 2.151 86.412 168.489 ;
     RECT  88.8 126.611 89.112 168.489 ;
     RECT  91.5 143.747 91.812 168.489 ;
     RECT  94.2 144.323 94.512 168.489 ;
     RECT  2.4 168.489 2.52 168.503 ;
     RECT  5.1 168.489 5.22 168.503 ;
     RECT  7.8 168.489 7.92 168.503 ;
     RECT  10.5 168.489 10.62 168.503 ;
     RECT  13.2 168.489 13.32 168.503 ;
     RECT  15.9 168.489 16.02 168.503 ;
     RECT  18.6 168.489 18.72 168.503 ;
     RECT  21.3 168.489 21.42 168.503 ;
     RECT  24 168.489 24.12 168.503 ;
     RECT  26.7 168.489 26.82 168.503 ;
     RECT  29.4 168.489 29.52 168.503 ;
     RECT  32.1 168.489 32.22 168.503 ;
     RECT  34.8 168.489 34.92 168.503 ;
     RECT  37.5 167.603 38.136 168.503 ;
     RECT  40.2 168.489 40.32 168.503 ;
     RECT  42.9 168.489 43.02 168.503 ;
     RECT  45.6 168.489 45.72 168.503 ;
     RECT  48.3 168.489 48.42 168.503 ;
     RECT  51 168.489 51.12 168.503 ;
     RECT  53.7 168.489 53.82 168.503 ;
     RECT  56.4 168.489 56.52 168.503 ;
     RECT  59.1 168.489 59.22 168.503 ;
     RECT  61.8 168.489 61.92 168.503 ;
     RECT  64.5 168.489 64.62 168.503 ;
     RECT  67.2 168.489 67.32 168.503 ;
     RECT  69.9 168.489 70.02 168.503 ;
     RECT  72.6 168.489 72.72 168.503 ;
     RECT  75.3 168.489 75.42 168.503 ;
     RECT  78 168.489 78.12 168.503 ;
     RECT  80.7 168.489 80.82 168.503 ;
     RECT  83.4 168.489 83.52 168.503 ;
     RECT  86.1 168.489 86.22 168.503 ;
     RECT  88.8 168.489 88.92 168.503 ;
     RECT  91.5 168.489 91.62 168.503 ;
     RECT  94.2 168.489 94.32 168.503 ;
     RECT  37.968 168.503 38.136 170.435 ;
     RECT  37.968 170.435 37.992 170.531 ;
  END
END qfd_landh0d8s_173_EW_98x171
END LIBRARY
